VERSION 5.8 ;
BUSBITCHARS "[]" ;
DIVIDERCHAR "/" ;
UNITS
    DATABASE MICRONS 1000 ;
END UNITS

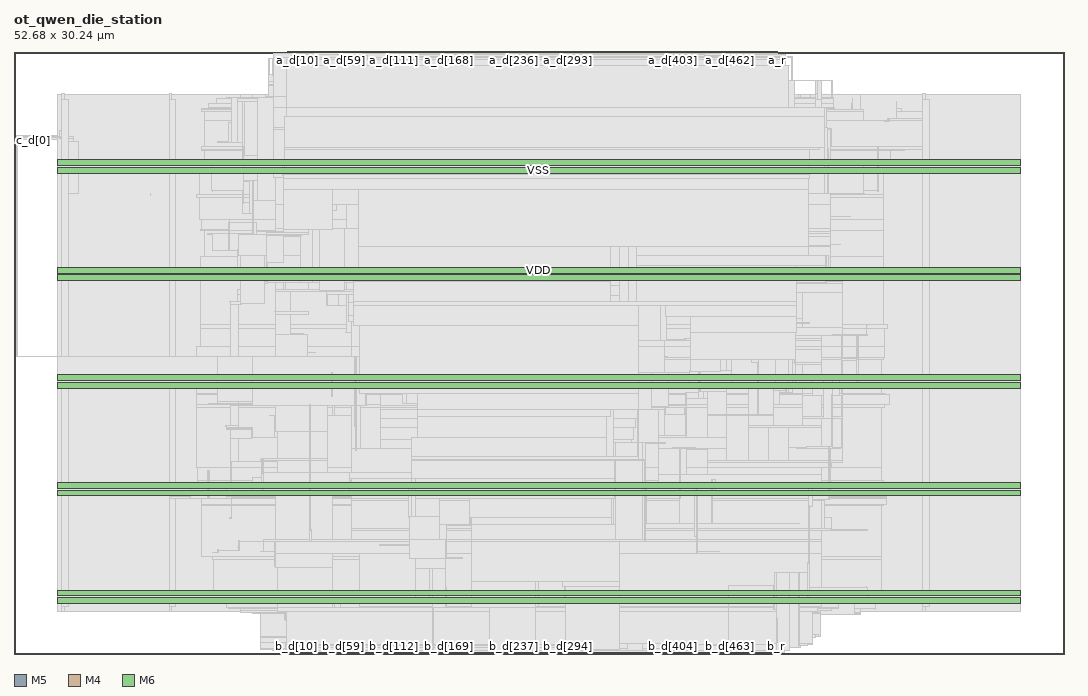
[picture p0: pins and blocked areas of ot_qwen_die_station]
MACRO ot_qwen_die_station
  FOREIGN ot_qwen_die_station 0 0 ;
  CLASS BLOCK ;
  SIZE 52.68 BY 30.24 ;
  PIN a_d[0]
    DIRECTION INPUT ;
    USE SIGNAL ;
    PORT
      LAYER M5 ;
        RECT  13.728 30.156 13.752 30.24 ;
    END
  END a_d[0]
  PIN a_d[100]
    DIRECTION INPUT ;
    USE SIGNAL ;
    PORT
      LAYER M5 ;
        RECT  18.528 30.156 18.552 30.24 ;
    END
  END a_d[100]
  PIN a_d[101]
    DIRECTION INPUT ;
    USE SIGNAL ;
    PORT
      LAYER M5 ;
        RECT  18.576 30.156 18.6 30.24 ;
    END
  END a_d[101]
  PIN a_d[102]
    DIRECTION INPUT ;
    USE SIGNAL ;
    PORT
      LAYER M5 ;
        RECT  18.624 30.156 18.648 30.24 ;
    END
  END a_d[102]
  PIN a_d[103]
    DIRECTION INPUT ;
    USE SIGNAL ;
    PORT
      LAYER M5 ;
        RECT  18.672 30.156 18.696 30.24 ;
    END
  END a_d[103]
  PIN a_d[104]
    DIRECTION INPUT ;
    USE SIGNAL ;
    PORT
      LAYER M5 ;
        RECT  18.72 30.156 18.744 30.24 ;
    END
  END a_d[104]
  PIN a_d[105]
    DIRECTION INPUT ;
    USE SIGNAL ;
    PORT
      LAYER M5 ;
        RECT  18.768 30.156 18.792 30.24 ;
    END
  END a_d[105]
  PIN a_d[106]
    DIRECTION INPUT ;
    USE SIGNAL ;
    PORT
      LAYER M5 ;
        RECT  18.816 30.156 18.84 30.24 ;
    END
  END a_d[106]
  PIN a_d[107]
    DIRECTION INPUT ;
    USE SIGNAL ;
    PORT
      LAYER M5 ;
        RECT  18.864 30.156 18.888 30.24 ;
    END
  END a_d[107]
  PIN a_d[108]
    DIRECTION INPUT ;
    USE SIGNAL ;
    PORT
      LAYER M5 ;
        RECT  18.912 30.156 18.936 30.24 ;
    END
  END a_d[108]
  PIN a_d[109]
    DIRECTION INPUT ;
    USE SIGNAL ;
    PORT
      LAYER M5 ;
        RECT  18.96 30.156 18.984 30.24 ;
    END
  END a_d[109]
  PIN a_d[10]
    DIRECTION INPUT ;
    USE SIGNAL ;
    PORT
      LAYER M5 ;
        RECT  14.208 30.156 14.232 30.24 ;
    END
  END a_d[10]
  PIN a_d[110]
    DIRECTION INPUT ;
    USE SIGNAL ;
    PORT
      LAYER M5 ;
        RECT  19.008 30.156 19.032 30.24 ;
    END
  END a_d[110]
  PIN a_d[111]
    DIRECTION INPUT ;
    USE SIGNAL ;
    PORT
      LAYER M5 ;
        RECT  19.056 30.156 19.08 30.24 ;
    END
  END a_d[111]
  PIN a_d[112]
    DIRECTION INPUT ;
    USE SIGNAL ;
    PORT
      LAYER M5 ;
        RECT  19.104 30.156 19.128 30.24 ;
    END
  END a_d[112]
  PIN a_d[113]
    DIRECTION INPUT ;
    USE SIGNAL ;
    PORT
      LAYER M5 ;
        RECT  19.152 30.156 19.176 30.24 ;
    END
  END a_d[113]
  PIN a_d[114]
    DIRECTION INPUT ;
    USE SIGNAL ;
    PORT
      LAYER M5 ;
        RECT  19.2 30.156 19.224 30.24 ;
    END
  END a_d[114]
  PIN a_d[115]
    DIRECTION INPUT ;
    USE SIGNAL ;
    PORT
      LAYER M5 ;
        RECT  19.248 30.156 19.272 30.24 ;
    END
  END a_d[115]
  PIN a_d[116]
    DIRECTION INPUT ;
    USE SIGNAL ;
    PORT
      LAYER M5 ;
        RECT  19.296 30.156 19.32 30.24 ;
    END
  END a_d[116]
  PIN a_d[117]
    DIRECTION INPUT ;
    USE SIGNAL ;
    PORT
      LAYER M5 ;
        RECT  19.344 30.156 19.368 30.24 ;
    END
  END a_d[117]
  PIN a_d[118]
    DIRECTION INPUT ;
    USE SIGNAL ;
    PORT
      LAYER M5 ;
        RECT  19.392 30.156 19.416 30.24 ;
    END
  END a_d[118]
  PIN a_d[119]
    DIRECTION INPUT ;
    USE SIGNAL ;
    PORT
      LAYER M5 ;
        RECT  19.44 30.156 19.464 30.24 ;
    END
  END a_d[119]
  PIN a_d[11]
    DIRECTION INPUT ;
    USE SIGNAL ;
    PORT
      LAYER M5 ;
        RECT  14.256 30.156 14.28 30.24 ;
    END
  END a_d[11]
  PIN a_d[120]
    DIRECTION INPUT ;
    USE SIGNAL ;
    PORT
      LAYER M5 ;
        RECT  19.488 30.156 19.512 30.24 ;
    END
  END a_d[120]
  PIN a_d[121]
    DIRECTION INPUT ;
    USE SIGNAL ;
    PORT
      LAYER M5 ;
        RECT  19.536 30.156 19.56 30.24 ;
    END
  END a_d[121]
  PIN a_d[122]
    DIRECTION INPUT ;
    USE SIGNAL ;
    PORT
      LAYER M5 ;
        RECT  19.584 30.156 19.608 30.24 ;
    END
  END a_d[122]
  PIN a_d[123]
    DIRECTION INPUT ;
    USE SIGNAL ;
    PORT
      LAYER M5 ;
        RECT  19.632 30.156 19.656 30.24 ;
    END
  END a_d[123]
  PIN a_d[124]
    DIRECTION INPUT ;
    USE SIGNAL ;
    PORT
      LAYER M5 ;
        RECT  19.68 30.156 19.704 30.24 ;
    END
  END a_d[124]
  PIN a_d[125]
    DIRECTION INPUT ;
    USE SIGNAL ;
    PORT
      LAYER M5 ;
        RECT  19.728 30.156 19.752 30.24 ;
    END
  END a_d[125]
  PIN a_d[126]
    DIRECTION INPUT ;
    USE SIGNAL ;
    PORT
      LAYER M5 ;
        RECT  19.776 30.156 19.8 30.24 ;
    END
  END a_d[126]
  PIN a_d[127]
    DIRECTION INPUT ;
    USE SIGNAL ;
    PORT
      LAYER M5 ;
        RECT  19.824 30.156 19.848 30.24 ;
    END
  END a_d[127]
  PIN a_d[128]
    DIRECTION INPUT ;
    USE SIGNAL ;
    PORT
      LAYER M5 ;
        RECT  19.872 30.156 19.896 30.24 ;
    END
  END a_d[128]
  PIN a_d[129]
    DIRECTION INPUT ;
    USE SIGNAL ;
    PORT
      LAYER M5 ;
        RECT  19.92 30.156 19.944 30.24 ;
    END
  END a_d[129]
  PIN a_d[12]
    DIRECTION INPUT ;
    USE SIGNAL ;
    PORT
      LAYER M5 ;
        RECT  14.304 30.156 14.328 30.24 ;
    END
  END a_d[12]
  PIN a_d[130]
    DIRECTION INPUT ;
    USE SIGNAL ;
    PORT
      LAYER M5 ;
        RECT  19.968 30.156 19.992 30.24 ;
    END
  END a_d[130]
  PIN a_d[131]
    DIRECTION INPUT ;
    USE SIGNAL ;
    PORT
      LAYER M5 ;
        RECT  20.016 30.156 20.04 30.24 ;
    END
  END a_d[131]
  PIN a_d[132]
    DIRECTION INPUT ;
    USE SIGNAL ;
    PORT
      LAYER M5 ;
        RECT  20.064 30.156 20.088 30.24 ;
    END
  END a_d[132]
  PIN a_d[133]
    DIRECTION INPUT ;
    USE SIGNAL ;
    PORT
      LAYER M5 ;
        RECT  20.112 30.156 20.136 30.24 ;
    END
  END a_d[133]
  PIN a_d[134]
    DIRECTION INPUT ;
    USE SIGNAL ;
    PORT
      LAYER M5 ;
        RECT  20.16 30.156 20.184 30.24 ;
    END
  END a_d[134]
  PIN a_d[135]
    DIRECTION INPUT ;
    USE SIGNAL ;
    PORT
      LAYER M5 ;
        RECT  20.208 30.156 20.232 30.24 ;
    END
  END a_d[135]
  PIN a_d[136]
    DIRECTION INPUT ;
    USE SIGNAL ;
    PORT
      LAYER M5 ;
        RECT  20.256 30.156 20.28 30.24 ;
    END
  END a_d[136]
  PIN a_d[137]
    DIRECTION INPUT ;
    USE SIGNAL ;
    PORT
      LAYER M5 ;
        RECT  20.304 30.156 20.328 30.24 ;
    END
  END a_d[137]
  PIN a_d[138]
    DIRECTION INPUT ;
    USE SIGNAL ;
    PORT
      LAYER M5 ;
        RECT  20.352 30.156 20.376 30.24 ;
    END
  END a_d[138]
  PIN a_d[139]
    DIRECTION INPUT ;
    USE SIGNAL ;
    PORT
      LAYER M5 ;
        RECT  20.4 30.156 20.424 30.24 ;
    END
  END a_d[139]
  PIN a_d[13]
    DIRECTION INPUT ;
    USE SIGNAL ;
    PORT
      LAYER M5 ;
        RECT  14.352 30.156 14.376 30.24 ;
    END
  END a_d[13]
  PIN a_d[140]
    DIRECTION INPUT ;
    USE SIGNAL ;
    PORT
      LAYER M5 ;
        RECT  20.448 30.156 20.472 30.24 ;
    END
  END a_d[140]
  PIN a_d[141]
    DIRECTION INPUT ;
    USE SIGNAL ;
    PORT
      LAYER M5 ;
        RECT  20.496 30.156 20.52 30.24 ;
    END
  END a_d[141]
  PIN a_d[142]
    DIRECTION INPUT ;
    USE SIGNAL ;
    PORT
      LAYER M5 ;
        RECT  20.544 30.156 20.568 30.24 ;
    END
  END a_d[142]
  PIN a_d[143]
    DIRECTION INPUT ;
    USE SIGNAL ;
    PORT
      LAYER M5 ;
        RECT  20.592 30.156 20.616 30.24 ;
    END
  END a_d[143]
  PIN a_d[144]
    DIRECTION INPUT ;
    USE SIGNAL ;
    PORT
      LAYER M5 ;
        RECT  20.64 30.156 20.664 30.24 ;
    END
  END a_d[144]
  PIN a_d[145]
    DIRECTION INPUT ;
    USE SIGNAL ;
    PORT
      LAYER M5 ;
        RECT  20.688 30.156 20.712 30.24 ;
    END
  END a_d[145]
  PIN a_d[146]
    DIRECTION INPUT ;
    USE SIGNAL ;
    PORT
      LAYER M5 ;
        RECT  20.736 30.156 20.76 30.24 ;
    END
  END a_d[146]
  PIN a_d[147]
    DIRECTION INPUT ;
    USE SIGNAL ;
    PORT
      LAYER M5 ;
        RECT  20.784 30.156 20.808 30.24 ;
    END
  END a_d[147]
  PIN a_d[148]
    DIRECTION INPUT ;
    USE SIGNAL ;
    PORT
      LAYER M5 ;
        RECT  20.832 30.156 20.856 30.24 ;
    END
  END a_d[148]
  PIN a_d[149]
    DIRECTION INPUT ;
    USE SIGNAL ;
    PORT
      LAYER M5 ;
        RECT  20.88 30.156 20.904 30.24 ;
    END
  END a_d[149]
  PIN a_d[14]
    DIRECTION INPUT ;
    USE SIGNAL ;
    PORT
      LAYER M5 ;
        RECT  14.4 30.156 14.424 30.24 ;
    END
  END a_d[14]
  PIN a_d[150]
    DIRECTION INPUT ;
    USE SIGNAL ;
    PORT
      LAYER M5 ;
        RECT  20.928 30.156 20.952 30.24 ;
    END
  END a_d[150]
  PIN a_d[151]
    DIRECTION INPUT ;
    USE SIGNAL ;
    PORT
      LAYER M5 ;
        RECT  20.976 30.156 21 30.24 ;
    END
  END a_d[151]
  PIN a_d[152]
    DIRECTION INPUT ;
    USE SIGNAL ;
    PORT
      LAYER M5 ;
        RECT  21.024 30.156 21.048 30.24 ;
    END
  END a_d[152]
  PIN a_d[153]
    DIRECTION INPUT ;
    USE SIGNAL ;
    PORT
      LAYER M5 ;
        RECT  21.072 30.156 21.096 30.24 ;
    END
  END a_d[153]
  PIN a_d[154]
    DIRECTION INPUT ;
    USE SIGNAL ;
    PORT
      LAYER M5 ;
        RECT  21.12 30.156 21.144 30.24 ;
    END
  END a_d[154]
  PIN a_d[155]
    DIRECTION INPUT ;
    USE SIGNAL ;
    PORT
      LAYER M5 ;
        RECT  21.168 30.156 21.192 30.24 ;
    END
  END a_d[155]
  PIN a_d[156]
    DIRECTION INPUT ;
    USE SIGNAL ;
    PORT
      LAYER M5 ;
        RECT  21.216 30.156 21.24 30.24 ;
    END
  END a_d[156]
  PIN a_d[157]
    DIRECTION INPUT ;
    USE SIGNAL ;
    PORT
      LAYER M5 ;
        RECT  21.264 30.156 21.288 30.24 ;
    END
  END a_d[157]
  PIN a_d[158]
    DIRECTION INPUT ;
    USE SIGNAL ;
    PORT
      LAYER M5 ;
        RECT  21.312 30.156 21.336 30.24 ;
    END
  END a_d[158]
  PIN a_d[159]
    DIRECTION INPUT ;
    USE SIGNAL ;
    PORT
      LAYER M5 ;
        RECT  21.36 30.156 21.384 30.24 ;
    END
  END a_d[159]
  PIN a_d[15]
    DIRECTION INPUT ;
    USE SIGNAL ;
    PORT
      LAYER M5 ;
        RECT  14.448 30.156 14.472 30.24 ;
    END
  END a_d[15]
  PIN a_d[160]
    DIRECTION INPUT ;
    USE SIGNAL ;
    PORT
      LAYER M5 ;
        RECT  21.408 30.156 21.432 30.24 ;
    END
  END a_d[160]
  PIN a_d[161]
    DIRECTION INPUT ;
    USE SIGNAL ;
    PORT
      LAYER M5 ;
        RECT  21.456 30.156 21.48 30.24 ;
    END
  END a_d[161]
  PIN a_d[162]
    DIRECTION INPUT ;
    USE SIGNAL ;
    PORT
      LAYER M5 ;
        RECT  21.504 30.156 21.528 30.24 ;
    END
  END a_d[162]
  PIN a_d[163]
    DIRECTION INPUT ;
    USE SIGNAL ;
    PORT
      LAYER M5 ;
        RECT  21.552 30.156 21.576 30.24 ;
    END
  END a_d[163]
  PIN a_d[164]
    DIRECTION INPUT ;
    USE SIGNAL ;
    PORT
      LAYER M5 ;
        RECT  21.6 30.156 21.624 30.24 ;
    END
  END a_d[164]
  PIN a_d[165]
    DIRECTION INPUT ;
    USE SIGNAL ;
    PORT
      LAYER M5 ;
        RECT  21.648 30.156 21.672 30.24 ;
    END
  END a_d[165]
  PIN a_d[166]
    DIRECTION INPUT ;
    USE SIGNAL ;
    PORT
      LAYER M5 ;
        RECT  21.696 30.156 21.72 30.24 ;
    END
  END a_d[166]
  PIN a_d[167]
    DIRECTION INPUT ;
    USE SIGNAL ;
    PORT
      LAYER M5 ;
        RECT  21.744 30.156 21.768 30.24 ;
    END
  END a_d[167]
  PIN a_d[168]
    DIRECTION INPUT ;
    USE SIGNAL ;
    PORT
      LAYER M5 ;
        RECT  21.792 30.156 21.816 30.24 ;
    END
  END a_d[168]
  PIN a_d[169]
    DIRECTION INPUT ;
    USE SIGNAL ;
    PORT
      LAYER M5 ;
        RECT  21.84 30.156 21.864 30.24 ;
    END
  END a_d[169]
  PIN a_d[16]
    DIRECTION INPUT ;
    USE SIGNAL ;
    PORT
      LAYER M5 ;
        RECT  14.496 30.156 14.52 30.24 ;
    END
  END a_d[16]
  PIN a_d[170]
    DIRECTION INPUT ;
    USE SIGNAL ;
    PORT
      LAYER M5 ;
        RECT  21.888 30.156 21.912 30.24 ;
    END
  END a_d[170]
  PIN a_d[171]
    DIRECTION INPUT ;
    USE SIGNAL ;
    PORT
      LAYER M5 ;
        RECT  21.936 30.156 21.96 30.24 ;
    END
  END a_d[171]
  PIN a_d[172]
    DIRECTION INPUT ;
    USE SIGNAL ;
    PORT
      LAYER M5 ;
        RECT  21.984 30.156 22.008 30.24 ;
    END
  END a_d[172]
  PIN a_d[173]
    DIRECTION INPUT ;
    USE SIGNAL ;
    PORT
      LAYER M5 ;
        RECT  22.032 30.156 22.056 30.24 ;
    END
  END a_d[173]
  PIN a_d[174]
    DIRECTION INPUT ;
    USE SIGNAL ;
    PORT
      LAYER M5 ;
        RECT  22.08 30.156 22.104 30.24 ;
    END
  END a_d[174]
  PIN a_d[175]
    DIRECTION INPUT ;
    USE SIGNAL ;
    PORT
      LAYER M5 ;
        RECT  22.128 30.156 22.152 30.24 ;
    END
  END a_d[175]
  PIN a_d[176]
    DIRECTION INPUT ;
    USE SIGNAL ;
    PORT
      LAYER M5 ;
        RECT  22.176 30.156 22.2 30.24 ;
    END
  END a_d[176]
  PIN a_d[177]
    DIRECTION INPUT ;
    USE SIGNAL ;
    PORT
      LAYER M5 ;
        RECT  22.224 30.156 22.248 30.24 ;
    END
  END a_d[177]
  PIN a_d[178]
    DIRECTION INPUT ;
    USE SIGNAL ;
    PORT
      LAYER M5 ;
        RECT  22.272 30.156 22.296 30.24 ;
    END
  END a_d[178]
  PIN a_d[179]
    DIRECTION INPUT ;
    USE SIGNAL ;
    PORT
      LAYER M5 ;
        RECT  22.32 30.156 22.344 30.24 ;
    END
  END a_d[179]
  PIN a_d[17]
    DIRECTION INPUT ;
    USE SIGNAL ;
    PORT
      LAYER M5 ;
        RECT  14.544 30.156 14.568 30.24 ;
    END
  END a_d[17]
  PIN a_d[180]
    DIRECTION INPUT ;
    USE SIGNAL ;
    PORT
      LAYER M5 ;
        RECT  22.368 30.156 22.392 30.24 ;
    END
  END a_d[180]
  PIN a_d[181]
    DIRECTION INPUT ;
    USE SIGNAL ;
    PORT
      LAYER M5 ;
        RECT  22.416 30.156 22.44 30.24 ;
    END
  END a_d[181]
  PIN a_d[182]
    DIRECTION INPUT ;
    USE SIGNAL ;
    PORT
      LAYER M5 ;
        RECT  22.464 30.156 22.488 30.24 ;
    END
  END a_d[182]
  PIN a_d[183]
    DIRECTION INPUT ;
    USE SIGNAL ;
    PORT
      LAYER M5 ;
        RECT  22.512 30.156 22.536 30.24 ;
    END
  END a_d[183]
  PIN a_d[184]
    DIRECTION INPUT ;
    USE SIGNAL ;
    PORT
      LAYER M5 ;
        RECT  22.56 30.156 22.584 30.24 ;
    END
  END a_d[184]
  PIN a_d[185]
    DIRECTION INPUT ;
    USE SIGNAL ;
    PORT
      LAYER M5 ;
        RECT  22.608 30.156 22.632 30.24 ;
    END
  END a_d[185]
  PIN a_d[186]
    DIRECTION INPUT ;
    USE SIGNAL ;
    PORT
      LAYER M5 ;
        RECT  22.656 30.156 22.68 30.24 ;
    END
  END a_d[186]
  PIN a_d[187]
    DIRECTION INPUT ;
    USE SIGNAL ;
    PORT
      LAYER M5 ;
        RECT  22.704 30.156 22.728 30.24 ;
    END
  END a_d[187]
  PIN a_d[188]
    DIRECTION INPUT ;
    USE SIGNAL ;
    PORT
      LAYER M5 ;
        RECT  22.752 30.156 22.776 30.24 ;
    END
  END a_d[188]
  PIN a_d[189]
    DIRECTION INPUT ;
    USE SIGNAL ;
    PORT
      LAYER M5 ;
        RECT  22.8 30.156 22.824 30.24 ;
    END
  END a_d[189]
  PIN a_d[18]
    DIRECTION INPUT ;
    USE SIGNAL ;
    PORT
      LAYER M5 ;
        RECT  14.592 30.156 14.616 30.24 ;
    END
  END a_d[18]
  PIN a_d[190]
    DIRECTION INPUT ;
    USE SIGNAL ;
    PORT
      LAYER M5 ;
        RECT  22.848 30.156 22.872 30.24 ;
    END
  END a_d[190]
  PIN a_d[191]
    DIRECTION INPUT ;
    USE SIGNAL ;
    PORT
      LAYER M5 ;
        RECT  22.896 30.156 22.92 30.24 ;
    END
  END a_d[191]
  PIN a_d[192]
    DIRECTION INPUT ;
    USE SIGNAL ;
    PORT
      LAYER M5 ;
        RECT  22.944 30.156 22.968 30.24 ;
    END
  END a_d[192]
  PIN a_d[193]
    DIRECTION INPUT ;
    USE SIGNAL ;
    PORT
      LAYER M5 ;
        RECT  22.992 30.156 23.016 30.24 ;
    END
  END a_d[193]
  PIN a_d[194]
    DIRECTION INPUT ;
    USE SIGNAL ;
    PORT
      LAYER M5 ;
        RECT  23.04 30.156 23.064 30.24 ;
    END
  END a_d[194]
  PIN a_d[195]
    DIRECTION INPUT ;
    USE SIGNAL ;
    PORT
      LAYER M5 ;
        RECT  23.088 30.156 23.112 30.24 ;
    END
  END a_d[195]
  PIN a_d[196]
    DIRECTION INPUT ;
    USE SIGNAL ;
    PORT
      LAYER M5 ;
        RECT  23.136 30.156 23.16 30.24 ;
    END
  END a_d[196]
  PIN a_d[197]
    DIRECTION INPUT ;
    USE SIGNAL ;
    PORT
      LAYER M5 ;
        RECT  23.184 30.156 23.208 30.24 ;
    END
  END a_d[197]
  PIN a_d[198]
    DIRECTION INPUT ;
    USE SIGNAL ;
    PORT
      LAYER M5 ;
        RECT  23.232 30.156 23.256 30.24 ;
    END
  END a_d[198]
  PIN a_d[199]
    DIRECTION INPUT ;
    USE SIGNAL ;
    PORT
      LAYER M5 ;
        RECT  23.28 30.156 23.304 30.24 ;
    END
  END a_d[199]
  PIN a_d[19]
    DIRECTION INPUT ;
    USE SIGNAL ;
    PORT
      LAYER M5 ;
        RECT  14.64 30.156 14.664 30.24 ;
    END
  END a_d[19]
  PIN a_d[1]
    DIRECTION INPUT ;
    USE SIGNAL ;
    PORT
      LAYER M5 ;
        RECT  13.776 30.156 13.8 30.24 ;
    END
  END a_d[1]
  PIN a_d[200]
    DIRECTION INPUT ;
    USE SIGNAL ;
    PORT
      LAYER M5 ;
        RECT  23.328 30.156 23.352 30.24 ;
    END
  END a_d[200]
  PIN a_d[201]
    DIRECTION INPUT ;
    USE SIGNAL ;
    PORT
      LAYER M5 ;
        RECT  23.376 30.156 23.4 30.24 ;
    END
  END a_d[201]
  PIN a_d[202]
    DIRECTION INPUT ;
    USE SIGNAL ;
    PORT
      LAYER M5 ;
        RECT  23.424 30.156 23.448 30.24 ;
    END
  END a_d[202]
  PIN a_d[203]
    DIRECTION INPUT ;
    USE SIGNAL ;
    PORT
      LAYER M5 ;
        RECT  23.472 30.156 23.496 30.24 ;
    END
  END a_d[203]
  PIN a_d[204]
    DIRECTION INPUT ;
    USE SIGNAL ;
    PORT
      LAYER M5 ;
        RECT  23.52 30.156 23.544 30.24 ;
    END
  END a_d[204]
  PIN a_d[205]
    DIRECTION INPUT ;
    USE SIGNAL ;
    PORT
      LAYER M5 ;
        RECT  23.568 30.156 23.592 30.24 ;
    END
  END a_d[205]
  PIN a_d[206]
    DIRECTION INPUT ;
    USE SIGNAL ;
    PORT
      LAYER M5 ;
        RECT  23.616 30.156 23.64 30.24 ;
    END
  END a_d[206]
  PIN a_d[207]
    DIRECTION INPUT ;
    USE SIGNAL ;
    PORT
      LAYER M5 ;
        RECT  23.664 30.156 23.688 30.24 ;
    END
  END a_d[207]
  PIN a_d[208]
    DIRECTION INPUT ;
    USE SIGNAL ;
    PORT
      LAYER M5 ;
        RECT  23.712 30.156 23.736 30.24 ;
    END
  END a_d[208]
  PIN a_d[209]
    DIRECTION INPUT ;
    USE SIGNAL ;
    PORT
      LAYER M5 ;
        RECT  23.76 30.156 23.784 30.24 ;
    END
  END a_d[209]
  PIN a_d[20]
    DIRECTION INPUT ;
    USE SIGNAL ;
    PORT
      LAYER M5 ;
        RECT  14.688 30.156 14.712 30.24 ;
    END
  END a_d[20]
  PIN a_d[210]
    DIRECTION INPUT ;
    USE SIGNAL ;
    PORT
      LAYER M5 ;
        RECT  23.808 30.156 23.832 30.24 ;
    END
  END a_d[210]
  PIN a_d[211]
    DIRECTION INPUT ;
    USE SIGNAL ;
    PORT
      LAYER M5 ;
        RECT  23.856 30.156 23.88 30.24 ;
    END
  END a_d[211]
  PIN a_d[212]
    DIRECTION INPUT ;
    USE SIGNAL ;
    PORT
      LAYER M5 ;
        RECT  23.904 30.156 23.928 30.24 ;
    END
  END a_d[212]
  PIN a_d[213]
    DIRECTION INPUT ;
    USE SIGNAL ;
    PORT
      LAYER M5 ;
        RECT  23.952 30.156 23.976 30.24 ;
    END
  END a_d[213]
  PIN a_d[214]
    DIRECTION INPUT ;
    USE SIGNAL ;
    PORT
      LAYER M5 ;
        RECT  24 30.156 24.024 30.24 ;
    END
  END a_d[214]
  PIN a_d[215]
    DIRECTION INPUT ;
    USE SIGNAL ;
    PORT
      LAYER M5 ;
        RECT  24.048 30.156 24.072 30.24 ;
    END
  END a_d[215]
  PIN a_d[216]
    DIRECTION INPUT ;
    USE SIGNAL ;
    PORT
      LAYER M5 ;
        RECT  24.096 30.156 24.12 30.24 ;
    END
  END a_d[216]
  PIN a_d[217]
    DIRECTION INPUT ;
    USE SIGNAL ;
    PORT
      LAYER M5 ;
        RECT  24.144 30.156 24.168 30.24 ;
    END
  END a_d[217]
  PIN a_d[218]
    DIRECTION INPUT ;
    USE SIGNAL ;
    PORT
      LAYER M5 ;
        RECT  24.192 30.156 24.216 30.24 ;
    END
  END a_d[218]
  PIN a_d[219]
    DIRECTION INPUT ;
    USE SIGNAL ;
    PORT
      LAYER M5 ;
        RECT  24.24 30.156 24.264 30.24 ;
    END
  END a_d[219]
  PIN a_d[21]
    DIRECTION INPUT ;
    USE SIGNAL ;
    PORT
      LAYER M5 ;
        RECT  14.736 30.156 14.76 30.24 ;
    END
  END a_d[21]
  PIN a_d[220]
    DIRECTION INPUT ;
    USE SIGNAL ;
    PORT
      LAYER M5 ;
        RECT  24.288 30.156 24.312 30.24 ;
    END
  END a_d[220]
  PIN a_d[221]
    DIRECTION INPUT ;
    USE SIGNAL ;
    PORT
      LAYER M5 ;
        RECT  24.336 30.156 24.36 30.24 ;
    END
  END a_d[221]
  PIN a_d[222]
    DIRECTION INPUT ;
    USE SIGNAL ;
    PORT
      LAYER M5 ;
        RECT  24.384 30.156 24.408 30.24 ;
    END
  END a_d[222]
  PIN a_d[223]
    DIRECTION INPUT ;
    USE SIGNAL ;
    PORT
      LAYER M5 ;
        RECT  24.432 30.156 24.456 30.24 ;
    END
  END a_d[223]
  PIN a_d[224]
    DIRECTION INPUT ;
    USE SIGNAL ;
    PORT
      LAYER M5 ;
        RECT  24.48 30.156 24.504 30.24 ;
    END
  END a_d[224]
  PIN a_d[225]
    DIRECTION INPUT ;
    USE SIGNAL ;
    PORT
      LAYER M5 ;
        RECT  24.528 30.156 24.552 30.24 ;
    END
  END a_d[225]
  PIN a_d[226]
    DIRECTION INPUT ;
    USE SIGNAL ;
    PORT
      LAYER M5 ;
        RECT  24.576 30.156 24.6 30.24 ;
    END
  END a_d[226]
  PIN a_d[227]
    DIRECTION INPUT ;
    USE SIGNAL ;
    PORT
      LAYER M5 ;
        RECT  24.624 30.156 24.648 30.24 ;
    END
  END a_d[227]
  PIN a_d[228]
    DIRECTION INPUT ;
    USE SIGNAL ;
    PORT
      LAYER M5 ;
        RECT  24.672 30.156 24.696 30.24 ;
    END
  END a_d[228]
  PIN a_d[229]
    DIRECTION INPUT ;
    USE SIGNAL ;
    PORT
      LAYER M5 ;
        RECT  24.72 30.156 24.744 30.24 ;
    END
  END a_d[229]
  PIN a_d[22]
    DIRECTION INPUT ;
    USE SIGNAL ;
    PORT
      LAYER M5 ;
        RECT  14.784 30.156 14.808 30.24 ;
    END
  END a_d[22]
  PIN a_d[230]
    DIRECTION INPUT ;
    USE SIGNAL ;
    PORT
      LAYER M5 ;
        RECT  24.768 30.156 24.792 30.24 ;
    END
  END a_d[230]
  PIN a_d[231]
    DIRECTION INPUT ;
    USE SIGNAL ;
    PORT
      LAYER M5 ;
        RECT  24.816 30.156 24.84 30.24 ;
    END
  END a_d[231]
  PIN a_d[232]
    DIRECTION INPUT ;
    USE SIGNAL ;
    PORT
      LAYER M5 ;
        RECT  24.864 30.156 24.888 30.24 ;
    END
  END a_d[232]
  PIN a_d[233]
    DIRECTION INPUT ;
    USE SIGNAL ;
    PORT
      LAYER M5 ;
        RECT  24.912 30.156 24.936 30.24 ;
    END
  END a_d[233]
  PIN a_d[234]
    DIRECTION INPUT ;
    USE SIGNAL ;
    PORT
      LAYER M5 ;
        RECT  24.96 30.156 24.984 30.24 ;
    END
  END a_d[234]
  PIN a_d[235]
    DIRECTION INPUT ;
    USE SIGNAL ;
    PORT
      LAYER M5 ;
        RECT  25.008 30.156 25.032 30.24 ;
    END
  END a_d[235]
  PIN a_d[236]
    DIRECTION INPUT ;
    USE SIGNAL ;
    PORT
      LAYER M5 ;
        RECT  25.056 30.156 25.08 30.24 ;
    END
  END a_d[236]
  PIN a_d[237]
    DIRECTION INPUT ;
    USE SIGNAL ;
    PORT
      LAYER M5 ;
        RECT  25.104 30.156 25.128 30.24 ;
    END
  END a_d[237]
  PIN a_d[238]
    DIRECTION INPUT ;
    USE SIGNAL ;
    PORT
      LAYER M5 ;
        RECT  25.152 30.156 25.176 30.24 ;
    END
  END a_d[238]
  PIN a_d[239]
    DIRECTION INPUT ;
    USE SIGNAL ;
    PORT
      LAYER M5 ;
        RECT  25.2 30.156 25.224 30.24 ;
    END
  END a_d[239]
  PIN a_d[23]
    DIRECTION INPUT ;
    USE SIGNAL ;
    PORT
      LAYER M5 ;
        RECT  14.832 30.156 14.856 30.24 ;
    END
  END a_d[23]
  PIN a_d[240]
    DIRECTION INPUT ;
    USE SIGNAL ;
    PORT
      LAYER M5 ;
        RECT  25.248 30.156 25.272 30.24 ;
    END
  END a_d[240]
  PIN a_d[241]
    DIRECTION INPUT ;
    USE SIGNAL ;
    PORT
      LAYER M5 ;
        RECT  25.296 30.156 25.32 30.24 ;
    END
  END a_d[241]
  PIN a_d[242]
    DIRECTION INPUT ;
    USE SIGNAL ;
    PORT
      LAYER M5 ;
        RECT  25.344 30.156 25.368 30.24 ;
    END
  END a_d[242]
  PIN a_d[243]
    DIRECTION INPUT ;
    USE SIGNAL ;
    PORT
      LAYER M5 ;
        RECT  25.392 30.156 25.416 30.24 ;
    END
  END a_d[243]
  PIN a_d[244]
    DIRECTION INPUT ;
    USE SIGNAL ;
    PORT
      LAYER M5 ;
        RECT  25.44 30.156 25.464 30.24 ;
    END
  END a_d[244]
  PIN a_d[245]
    DIRECTION INPUT ;
    USE SIGNAL ;
    PORT
      LAYER M5 ;
        RECT  25.488 30.156 25.512 30.24 ;
    END
  END a_d[245]
  PIN a_d[246]
    DIRECTION INPUT ;
    USE SIGNAL ;
    PORT
      LAYER M5 ;
        RECT  25.536 30.156 25.56 30.24 ;
    END
  END a_d[246]
  PIN a_d[247]
    DIRECTION INPUT ;
    USE SIGNAL ;
    PORT
      LAYER M5 ;
        RECT  25.584 30.156 25.608 30.24 ;
    END
  END a_d[247]
  PIN a_d[248]
    DIRECTION INPUT ;
    USE SIGNAL ;
    PORT
      LAYER M5 ;
        RECT  25.632 30.156 25.656 30.24 ;
    END
  END a_d[248]
  PIN a_d[249]
    DIRECTION INPUT ;
    USE SIGNAL ;
    PORT
      LAYER M5 ;
        RECT  25.68 30.156 25.704 30.24 ;
    END
  END a_d[249]
  PIN a_d[24]
    DIRECTION INPUT ;
    USE SIGNAL ;
    PORT
      LAYER M5 ;
        RECT  14.88 30.156 14.904 30.24 ;
    END
  END a_d[24]
  PIN a_d[250]
    DIRECTION INPUT ;
    USE SIGNAL ;
    PORT
      LAYER M5 ;
        RECT  25.728 30.156 25.752 30.24 ;
    END
  END a_d[250]
  PIN a_d[251]
    DIRECTION INPUT ;
    USE SIGNAL ;
    PORT
      LAYER M5 ;
        RECT  25.776 30.156 25.8 30.24 ;
    END
  END a_d[251]
  PIN a_d[252]
    DIRECTION INPUT ;
    USE SIGNAL ;
    PORT
      LAYER M5 ;
        RECT  25.824 30.156 25.848 30.24 ;
    END
  END a_d[252]
  PIN a_d[253]
    DIRECTION INPUT ;
    USE SIGNAL ;
    PORT
      LAYER M5 ;
        RECT  25.872 30.156 25.896 30.24 ;
    END
  END a_d[253]
  PIN a_d[254]
    DIRECTION INPUT ;
    USE SIGNAL ;
    PORT
      LAYER M5 ;
        RECT  25.92 30.156 25.944 30.24 ;
    END
  END a_d[254]
  PIN a_d[255]
    DIRECTION INPUT ;
    USE SIGNAL ;
    PORT
      LAYER M5 ;
        RECT  25.968 30.156 25.992 30.24 ;
    END
  END a_d[255]
  PIN a_d[256]
    DIRECTION INPUT ;
    USE SIGNAL ;
    PORT
      LAYER M5 ;
        RECT  26.016 30.156 26.04 30.24 ;
    END
  END a_d[256]
  PIN a_d[257]
    DIRECTION INPUT ;
    USE SIGNAL ;
    PORT
      LAYER M5 ;
        RECT  26.064 30.156 26.088 30.24 ;
    END
  END a_d[257]
  PIN a_d[258]
    DIRECTION INPUT ;
    USE SIGNAL ;
    PORT
      LAYER M5 ;
        RECT  26.112 30.156 26.136 30.24 ;
    END
  END a_d[258]
  PIN a_d[259]
    DIRECTION INPUT ;
    USE SIGNAL ;
    PORT
      LAYER M5 ;
        RECT  26.16 30.156 26.184 30.24 ;
    END
  END a_d[259]
  PIN a_d[25]
    DIRECTION INPUT ;
    USE SIGNAL ;
    PORT
      LAYER M5 ;
        RECT  14.928 30.156 14.952 30.24 ;
    END
  END a_d[25]
  PIN a_d[260]
    DIRECTION INPUT ;
    USE SIGNAL ;
    PORT
      LAYER M5 ;
        RECT  26.208 30.156 26.232 30.24 ;
    END
  END a_d[260]
  PIN a_d[261]
    DIRECTION INPUT ;
    USE SIGNAL ;
    PORT
      LAYER M5 ;
        RECT  26.256 30.156 26.28 30.24 ;
    END
  END a_d[261]
  PIN a_d[262]
    DIRECTION INPUT ;
    USE SIGNAL ;
    PORT
      LAYER M5 ;
        RECT  26.304 30.156 26.328 30.24 ;
    END
  END a_d[262]
  PIN a_d[263]
    DIRECTION INPUT ;
    USE SIGNAL ;
    PORT
      LAYER M5 ;
        RECT  26.352 30.156 26.376 30.24 ;
    END
  END a_d[263]
  PIN a_d[264]
    DIRECTION INPUT ;
    USE SIGNAL ;
    PORT
      LAYER M5 ;
        RECT  26.4 30.156 26.424 30.24 ;
    END
  END a_d[264]
  PIN a_d[265]
    DIRECTION INPUT ;
    USE SIGNAL ;
    PORT
      LAYER M5 ;
        RECT  26.448 30.156 26.472 30.24 ;
    END
  END a_d[265]
  PIN a_d[266]
    DIRECTION INPUT ;
    USE SIGNAL ;
    PORT
      LAYER M5 ;
        RECT  26.496 30.156 26.52 30.24 ;
    END
  END a_d[266]
  PIN a_d[267]
    DIRECTION INPUT ;
    USE SIGNAL ;
    PORT
      LAYER M5 ;
        RECT  26.544 30.156 26.568 30.24 ;
    END
  END a_d[267]
  PIN a_d[268]
    DIRECTION INPUT ;
    USE SIGNAL ;
    PORT
      LAYER M5 ;
        RECT  26.592 30.156 26.616 30.24 ;
    END
  END a_d[268]
  PIN a_d[269]
    DIRECTION INPUT ;
    USE SIGNAL ;
    PORT
      LAYER M5 ;
        RECT  26.64 30.156 26.664 30.24 ;
    END
  END a_d[269]
  PIN a_d[26]
    DIRECTION INPUT ;
    USE SIGNAL ;
    PORT
      LAYER M5 ;
        RECT  14.976 30.156 15 30.24 ;
    END
  END a_d[26]
  PIN a_d[270]
    DIRECTION INPUT ;
    USE SIGNAL ;
    PORT
      LAYER M5 ;
        RECT  26.688 30.156 26.712 30.24 ;
    END
  END a_d[270]
  PIN a_d[271]
    DIRECTION INPUT ;
    USE SIGNAL ;
    PORT
      LAYER M5 ;
        RECT  26.736 30.156 26.76 30.24 ;
    END
  END a_d[271]
  PIN a_d[272]
    DIRECTION INPUT ;
    USE SIGNAL ;
    PORT
      LAYER M5 ;
        RECT  26.784 30.156 26.808 30.24 ;
    END
  END a_d[272]
  PIN a_d[273]
    DIRECTION INPUT ;
    USE SIGNAL ;
    PORT
      LAYER M5 ;
        RECT  26.832 30.156 26.856 30.24 ;
    END
  END a_d[273]
  PIN a_d[274]
    DIRECTION INPUT ;
    USE SIGNAL ;
    PORT
      LAYER M5 ;
        RECT  26.88 30.156 26.904 30.24 ;
    END
  END a_d[274]
  PIN a_d[275]
    DIRECTION INPUT ;
    USE SIGNAL ;
    PORT
      LAYER M5 ;
        RECT  26.928 30.156 26.952 30.24 ;
    END
  END a_d[275]
  PIN a_d[276]
    DIRECTION INPUT ;
    USE SIGNAL ;
    PORT
      LAYER M5 ;
        RECT  26.976 30.156 27 30.24 ;
    END
  END a_d[276]
  PIN a_d[277]
    DIRECTION INPUT ;
    USE SIGNAL ;
    PORT
      LAYER M5 ;
        RECT  27.024 30.156 27.048 30.24 ;
    END
  END a_d[277]
  PIN a_d[278]
    DIRECTION INPUT ;
    USE SIGNAL ;
    PORT
      LAYER M5 ;
        RECT  27.072 30.156 27.096 30.24 ;
    END
  END a_d[278]
  PIN a_d[279]
    DIRECTION INPUT ;
    USE SIGNAL ;
    PORT
      LAYER M5 ;
        RECT  27.12 30.156 27.144 30.24 ;
    END
  END a_d[279]
  PIN a_d[27]
    DIRECTION INPUT ;
    USE SIGNAL ;
    PORT
      LAYER M5 ;
        RECT  15.024 30.156 15.048 30.24 ;
    END
  END a_d[27]
  PIN a_d[280]
    DIRECTION INPUT ;
    USE SIGNAL ;
    PORT
      LAYER M5 ;
        RECT  27.168 30.156 27.192 30.24 ;
    END
  END a_d[280]
  PIN a_d[281]
    DIRECTION INPUT ;
    USE SIGNAL ;
    PORT
      LAYER M5 ;
        RECT  27.216 30.156 27.24 30.24 ;
    END
  END a_d[281]
  PIN a_d[282]
    DIRECTION INPUT ;
    USE SIGNAL ;
    PORT
      LAYER M5 ;
        RECT  27.264 30.156 27.288 30.24 ;
    END
  END a_d[282]
  PIN a_d[283]
    DIRECTION INPUT ;
    USE SIGNAL ;
    PORT
      LAYER M5 ;
        RECT  27.312 30.156 27.336 30.24 ;
    END
  END a_d[283]
  PIN a_d[284]
    DIRECTION INPUT ;
    USE SIGNAL ;
    PORT
      LAYER M5 ;
        RECT  27.36 30.156 27.384 30.24 ;
    END
  END a_d[284]
  PIN a_d[285]
    DIRECTION INPUT ;
    USE SIGNAL ;
    PORT
      LAYER M5 ;
        RECT  27.408 30.156 27.432 30.24 ;
    END
  END a_d[285]
  PIN a_d[286]
    DIRECTION INPUT ;
    USE SIGNAL ;
    PORT
      LAYER M5 ;
        RECT  27.456 30.156 27.48 30.24 ;
    END
  END a_d[286]
  PIN a_d[287]
    DIRECTION INPUT ;
    USE SIGNAL ;
    PORT
      LAYER M5 ;
        RECT  27.504 30.156 27.528 30.24 ;
    END
  END a_d[287]
  PIN a_d[288]
    DIRECTION INPUT ;
    USE SIGNAL ;
    PORT
      LAYER M5 ;
        RECT  27.552 30.156 27.576 30.24 ;
    END
  END a_d[288]
  PIN a_d[289]
    DIRECTION INPUT ;
    USE SIGNAL ;
    PORT
      LAYER M5 ;
        RECT  27.6 30.156 27.624 30.24 ;
    END
  END a_d[289]
  PIN a_d[28]
    DIRECTION INPUT ;
    USE SIGNAL ;
    PORT
      LAYER M5 ;
        RECT  15.072 30.156 15.096 30.24 ;
    END
  END a_d[28]
  PIN a_d[290]
    DIRECTION INPUT ;
    USE SIGNAL ;
    PORT
      LAYER M5 ;
        RECT  27.648 30.156 27.672 30.24 ;
    END
  END a_d[290]
  PIN a_d[291]
    DIRECTION INPUT ;
    USE SIGNAL ;
    PORT
      LAYER M5 ;
        RECT  27.696 30.156 27.72 30.24 ;
    END
  END a_d[291]
  PIN a_d[292]
    DIRECTION INPUT ;
    USE SIGNAL ;
    PORT
      LAYER M5 ;
        RECT  27.744 30.156 27.768 30.24 ;
    END
  END a_d[292]
  PIN a_d[293]
    DIRECTION INPUT ;
    USE SIGNAL ;
    PORT
      LAYER M5 ;
        RECT  27.792 30.156 27.816 30.24 ;
    END
  END a_d[293]
  PIN a_d[294]
    DIRECTION INPUT ;
    USE SIGNAL ;
    PORT
      LAYER M5 ;
        RECT  27.84 30.156 27.864 30.24 ;
    END
  END a_d[294]
  PIN a_d[295]
    DIRECTION INPUT ;
    USE SIGNAL ;
    PORT
      LAYER M5 ;
        RECT  27.888 30.156 27.912 30.24 ;
    END
  END a_d[295]
  PIN a_d[296]
    DIRECTION INPUT ;
    USE SIGNAL ;
    PORT
      LAYER M5 ;
        RECT  27.936 30.156 27.96 30.24 ;
    END
  END a_d[296]
  PIN a_d[297]
    DIRECTION INPUT ;
    USE SIGNAL ;
    PORT
      LAYER M5 ;
        RECT  27.984 30.156 28.008 30.24 ;
    END
  END a_d[297]
  PIN a_d[298]
    DIRECTION INPUT ;
    USE SIGNAL ;
    PORT
      LAYER M5 ;
        RECT  28.032 30.156 28.056 30.24 ;
    END
  END a_d[298]
  PIN a_d[299]
    DIRECTION INPUT ;
    USE SIGNAL ;
    PORT
      LAYER M5 ;
        RECT  28.08 30.156 28.104 30.24 ;
    END
  END a_d[299]
  PIN a_d[29]
    DIRECTION INPUT ;
    USE SIGNAL ;
    PORT
      LAYER M5 ;
        RECT  15.12 30.156 15.144 30.24 ;
    END
  END a_d[29]
  PIN a_d[2]
    DIRECTION INPUT ;
    USE SIGNAL ;
    PORT
      LAYER M5 ;
        RECT  13.824 30.156 13.848 30.24 ;
    END
  END a_d[2]
  PIN a_d[300]
    DIRECTION INPUT ;
    USE SIGNAL ;
    PORT
      LAYER M5 ;
        RECT  28.128 30.156 28.152 30.24 ;
    END
  END a_d[300]
  PIN a_d[301]
    DIRECTION INPUT ;
    USE SIGNAL ;
    PORT
      LAYER M5 ;
        RECT  28.176 30.156 28.2 30.24 ;
    END
  END a_d[301]
  PIN a_d[302]
    DIRECTION INPUT ;
    USE SIGNAL ;
    PORT
      LAYER M5 ;
        RECT  28.224 30.156 28.248 30.24 ;
    END
  END a_d[302]
  PIN a_d[303]
    DIRECTION INPUT ;
    USE SIGNAL ;
    PORT
      LAYER M5 ;
        RECT  28.272 30.156 28.296 30.24 ;
    END
  END a_d[303]
  PIN a_d[304]
    DIRECTION INPUT ;
    USE SIGNAL ;
    PORT
      LAYER M5 ;
        RECT  28.32 30.156 28.344 30.24 ;
    END
  END a_d[304]
  PIN a_d[305]
    DIRECTION INPUT ;
    USE SIGNAL ;
    PORT
      LAYER M5 ;
        RECT  28.368 30.156 28.392 30.24 ;
    END
  END a_d[305]
  PIN a_d[306]
    DIRECTION INPUT ;
    USE SIGNAL ;
    PORT
      LAYER M5 ;
        RECT  28.416 30.156 28.44 30.24 ;
    END
  END a_d[306]
  PIN a_d[307]
    DIRECTION INPUT ;
    USE SIGNAL ;
    PORT
      LAYER M5 ;
        RECT  28.464 30.156 28.488 30.24 ;
    END
  END a_d[307]
  PIN a_d[308]
    DIRECTION INPUT ;
    USE SIGNAL ;
    PORT
      LAYER M5 ;
        RECT  28.512 30.156 28.536 30.24 ;
    END
  END a_d[308]
  PIN a_d[309]
    DIRECTION INPUT ;
    USE SIGNAL ;
    PORT
      LAYER M5 ;
        RECT  28.56 30.156 28.584 30.24 ;
    END
  END a_d[309]
  PIN a_d[30]
    DIRECTION INPUT ;
    USE SIGNAL ;
    PORT
      LAYER M5 ;
        RECT  15.168 30.156 15.192 30.24 ;
    END
  END a_d[30]
  PIN a_d[310]
    DIRECTION INPUT ;
    USE SIGNAL ;
    PORT
      LAYER M5 ;
        RECT  28.608 30.156 28.632 30.24 ;
    END
  END a_d[310]
  PIN a_d[311]
    DIRECTION INPUT ;
    USE SIGNAL ;
    PORT
      LAYER M5 ;
        RECT  28.656 30.156 28.68 30.24 ;
    END
  END a_d[311]
  PIN a_d[312]
    DIRECTION INPUT ;
    USE SIGNAL ;
    PORT
      LAYER M5 ;
        RECT  28.704 30.156 28.728 30.24 ;
    END
  END a_d[312]
  PIN a_d[313]
    DIRECTION INPUT ;
    USE SIGNAL ;
    PORT
      LAYER M5 ;
        RECT  28.752 30.156 28.776 30.24 ;
    END
  END a_d[313]
  PIN a_d[314]
    DIRECTION INPUT ;
    USE SIGNAL ;
    PORT
      LAYER M5 ;
        RECT  28.8 30.156 28.824 30.24 ;
    END
  END a_d[314]
  PIN a_d[315]
    DIRECTION INPUT ;
    USE SIGNAL ;
    PORT
      LAYER M5 ;
        RECT  28.848 30.156 28.872 30.24 ;
    END
  END a_d[315]
  PIN a_d[316]
    DIRECTION INPUT ;
    USE SIGNAL ;
    PORT
      LAYER M5 ;
        RECT  28.896 30.156 28.92 30.24 ;
    END
  END a_d[316]
  PIN a_d[317]
    DIRECTION INPUT ;
    USE SIGNAL ;
    PORT
      LAYER M5 ;
        RECT  28.944 30.156 28.968 30.24 ;
    END
  END a_d[317]
  PIN a_d[318]
    DIRECTION INPUT ;
    USE SIGNAL ;
    PORT
      LAYER M5 ;
        RECT  28.992 30.156 29.016 30.24 ;
    END
  END a_d[318]
  PIN a_d[319]
    DIRECTION INPUT ;
    USE SIGNAL ;
    PORT
      LAYER M5 ;
        RECT  29.04 30.156 29.064 30.24 ;
    END
  END a_d[319]
  PIN a_d[31]
    DIRECTION INPUT ;
    USE SIGNAL ;
    PORT
      LAYER M5 ;
        RECT  15.216 30.156 15.24 30.24 ;
    END
  END a_d[31]
  PIN a_d[320]
    DIRECTION INPUT ;
    USE SIGNAL ;
    PORT
      LAYER M5 ;
        RECT  29.088 30.156 29.112 30.24 ;
    END
  END a_d[320]
  PIN a_d[321]
    DIRECTION INPUT ;
    USE SIGNAL ;
    PORT
      LAYER M5 ;
        RECT  29.136 30.156 29.16 30.24 ;
    END
  END a_d[321]
  PIN a_d[322]
    DIRECTION INPUT ;
    USE SIGNAL ;
    PORT
      LAYER M5 ;
        RECT  29.184 30.156 29.208 30.24 ;
    END
  END a_d[322]
  PIN a_d[323]
    DIRECTION INPUT ;
    USE SIGNAL ;
    PORT
      LAYER M5 ;
        RECT  29.232 30.156 29.256 30.24 ;
    END
  END a_d[323]
  PIN a_d[324]
    DIRECTION INPUT ;
    USE SIGNAL ;
    PORT
      LAYER M5 ;
        RECT  29.28 30.156 29.304 30.24 ;
    END
  END a_d[324]
  PIN a_d[325]
    DIRECTION INPUT ;
    USE SIGNAL ;
    PORT
      LAYER M5 ;
        RECT  29.328 30.156 29.352 30.24 ;
    END
  END a_d[325]
  PIN a_d[326]
    DIRECTION INPUT ;
    USE SIGNAL ;
    PORT
      LAYER M5 ;
        RECT  29.376 30.156 29.4 30.24 ;
    END
  END a_d[326]
  PIN a_d[327]
    DIRECTION INPUT ;
    USE SIGNAL ;
    PORT
      LAYER M5 ;
        RECT  29.424 30.156 29.448 30.24 ;
    END
  END a_d[327]
  PIN a_d[328]
    DIRECTION INPUT ;
    USE SIGNAL ;
    PORT
      LAYER M5 ;
        RECT  29.472 30.156 29.496 30.24 ;
    END
  END a_d[328]
  PIN a_d[329]
    DIRECTION INPUT ;
    USE SIGNAL ;
    PORT
      LAYER M5 ;
        RECT  29.52 30.156 29.544 30.24 ;
    END
  END a_d[329]
  PIN a_d[32]
    DIRECTION INPUT ;
    USE SIGNAL ;
    PORT
      LAYER M5 ;
        RECT  15.264 30.156 15.288 30.24 ;
    END
  END a_d[32]
  PIN a_d[330]
    DIRECTION INPUT ;
    USE SIGNAL ;
    PORT
      LAYER M5 ;
        RECT  29.568 30.156 29.592 30.24 ;
    END
  END a_d[330]
  PIN a_d[331]
    DIRECTION INPUT ;
    USE SIGNAL ;
    PORT
      LAYER M5 ;
        RECT  29.616 30.156 29.64 30.24 ;
    END
  END a_d[331]
  PIN a_d[332]
    DIRECTION INPUT ;
    USE SIGNAL ;
    PORT
      LAYER M5 ;
        RECT  29.664 30.156 29.688 30.24 ;
    END
  END a_d[332]
  PIN a_d[333]
    DIRECTION INPUT ;
    USE SIGNAL ;
    PORT
      LAYER M5 ;
        RECT  29.712 30.156 29.736 30.24 ;
    END
  END a_d[333]
  PIN a_d[334]
    DIRECTION INPUT ;
    USE SIGNAL ;
    PORT
      LAYER M5 ;
        RECT  29.76 30.156 29.784 30.24 ;
    END
  END a_d[334]
  PIN a_d[335]
    DIRECTION INPUT ;
    USE SIGNAL ;
    PORT
      LAYER M5 ;
        RECT  29.808 30.156 29.832 30.24 ;
    END
  END a_d[335]
  PIN a_d[336]
    DIRECTION INPUT ;
    USE SIGNAL ;
    PORT
      LAYER M5 ;
        RECT  29.856 30.156 29.88 30.24 ;
    END
  END a_d[336]
  PIN a_d[337]
    DIRECTION INPUT ;
    USE SIGNAL ;
    PORT
      LAYER M5 ;
        RECT  29.904 30.156 29.928 30.24 ;
    END
  END a_d[337]
  PIN a_d[338]
    DIRECTION INPUT ;
    USE SIGNAL ;
    PORT
      LAYER M5 ;
        RECT  29.952 30.156 29.976 30.24 ;
    END
  END a_d[338]
  PIN a_d[339]
    DIRECTION INPUT ;
    USE SIGNAL ;
    PORT
      LAYER M5 ;
        RECT  30 30.156 30.024 30.24 ;
    END
  END a_d[339]
  PIN a_d[33]
    DIRECTION INPUT ;
    USE SIGNAL ;
    PORT
      LAYER M5 ;
        RECT  15.312 30.156 15.336 30.24 ;
    END
  END a_d[33]
  PIN a_d[340]
    DIRECTION INPUT ;
    USE SIGNAL ;
    PORT
      LAYER M5 ;
        RECT  30.048 30.156 30.072 30.24 ;
    END
  END a_d[340]
  PIN a_d[341]
    DIRECTION INPUT ;
    USE SIGNAL ;
    PORT
      LAYER M5 ;
        RECT  30.096 30.156 30.12 30.24 ;
    END
  END a_d[341]
  PIN a_d[342]
    DIRECTION INPUT ;
    USE SIGNAL ;
    PORT
      LAYER M5 ;
        RECT  30.144 30.156 30.168 30.24 ;
    END
  END a_d[342]
  PIN a_d[343]
    DIRECTION INPUT ;
    USE SIGNAL ;
    PORT
      LAYER M5 ;
        RECT  30.192 30.156 30.216 30.24 ;
    END
  END a_d[343]
  PIN a_d[344]
    DIRECTION INPUT ;
    USE SIGNAL ;
    PORT
      LAYER M5 ;
        RECT  30.24 30.156 30.264 30.24 ;
    END
  END a_d[344]
  PIN a_d[345]
    DIRECTION INPUT ;
    USE SIGNAL ;
    PORT
      LAYER M5 ;
        RECT  30.288 30.156 30.312 30.24 ;
    END
  END a_d[345]
  PIN a_d[346]
    DIRECTION INPUT ;
    USE SIGNAL ;
    PORT
      LAYER M5 ;
        RECT  30.336 30.156 30.36 30.24 ;
    END
  END a_d[346]
  PIN a_d[347]
    DIRECTION INPUT ;
    USE SIGNAL ;
    PORT
      LAYER M5 ;
        RECT  30.384 30.156 30.408 30.24 ;
    END
  END a_d[347]
  PIN a_d[348]
    DIRECTION INPUT ;
    USE SIGNAL ;
    PORT
      LAYER M5 ;
        RECT  30.432 30.156 30.456 30.24 ;
    END
  END a_d[348]
  PIN a_d[349]
    DIRECTION INPUT ;
    USE SIGNAL ;
    PORT
      LAYER M5 ;
        RECT  30.48 30.156 30.504 30.24 ;
    END
  END a_d[349]
  PIN a_d[34]
    DIRECTION INPUT ;
    USE SIGNAL ;
    PORT
      LAYER M5 ;
        RECT  15.36 30.156 15.384 30.24 ;
    END
  END a_d[34]
  PIN a_d[350]
    DIRECTION INPUT ;
    USE SIGNAL ;
    PORT
      LAYER M5 ;
        RECT  30.528 30.156 30.552 30.24 ;
    END
  END a_d[350]
  PIN a_d[351]
    DIRECTION INPUT ;
    USE SIGNAL ;
    PORT
      LAYER M5 ;
        RECT  30.576 30.156 30.6 30.24 ;
    END
  END a_d[351]
  PIN a_d[352]
    DIRECTION INPUT ;
    USE SIGNAL ;
    PORT
      LAYER M5 ;
        RECT  30.624 30.156 30.648 30.24 ;
    END
  END a_d[352]
  PIN a_d[353]
    DIRECTION INPUT ;
    USE SIGNAL ;
    PORT
      LAYER M5 ;
        RECT  30.672 30.156 30.696 30.24 ;
    END
  END a_d[353]
  PIN a_d[354]
    DIRECTION INPUT ;
    USE SIGNAL ;
    PORT
      LAYER M5 ;
        RECT  30.72 30.156 30.744 30.24 ;
    END
  END a_d[354]
  PIN a_d[355]
    DIRECTION INPUT ;
    USE SIGNAL ;
    PORT
      LAYER M5 ;
        RECT  30.768 30.156 30.792 30.24 ;
    END
  END a_d[355]
  PIN a_d[356]
    DIRECTION INPUT ;
    USE SIGNAL ;
    PORT
      LAYER M5 ;
        RECT  30.816 30.156 30.84 30.24 ;
    END
  END a_d[356]
  PIN a_d[357]
    DIRECTION INPUT ;
    USE SIGNAL ;
    PORT
      LAYER M5 ;
        RECT  30.864 30.156 30.888 30.24 ;
    END
  END a_d[357]
  PIN a_d[358]
    DIRECTION INPUT ;
    USE SIGNAL ;
    PORT
      LAYER M5 ;
        RECT  30.912 30.156 30.936 30.24 ;
    END
  END a_d[358]
  PIN a_d[359]
    DIRECTION INPUT ;
    USE SIGNAL ;
    PORT
      LAYER M5 ;
        RECT  30.96 30.156 30.984 30.24 ;
    END
  END a_d[359]
  PIN a_d[35]
    DIRECTION INPUT ;
    USE SIGNAL ;
    PORT
      LAYER M5 ;
        RECT  15.408 30.156 15.432 30.24 ;
    END
  END a_d[35]
  PIN a_d[360]
    DIRECTION INPUT ;
    USE SIGNAL ;
    PORT
      LAYER M5 ;
        RECT  31.008 30.156 31.032 30.24 ;
    END
  END a_d[360]
  PIN a_d[361]
    DIRECTION INPUT ;
    USE SIGNAL ;
    PORT
      LAYER M5 ;
        RECT  31.056 30.156 31.08 30.24 ;
    END
  END a_d[361]
  PIN a_d[362]
    DIRECTION INPUT ;
    USE SIGNAL ;
    PORT
      LAYER M5 ;
        RECT  31.104 30.156 31.128 30.24 ;
    END
  END a_d[362]
  PIN a_d[363]
    DIRECTION INPUT ;
    USE SIGNAL ;
    PORT
      LAYER M5 ;
        RECT  31.152 30.156 31.176 30.24 ;
    END
  END a_d[363]
  PIN a_d[364]
    DIRECTION INPUT ;
    USE SIGNAL ;
    PORT
      LAYER M5 ;
        RECT  31.2 30.156 31.224 30.24 ;
    END
  END a_d[364]
  PIN a_d[365]
    DIRECTION INPUT ;
    USE SIGNAL ;
    PORT
      LAYER M5 ;
        RECT  31.248 30.156 31.272 30.24 ;
    END
  END a_d[365]
  PIN a_d[366]
    DIRECTION INPUT ;
    USE SIGNAL ;
    PORT
      LAYER M5 ;
        RECT  31.296 30.156 31.32 30.24 ;
    END
  END a_d[366]
  PIN a_d[367]
    DIRECTION INPUT ;
    USE SIGNAL ;
    PORT
      LAYER M5 ;
        RECT  31.344 30.156 31.368 30.24 ;
    END
  END a_d[367]
  PIN a_d[368]
    DIRECTION INPUT ;
    USE SIGNAL ;
    PORT
      LAYER M5 ;
        RECT  31.392 30.156 31.416 30.24 ;
    END
  END a_d[368]
  PIN a_d[369]
    DIRECTION INPUT ;
    USE SIGNAL ;
    PORT
      LAYER M5 ;
        RECT  31.44 30.156 31.464 30.24 ;
    END
  END a_d[369]
  PIN a_d[36]
    DIRECTION INPUT ;
    USE SIGNAL ;
    PORT
      LAYER M5 ;
        RECT  15.456 30.156 15.48 30.24 ;
    END
  END a_d[36]
  PIN a_d[370]
    DIRECTION INPUT ;
    USE SIGNAL ;
    PORT
      LAYER M5 ;
        RECT  31.488 30.156 31.512 30.24 ;
    END
  END a_d[370]
  PIN a_d[371]
    DIRECTION INPUT ;
    USE SIGNAL ;
    PORT
      LAYER M5 ;
        RECT  31.536 30.156 31.56 30.24 ;
    END
  END a_d[371]
  PIN a_d[372]
    DIRECTION INPUT ;
    USE SIGNAL ;
    PORT
      LAYER M5 ;
        RECT  31.584 30.156 31.608 30.24 ;
    END
  END a_d[372]
  PIN a_d[373]
    DIRECTION INPUT ;
    USE SIGNAL ;
    PORT
      LAYER M5 ;
        RECT  31.632 30.156 31.656 30.24 ;
    END
  END a_d[373]
  PIN a_d[374]
    DIRECTION INPUT ;
    USE SIGNAL ;
    PORT
      LAYER M5 ;
        RECT  31.68 30.156 31.704 30.24 ;
    END
  END a_d[374]
  PIN a_d[375]
    DIRECTION INPUT ;
    USE SIGNAL ;
    PORT
      LAYER M5 ;
        RECT  31.728 30.156 31.752 30.24 ;
    END
  END a_d[375]
  PIN a_d[376]
    DIRECTION INPUT ;
    USE SIGNAL ;
    PORT
      LAYER M5 ;
        RECT  31.776 30.156 31.8 30.24 ;
    END
  END a_d[376]
  PIN a_d[377]
    DIRECTION INPUT ;
    USE SIGNAL ;
    PORT
      LAYER M5 ;
        RECT  31.824 30.156 31.848 30.24 ;
    END
  END a_d[377]
  PIN a_d[378]
    DIRECTION INPUT ;
    USE SIGNAL ;
    PORT
      LAYER M5 ;
        RECT  31.872 30.156 31.896 30.24 ;
    END
  END a_d[378]
  PIN a_d[379]
    DIRECTION INPUT ;
    USE SIGNAL ;
    PORT
      LAYER M5 ;
        RECT  31.92 30.156 31.944 30.24 ;
    END
  END a_d[379]
  PIN a_d[37]
    DIRECTION INPUT ;
    USE SIGNAL ;
    PORT
      LAYER M5 ;
        RECT  15.504 30.156 15.528 30.24 ;
    END
  END a_d[37]
  PIN a_d[380]
    DIRECTION INPUT ;
    USE SIGNAL ;
    PORT
      LAYER M5 ;
        RECT  31.968 30.156 31.992 30.24 ;
    END
  END a_d[380]
  PIN a_d[381]
    DIRECTION INPUT ;
    USE SIGNAL ;
    PORT
      LAYER M5 ;
        RECT  32.016 30.156 32.04 30.24 ;
    END
  END a_d[381]
  PIN a_d[382]
    DIRECTION INPUT ;
    USE SIGNAL ;
    PORT
      LAYER M5 ;
        RECT  32.064 30.156 32.088 30.24 ;
    END
  END a_d[382]
  PIN a_d[383]
    DIRECTION INPUT ;
    USE SIGNAL ;
    PORT
      LAYER M5 ;
        RECT  32.112 30.156 32.136 30.24 ;
    END
  END a_d[383]
  PIN a_d[384]
    DIRECTION INPUT ;
    USE SIGNAL ;
    PORT
      LAYER M5 ;
        RECT  32.16 30.156 32.184 30.24 ;
    END
  END a_d[384]
  PIN a_d[385]
    DIRECTION INPUT ;
    USE SIGNAL ;
    PORT
      LAYER M5 ;
        RECT  32.208 30.156 32.232 30.24 ;
    END
  END a_d[385]
  PIN a_d[386]
    DIRECTION INPUT ;
    USE SIGNAL ;
    PORT
      LAYER M5 ;
        RECT  32.256 30.156 32.28 30.24 ;
    END
  END a_d[386]
  PIN a_d[387]
    DIRECTION INPUT ;
    USE SIGNAL ;
    PORT
      LAYER M5 ;
        RECT  32.304 30.156 32.328 30.24 ;
    END
  END a_d[387]
  PIN a_d[388]
    DIRECTION INPUT ;
    USE SIGNAL ;
    PORT
      LAYER M5 ;
        RECT  32.352 30.156 32.376 30.24 ;
    END
  END a_d[388]
  PIN a_d[389]
    DIRECTION INPUT ;
    USE SIGNAL ;
    PORT
      LAYER M5 ;
        RECT  32.4 30.156 32.424 30.24 ;
    END
  END a_d[389]
  PIN a_d[38]
    DIRECTION INPUT ;
    USE SIGNAL ;
    PORT
      LAYER M5 ;
        RECT  15.552 30.156 15.576 30.24 ;
    END
  END a_d[38]
  PIN a_d[390]
    DIRECTION INPUT ;
    USE SIGNAL ;
    PORT
      LAYER M5 ;
        RECT  32.448 30.156 32.472 30.24 ;
    END
  END a_d[390]
  PIN a_d[391]
    DIRECTION INPUT ;
    USE SIGNAL ;
    PORT
      LAYER M5 ;
        RECT  32.496 30.156 32.52 30.24 ;
    END
  END a_d[391]
  PIN a_d[392]
    DIRECTION INPUT ;
    USE SIGNAL ;
    PORT
      LAYER M5 ;
        RECT  32.544 30.156 32.568 30.24 ;
    END
  END a_d[392]
  PIN a_d[393]
    DIRECTION INPUT ;
    USE SIGNAL ;
    PORT
      LAYER M5 ;
        RECT  32.592 30.156 32.616 30.24 ;
    END
  END a_d[393]
  PIN a_d[394]
    DIRECTION INPUT ;
    USE SIGNAL ;
    PORT
      LAYER M5 ;
        RECT  32.64 30.156 32.664 30.24 ;
    END
  END a_d[394]
  PIN a_d[395]
    DIRECTION INPUT ;
    USE SIGNAL ;
    PORT
      LAYER M5 ;
        RECT  32.688 30.156 32.712 30.24 ;
    END
  END a_d[395]
  PIN a_d[396]
    DIRECTION INPUT ;
    USE SIGNAL ;
    PORT
      LAYER M5 ;
        RECT  32.736 30.156 32.76 30.24 ;
    END
  END a_d[396]
  PIN a_d[397]
    DIRECTION INPUT ;
    USE SIGNAL ;
    PORT
      LAYER M5 ;
        RECT  32.784 30.156 32.808 30.24 ;
    END
  END a_d[397]
  PIN a_d[398]
    DIRECTION INPUT ;
    USE SIGNAL ;
    PORT
      LAYER M5 ;
        RECT  32.832 30.156 32.856 30.24 ;
    END
  END a_d[398]
  PIN a_d[399]
    DIRECTION INPUT ;
    USE SIGNAL ;
    PORT
      LAYER M5 ;
        RECT  32.88 30.156 32.904 30.24 ;
    END
  END a_d[399]
  PIN a_d[39]
    DIRECTION INPUT ;
    USE SIGNAL ;
    PORT
      LAYER M5 ;
        RECT  15.6 30.156 15.624 30.24 ;
    END
  END a_d[39]
  PIN a_d[3]
    DIRECTION INPUT ;
    USE SIGNAL ;
    PORT
      LAYER M5 ;
        RECT  13.872 30.156 13.896 30.24 ;
    END
  END a_d[3]
  PIN a_d[400]
    DIRECTION INPUT ;
    USE SIGNAL ;
    PORT
      LAYER M5 ;
        RECT  32.928 30.156 32.952 30.24 ;
    END
  END a_d[400]
  PIN a_d[401]
    DIRECTION INPUT ;
    USE SIGNAL ;
    PORT
      LAYER M5 ;
        RECT  32.976 30.156 33 30.24 ;
    END
  END a_d[401]
  PIN a_d[402]
    DIRECTION INPUT ;
    USE SIGNAL ;
    PORT
      LAYER M5 ;
        RECT  33.024 30.156 33.048 30.24 ;
    END
  END a_d[402]
  PIN a_d[403]
    DIRECTION INPUT ;
    USE SIGNAL ;
    PORT
      LAYER M5 ;
        RECT  33.072 30.156 33.096 30.24 ;
    END
  END a_d[403]
  PIN a_d[404]
    DIRECTION INPUT ;
    USE SIGNAL ;
    PORT
      LAYER M5 ;
        RECT  33.12 30.156 33.144 30.24 ;
    END
  END a_d[404]
  PIN a_d[405]
    DIRECTION INPUT ;
    USE SIGNAL ;
    PORT
      LAYER M5 ;
        RECT  33.168 30.156 33.192 30.24 ;
    END
  END a_d[405]
  PIN a_d[406]
    DIRECTION INPUT ;
    USE SIGNAL ;
    PORT
      LAYER M5 ;
        RECT  33.216 30.156 33.24 30.24 ;
    END
  END a_d[406]
  PIN a_d[407]
    DIRECTION INPUT ;
    USE SIGNAL ;
    PORT
      LAYER M5 ;
        RECT  33.264 30.156 33.288 30.24 ;
    END
  END a_d[407]
  PIN a_d[408]
    DIRECTION INPUT ;
    USE SIGNAL ;
    PORT
      LAYER M5 ;
        RECT  33.312 30.156 33.336 30.24 ;
    END
  END a_d[408]
  PIN a_d[409]
    DIRECTION INPUT ;
    USE SIGNAL ;
    PORT
      LAYER M5 ;
        RECT  33.36 30.156 33.384 30.24 ;
    END
  END a_d[409]
  PIN a_d[40]
    DIRECTION INPUT ;
    USE SIGNAL ;
    PORT
      LAYER M5 ;
        RECT  15.648 30.156 15.672 30.24 ;
    END
  END a_d[40]
  PIN a_d[410]
    DIRECTION INPUT ;
    USE SIGNAL ;
    PORT
      LAYER M5 ;
        RECT  33.408 30.156 33.432 30.24 ;
    END
  END a_d[410]
  PIN a_d[411]
    DIRECTION INPUT ;
    USE SIGNAL ;
    PORT
      LAYER M5 ;
        RECT  33.456 30.156 33.48 30.24 ;
    END
  END a_d[411]
  PIN a_d[412]
    DIRECTION INPUT ;
    USE SIGNAL ;
    PORT
      LAYER M5 ;
        RECT  33.504 30.156 33.528 30.24 ;
    END
  END a_d[412]
  PIN a_d[413]
    DIRECTION INPUT ;
    USE SIGNAL ;
    PORT
      LAYER M5 ;
        RECT  33.552 30.156 33.576 30.24 ;
    END
  END a_d[413]
  PIN a_d[414]
    DIRECTION INPUT ;
    USE SIGNAL ;
    PORT
      LAYER M5 ;
        RECT  33.6 30.156 33.624 30.24 ;
    END
  END a_d[414]
  PIN a_d[415]
    DIRECTION INPUT ;
    USE SIGNAL ;
    PORT
      LAYER M5 ;
        RECT  33.648 30.156 33.672 30.24 ;
    END
  END a_d[415]
  PIN a_d[416]
    DIRECTION INPUT ;
    USE SIGNAL ;
    PORT
      LAYER M5 ;
        RECT  33.696 30.156 33.72 30.24 ;
    END
  END a_d[416]
  PIN a_d[417]
    DIRECTION INPUT ;
    USE SIGNAL ;
    PORT
      LAYER M5 ;
        RECT  33.744 30.156 33.768 30.24 ;
    END
  END a_d[417]
  PIN a_d[418]
    DIRECTION INPUT ;
    USE SIGNAL ;
    PORT
      LAYER M5 ;
        RECT  33.792 30.156 33.816 30.24 ;
    END
  END a_d[418]
  PIN a_d[419]
    DIRECTION INPUT ;
    USE SIGNAL ;
    PORT
      LAYER M5 ;
        RECT  33.84 30.156 33.864 30.24 ;
    END
  END a_d[419]
  PIN a_d[41]
    DIRECTION INPUT ;
    USE SIGNAL ;
    PORT
      LAYER M5 ;
        RECT  15.696 30.156 15.72 30.24 ;
    END
  END a_d[41]
  PIN a_d[420]
    DIRECTION INPUT ;
    USE SIGNAL ;
    PORT
      LAYER M5 ;
        RECT  33.888 30.156 33.912 30.24 ;
    END
  END a_d[420]
  PIN a_d[421]
    DIRECTION INPUT ;
    USE SIGNAL ;
    PORT
      LAYER M5 ;
        RECT  33.936 30.156 33.96 30.24 ;
    END
  END a_d[421]
  PIN a_d[422]
    DIRECTION INPUT ;
    USE SIGNAL ;
    PORT
      LAYER M5 ;
        RECT  33.984 30.156 34.008 30.24 ;
    END
  END a_d[422]
  PIN a_d[423]
    DIRECTION INPUT ;
    USE SIGNAL ;
    PORT
      LAYER M5 ;
        RECT  34.032 30.156 34.056 30.24 ;
    END
  END a_d[423]
  PIN a_d[424]
    DIRECTION INPUT ;
    USE SIGNAL ;
    PORT
      LAYER M5 ;
        RECT  34.08 30.156 34.104 30.24 ;
    END
  END a_d[424]
  PIN a_d[425]
    DIRECTION INPUT ;
    USE SIGNAL ;
    PORT
      LAYER M5 ;
        RECT  34.128 30.156 34.152 30.24 ;
    END
  END a_d[425]
  PIN a_d[426]
    DIRECTION INPUT ;
    USE SIGNAL ;
    PORT
      LAYER M5 ;
        RECT  34.176 30.156 34.2 30.24 ;
    END
  END a_d[426]
  PIN a_d[427]
    DIRECTION INPUT ;
    USE SIGNAL ;
    PORT
      LAYER M5 ;
        RECT  34.224 30.156 34.248 30.24 ;
    END
  END a_d[427]
  PIN a_d[428]
    DIRECTION INPUT ;
    USE SIGNAL ;
    PORT
      LAYER M5 ;
        RECT  34.272 30.156 34.296 30.24 ;
    END
  END a_d[428]
  PIN a_d[429]
    DIRECTION INPUT ;
    USE SIGNAL ;
    PORT
      LAYER M5 ;
        RECT  34.32 30.156 34.344 30.24 ;
    END
  END a_d[429]
  PIN a_d[42]
    DIRECTION INPUT ;
    USE SIGNAL ;
    PORT
      LAYER M5 ;
        RECT  15.744 30.156 15.768 30.24 ;
    END
  END a_d[42]
  PIN a_d[430]
    DIRECTION INPUT ;
    USE SIGNAL ;
    PORT
      LAYER M5 ;
        RECT  34.368 30.156 34.392 30.24 ;
    END
  END a_d[430]
  PIN a_d[431]
    DIRECTION INPUT ;
    USE SIGNAL ;
    PORT
      LAYER M5 ;
        RECT  34.416 30.156 34.44 30.24 ;
    END
  END a_d[431]
  PIN a_d[432]
    DIRECTION INPUT ;
    USE SIGNAL ;
    PORT
      LAYER M5 ;
        RECT  34.464 30.156 34.488 30.24 ;
    END
  END a_d[432]
  PIN a_d[433]
    DIRECTION INPUT ;
    USE SIGNAL ;
    PORT
      LAYER M5 ;
        RECT  34.512 30.156 34.536 30.24 ;
    END
  END a_d[433]
  PIN a_d[434]
    DIRECTION INPUT ;
    USE SIGNAL ;
    PORT
      LAYER M5 ;
        RECT  34.56 30.156 34.584 30.24 ;
    END
  END a_d[434]
  PIN a_d[435]
    DIRECTION INPUT ;
    USE SIGNAL ;
    PORT
      LAYER M5 ;
        RECT  34.608 30.156 34.632 30.24 ;
    END
  END a_d[435]
  PIN a_d[436]
    DIRECTION INPUT ;
    USE SIGNAL ;
    PORT
      LAYER M5 ;
        RECT  34.656 30.156 34.68 30.24 ;
    END
  END a_d[436]
  PIN a_d[437]
    DIRECTION INPUT ;
    USE SIGNAL ;
    PORT
      LAYER M5 ;
        RECT  34.704 30.156 34.728 30.24 ;
    END
  END a_d[437]
  PIN a_d[438]
    DIRECTION INPUT ;
    USE SIGNAL ;
    PORT
      LAYER M5 ;
        RECT  34.752 30.156 34.776 30.24 ;
    END
  END a_d[438]
  PIN a_d[439]
    DIRECTION INPUT ;
    USE SIGNAL ;
    PORT
      LAYER M5 ;
        RECT  34.8 30.156 34.824 30.24 ;
    END
  END a_d[439]
  PIN a_d[43]
    DIRECTION INPUT ;
    USE SIGNAL ;
    PORT
      LAYER M5 ;
        RECT  15.792 30.156 15.816 30.24 ;
    END
  END a_d[43]
  PIN a_d[440]
    DIRECTION INPUT ;
    USE SIGNAL ;
    PORT
      LAYER M5 ;
        RECT  34.848 30.156 34.872 30.24 ;
    END
  END a_d[440]
  PIN a_d[441]
    DIRECTION INPUT ;
    USE SIGNAL ;
    PORT
      LAYER M5 ;
        RECT  34.896 30.156 34.92 30.24 ;
    END
  END a_d[441]
  PIN a_d[442]
    DIRECTION INPUT ;
    USE SIGNAL ;
    PORT
      LAYER M5 ;
        RECT  34.944 30.156 34.968 30.24 ;
    END
  END a_d[442]
  PIN a_d[443]
    DIRECTION INPUT ;
    USE SIGNAL ;
    PORT
      LAYER M5 ;
        RECT  34.992 30.156 35.016 30.24 ;
    END
  END a_d[443]
  PIN a_d[444]
    DIRECTION INPUT ;
    USE SIGNAL ;
    PORT
      LAYER M5 ;
        RECT  35.04 30.156 35.064 30.24 ;
    END
  END a_d[444]
  PIN a_d[445]
    DIRECTION INPUT ;
    USE SIGNAL ;
    PORT
      LAYER M5 ;
        RECT  35.088 30.156 35.112 30.24 ;
    END
  END a_d[445]
  PIN a_d[446]
    DIRECTION INPUT ;
    USE SIGNAL ;
    PORT
      LAYER M5 ;
        RECT  35.136 30.156 35.16 30.24 ;
    END
  END a_d[446]
  PIN a_d[447]
    DIRECTION INPUT ;
    USE SIGNAL ;
    PORT
      LAYER M5 ;
        RECT  35.184 30.156 35.208 30.24 ;
    END
  END a_d[447]
  PIN a_d[448]
    DIRECTION INPUT ;
    USE SIGNAL ;
    PORT
      LAYER M5 ;
        RECT  35.232 30.156 35.256 30.24 ;
    END
  END a_d[448]
  PIN a_d[449]
    DIRECTION INPUT ;
    USE SIGNAL ;
    PORT
      LAYER M5 ;
        RECT  35.28 30.156 35.304 30.24 ;
    END
  END a_d[449]
  PIN a_d[44]
    DIRECTION INPUT ;
    USE SIGNAL ;
    PORT
      LAYER M5 ;
        RECT  15.84 30.156 15.864 30.24 ;
    END
  END a_d[44]
  PIN a_d[450]
    DIRECTION INPUT ;
    USE SIGNAL ;
    PORT
      LAYER M5 ;
        RECT  35.328 30.156 35.352 30.24 ;
    END
  END a_d[450]
  PIN a_d[451]
    DIRECTION INPUT ;
    USE SIGNAL ;
    PORT
      LAYER M5 ;
        RECT  35.376 30.156 35.4 30.24 ;
    END
  END a_d[451]
  PIN a_d[452]
    DIRECTION INPUT ;
    USE SIGNAL ;
    PORT
      LAYER M5 ;
        RECT  35.424 30.156 35.448 30.24 ;
    END
  END a_d[452]
  PIN a_d[453]
    DIRECTION INPUT ;
    USE SIGNAL ;
    PORT
      LAYER M5 ;
        RECT  35.472 30.156 35.496 30.24 ;
    END
  END a_d[453]
  PIN a_d[454]
    DIRECTION INPUT ;
    USE SIGNAL ;
    PORT
      LAYER M5 ;
        RECT  35.52 30.156 35.544 30.24 ;
    END
  END a_d[454]
  PIN a_d[455]
    DIRECTION INPUT ;
    USE SIGNAL ;
    PORT
      LAYER M5 ;
        RECT  35.568 30.156 35.592 30.24 ;
    END
  END a_d[455]
  PIN a_d[456]
    DIRECTION INPUT ;
    USE SIGNAL ;
    PORT
      LAYER M5 ;
        RECT  35.616 30.156 35.64 30.24 ;
    END
  END a_d[456]
  PIN a_d[457]
    DIRECTION INPUT ;
    USE SIGNAL ;
    PORT
      LAYER M5 ;
        RECT  35.664 30.156 35.688 30.24 ;
    END
  END a_d[457]
  PIN a_d[458]
    DIRECTION INPUT ;
    USE SIGNAL ;
    PORT
      LAYER M5 ;
        RECT  35.712 30.156 35.736 30.24 ;
    END
  END a_d[458]
  PIN a_d[459]
    DIRECTION INPUT ;
    USE SIGNAL ;
    PORT
      LAYER M5 ;
        RECT  35.76 30.156 35.784 30.24 ;
    END
  END a_d[459]
  PIN a_d[45]
    DIRECTION INPUT ;
    USE SIGNAL ;
    PORT
      LAYER M5 ;
        RECT  15.888 30.156 15.912 30.24 ;
    END
  END a_d[45]
  PIN a_d[460]
    DIRECTION INPUT ;
    USE SIGNAL ;
    PORT
      LAYER M5 ;
        RECT  35.808 30.156 35.832 30.24 ;
    END
  END a_d[460]
  PIN a_d[461]
    DIRECTION INPUT ;
    USE SIGNAL ;
    PORT
      LAYER M5 ;
        RECT  35.856 30.156 35.88 30.24 ;
    END
  END a_d[461]
  PIN a_d[462]
    DIRECTION INPUT ;
    USE SIGNAL ;
    PORT
      LAYER M5 ;
        RECT  35.904 30.156 35.928 30.24 ;
    END
  END a_d[462]
  PIN a_d[463]
    DIRECTION INPUT ;
    USE SIGNAL ;
    PORT
      LAYER M5 ;
        RECT  35.952 30.156 35.976 30.24 ;
    END
  END a_d[463]
  PIN a_d[464]
    DIRECTION INPUT ;
    USE SIGNAL ;
    PORT
      LAYER M5 ;
        RECT  36 30.156 36.024 30.24 ;
    END
  END a_d[464]
  PIN a_d[465]
    DIRECTION INPUT ;
    USE SIGNAL ;
    PORT
      LAYER M5 ;
        RECT  36.048 30.156 36.072 30.24 ;
    END
  END a_d[465]
  PIN a_d[466]
    DIRECTION INPUT ;
    USE SIGNAL ;
    PORT
      LAYER M5 ;
        RECT  36.096 30.156 36.12 30.24 ;
    END
  END a_d[466]
  PIN a_d[467]
    DIRECTION INPUT ;
    USE SIGNAL ;
    PORT
      LAYER M5 ;
        RECT  36.144 30.156 36.168 30.24 ;
    END
  END a_d[467]
  PIN a_d[468]
    DIRECTION INPUT ;
    USE SIGNAL ;
    PORT
      LAYER M5 ;
        RECT  36.192 30.156 36.216 30.24 ;
    END
  END a_d[468]
  PIN a_d[469]
    DIRECTION INPUT ;
    USE SIGNAL ;
    PORT
      LAYER M5 ;
        RECT  36.24 30.156 36.264 30.24 ;
    END
  END a_d[469]
  PIN a_d[46]
    DIRECTION INPUT ;
    USE SIGNAL ;
    PORT
      LAYER M5 ;
        RECT  15.936 30.156 15.96 30.24 ;
    END
  END a_d[46]
  PIN a_d[470]
    DIRECTION INPUT ;
    USE SIGNAL ;
    PORT
      LAYER M5 ;
        RECT  36.288 30.156 36.312 30.24 ;
    END
  END a_d[470]
  PIN a_d[471]
    DIRECTION INPUT ;
    USE SIGNAL ;
    PORT
      LAYER M5 ;
        RECT  36.336 30.156 36.36 30.24 ;
    END
  END a_d[471]
  PIN a_d[472]
    DIRECTION INPUT ;
    USE SIGNAL ;
    PORT
      LAYER M5 ;
        RECT  36.384 30.156 36.408 30.24 ;
    END
  END a_d[472]
  PIN a_d[473]
    DIRECTION INPUT ;
    USE SIGNAL ;
    PORT
      LAYER M5 ;
        RECT  36.432 30.156 36.456 30.24 ;
    END
  END a_d[473]
  PIN a_d[474]
    DIRECTION INPUT ;
    USE SIGNAL ;
    PORT
      LAYER M5 ;
        RECT  36.48 30.156 36.504 30.24 ;
    END
  END a_d[474]
  PIN a_d[475]
    DIRECTION INPUT ;
    USE SIGNAL ;
    PORT
      LAYER M5 ;
        RECT  36.528 30.156 36.552 30.24 ;
    END
  END a_d[475]
  PIN a_d[476]
    DIRECTION INPUT ;
    USE SIGNAL ;
    PORT
      LAYER M5 ;
        RECT  36.576 30.156 36.6 30.24 ;
    END
  END a_d[476]
  PIN a_d[477]
    DIRECTION INPUT ;
    USE SIGNAL ;
    PORT
      LAYER M5 ;
        RECT  36.624 30.156 36.648 30.24 ;
    END
  END a_d[477]
  PIN a_d[478]
    DIRECTION INPUT ;
    USE SIGNAL ;
    PORT
      LAYER M5 ;
        RECT  36.672 30.156 36.696 30.24 ;
    END
  END a_d[478]
  PIN a_d[479]
    DIRECTION INPUT ;
    USE SIGNAL ;
    PORT
      LAYER M5 ;
        RECT  36.72 30.156 36.744 30.24 ;
    END
  END a_d[479]
  PIN a_d[47]
    DIRECTION INPUT ;
    USE SIGNAL ;
    PORT
      LAYER M5 ;
        RECT  15.984 30.156 16.008 30.24 ;
    END
  END a_d[47]
  PIN a_d[480]
    DIRECTION INPUT ;
    USE SIGNAL ;
    PORT
      LAYER M5 ;
        RECT  36.768 30.156 36.792 30.24 ;
    END
  END a_d[480]
  PIN a_d[481]
    DIRECTION INPUT ;
    USE SIGNAL ;
    PORT
      LAYER M5 ;
        RECT  36.816 30.156 36.84 30.24 ;
    END
  END a_d[481]
  PIN a_d[482]
    DIRECTION INPUT ;
    USE SIGNAL ;
    PORT
      LAYER M5 ;
        RECT  36.864 30.156 36.888 30.24 ;
    END
  END a_d[482]
  PIN a_d[483]
    DIRECTION INPUT ;
    USE SIGNAL ;
    PORT
      LAYER M5 ;
        RECT  36.912 30.156 36.936 30.24 ;
    END
  END a_d[483]
  PIN a_d[484]
    DIRECTION INPUT ;
    USE SIGNAL ;
    PORT
      LAYER M5 ;
        RECT  36.96 30.156 36.984 30.24 ;
    END
  END a_d[484]
  PIN a_d[485]
    DIRECTION INPUT ;
    USE SIGNAL ;
    PORT
      LAYER M5 ;
        RECT  37.008 30.156 37.032 30.24 ;
    END
  END a_d[485]
  PIN a_d[486]
    DIRECTION INPUT ;
    USE SIGNAL ;
    PORT
      LAYER M5 ;
        RECT  37.056 30.156 37.08 30.24 ;
    END
  END a_d[486]
  PIN a_d[487]
    DIRECTION INPUT ;
    USE SIGNAL ;
    PORT
      LAYER M5 ;
        RECT  37.104 30.156 37.128 30.24 ;
    END
  END a_d[487]
  PIN a_d[488]
    DIRECTION INPUT ;
    USE SIGNAL ;
    PORT
      LAYER M5 ;
        RECT  37.152 30.156 37.176 30.24 ;
    END
  END a_d[488]
  PIN a_d[489]
    DIRECTION INPUT ;
    USE SIGNAL ;
    PORT
      LAYER M5 ;
        RECT  37.2 30.156 37.224 30.24 ;
    END
  END a_d[489]
  PIN a_d[48]
    DIRECTION INPUT ;
    USE SIGNAL ;
    PORT
      LAYER M5 ;
        RECT  16.032 30.156 16.056 30.24 ;
    END
  END a_d[48]
  PIN a_d[490]
    DIRECTION INPUT ;
    USE SIGNAL ;
    PORT
      LAYER M5 ;
        RECT  37.248 30.156 37.272 30.24 ;
    END
  END a_d[490]
  PIN a_d[491]
    DIRECTION INPUT ;
    USE SIGNAL ;
    PORT
      LAYER M5 ;
        RECT  37.296 30.156 37.32 30.24 ;
    END
  END a_d[491]
  PIN a_d[492]
    DIRECTION INPUT ;
    USE SIGNAL ;
    PORT
      LAYER M5 ;
        RECT  37.344 30.156 37.368 30.24 ;
    END
  END a_d[492]
  PIN a_d[493]
    DIRECTION INPUT ;
    USE SIGNAL ;
    PORT
      LAYER M5 ;
        RECT  37.392 30.156 37.416 30.24 ;
    END
  END a_d[493]
  PIN a_d[494]
    DIRECTION INPUT ;
    USE SIGNAL ;
    PORT
      LAYER M5 ;
        RECT  37.44 30.156 37.464 30.24 ;
    END
  END a_d[494]
  PIN a_d[495]
    DIRECTION INPUT ;
    USE SIGNAL ;
    PORT
      LAYER M5 ;
        RECT  37.488 30.156 37.512 30.24 ;
    END
  END a_d[495]
  PIN a_d[496]
    DIRECTION INPUT ;
    USE SIGNAL ;
    PORT
      LAYER M5 ;
        RECT  37.536 30.156 37.56 30.24 ;
    END
  END a_d[496]
  PIN a_d[497]
    DIRECTION INPUT ;
    USE SIGNAL ;
    PORT
      LAYER M5 ;
        RECT  37.584 30.156 37.608 30.24 ;
    END
  END a_d[497]
  PIN a_d[498]
    DIRECTION INPUT ;
    USE SIGNAL ;
    PORT
      LAYER M5 ;
        RECT  37.632 30.156 37.656 30.24 ;
    END
  END a_d[498]
  PIN a_d[499]
    DIRECTION INPUT ;
    USE SIGNAL ;
    PORT
      LAYER M5 ;
        RECT  37.68 30.156 37.704 30.24 ;
    END
  END a_d[499]
  PIN a_d[49]
    DIRECTION INPUT ;
    USE SIGNAL ;
    PORT
      LAYER M5 ;
        RECT  16.08 30.156 16.104 30.24 ;
    END
  END a_d[49]
  PIN a_d[4]
    DIRECTION INPUT ;
    USE SIGNAL ;
    PORT
      LAYER M5 ;
        RECT  13.92 30.156 13.944 30.24 ;
    END
  END a_d[4]
  PIN a_d[500]
    DIRECTION INPUT ;
    USE SIGNAL ;
    PORT
      LAYER M5 ;
        RECT  37.728 30.156 37.752 30.24 ;
    END
  END a_d[500]
  PIN a_d[501]
    DIRECTION INPUT ;
    USE SIGNAL ;
    PORT
      LAYER M5 ;
        RECT  37.776 30.156 37.8 30.24 ;
    END
  END a_d[501]
  PIN a_d[502]
    DIRECTION INPUT ;
    USE SIGNAL ;
    PORT
      LAYER M5 ;
        RECT  37.824 30.156 37.848 30.24 ;
    END
  END a_d[502]
  PIN a_d[503]
    DIRECTION INPUT ;
    USE SIGNAL ;
    PORT
      LAYER M5 ;
        RECT  37.872 30.156 37.896 30.24 ;
    END
  END a_d[503]
  PIN a_d[504]
    DIRECTION INPUT ;
    USE SIGNAL ;
    PORT
      LAYER M5 ;
        RECT  37.92 30.156 37.944 30.24 ;
    END
  END a_d[504]
  PIN a_d[505]
    DIRECTION INPUT ;
    USE SIGNAL ;
    PORT
      LAYER M5 ;
        RECT  37.968 30.156 37.992 30.24 ;
    END
  END a_d[505]
  PIN a_d[506]
    DIRECTION INPUT ;
    USE SIGNAL ;
    PORT
      LAYER M5 ;
        RECT  38.016 30.156 38.04 30.24 ;
    END
  END a_d[506]
  PIN a_d[507]
    DIRECTION INPUT ;
    USE SIGNAL ;
    PORT
      LAYER M5 ;
        RECT  38.064 30.156 38.088 30.24 ;
    END
  END a_d[507]
  PIN a_d[508]
    DIRECTION INPUT ;
    USE SIGNAL ;
    PORT
      LAYER M5 ;
        RECT  38.112 30.156 38.136 30.24 ;
    END
  END a_d[508]
  PIN a_d[509]
    DIRECTION INPUT ;
    USE SIGNAL ;
    PORT
      LAYER M5 ;
        RECT  38.16 30.156 38.184 30.24 ;
    END
  END a_d[509]
  PIN a_d[50]
    DIRECTION INPUT ;
    USE SIGNAL ;
    PORT
      LAYER M5 ;
        RECT  16.128 30.156 16.152 30.24 ;
    END
  END a_d[50]
  PIN a_d[510]
    DIRECTION INPUT ;
    USE SIGNAL ;
    PORT
      LAYER M5 ;
        RECT  38.208 30.156 38.232 30.24 ;
    END
  END a_d[510]
  PIN a_d[511]
    DIRECTION INPUT ;
    USE SIGNAL ;
    PORT
      LAYER M5 ;
        RECT  38.256 30.156 38.28 30.24 ;
    END
  END a_d[511]
  PIN a_d[51]
    DIRECTION INPUT ;
    USE SIGNAL ;
    PORT
      LAYER M5 ;
        RECT  16.176 30.156 16.2 30.24 ;
    END
  END a_d[51]
  PIN a_d[52]
    DIRECTION INPUT ;
    USE SIGNAL ;
    PORT
      LAYER M5 ;
        RECT  16.224 30.156 16.248 30.24 ;
    END
  END a_d[52]
  PIN a_d[53]
    DIRECTION INPUT ;
    USE SIGNAL ;
    PORT
      LAYER M5 ;
        RECT  16.272 30.156 16.296 30.24 ;
    END
  END a_d[53]
  PIN a_d[54]
    DIRECTION INPUT ;
    USE SIGNAL ;
    PORT
      LAYER M5 ;
        RECT  16.32 30.156 16.344 30.24 ;
    END
  END a_d[54]
  PIN a_d[55]
    DIRECTION INPUT ;
    USE SIGNAL ;
    PORT
      LAYER M5 ;
        RECT  16.368 30.156 16.392 30.24 ;
    END
  END a_d[55]
  PIN a_d[56]
    DIRECTION INPUT ;
    USE SIGNAL ;
    PORT
      LAYER M5 ;
        RECT  16.416 30.156 16.44 30.24 ;
    END
  END a_d[56]
  PIN a_d[57]
    DIRECTION INPUT ;
    USE SIGNAL ;
    PORT
      LAYER M5 ;
        RECT  16.464 30.156 16.488 30.24 ;
    END
  END a_d[57]
  PIN a_d[58]
    DIRECTION INPUT ;
    USE SIGNAL ;
    PORT
      LAYER M5 ;
        RECT  16.512 30.156 16.536 30.24 ;
    END
  END a_d[58]
  PIN a_d[59]
    DIRECTION INPUT ;
    USE SIGNAL ;
    PORT
      LAYER M5 ;
        RECT  16.56 30.156 16.584 30.24 ;
    END
  END a_d[59]
  PIN a_d[5]
    DIRECTION INPUT ;
    USE SIGNAL ;
    PORT
      LAYER M5 ;
        RECT  13.968 30.156 13.992 30.24 ;
    END
  END a_d[5]
  PIN a_d[60]
    DIRECTION INPUT ;
    USE SIGNAL ;
    PORT
      LAYER M5 ;
        RECT  16.608 30.156 16.632 30.24 ;
    END
  END a_d[60]
  PIN a_d[61]
    DIRECTION INPUT ;
    USE SIGNAL ;
    PORT
      LAYER M5 ;
        RECT  16.656 30.156 16.68 30.24 ;
    END
  END a_d[61]
  PIN a_d[62]
    DIRECTION INPUT ;
    USE SIGNAL ;
    PORT
      LAYER M5 ;
        RECT  16.704 30.156 16.728 30.24 ;
    END
  END a_d[62]
  PIN a_d[63]
    DIRECTION INPUT ;
    USE SIGNAL ;
    PORT
      LAYER M5 ;
        RECT  16.752 30.156 16.776 30.24 ;
    END
  END a_d[63]
  PIN a_d[64]
    DIRECTION INPUT ;
    USE SIGNAL ;
    PORT
      LAYER M5 ;
        RECT  16.8 30.156 16.824 30.24 ;
    END
  END a_d[64]
  PIN a_d[65]
    DIRECTION INPUT ;
    USE SIGNAL ;
    PORT
      LAYER M5 ;
        RECT  16.848 30.156 16.872 30.24 ;
    END
  END a_d[65]
  PIN a_d[66]
    DIRECTION INPUT ;
    USE SIGNAL ;
    PORT
      LAYER M5 ;
        RECT  16.896 30.156 16.92 30.24 ;
    END
  END a_d[66]
  PIN a_d[67]
    DIRECTION INPUT ;
    USE SIGNAL ;
    PORT
      LAYER M5 ;
        RECT  16.944 30.156 16.968 30.24 ;
    END
  END a_d[67]
  PIN a_d[68]
    DIRECTION INPUT ;
    USE SIGNAL ;
    PORT
      LAYER M5 ;
        RECT  16.992 30.156 17.016 30.24 ;
    END
  END a_d[68]
  PIN a_d[69]
    DIRECTION INPUT ;
    USE SIGNAL ;
    PORT
      LAYER M5 ;
        RECT  17.04 30.156 17.064 30.24 ;
    END
  END a_d[69]
  PIN a_d[6]
    DIRECTION INPUT ;
    USE SIGNAL ;
    PORT
      LAYER M5 ;
        RECT  14.016 30.156 14.04 30.24 ;
    END
  END a_d[6]
  PIN a_d[70]
    DIRECTION INPUT ;
    USE SIGNAL ;
    PORT
      LAYER M5 ;
        RECT  17.088 30.156 17.112 30.24 ;
    END
  END a_d[70]
  PIN a_d[71]
    DIRECTION INPUT ;
    USE SIGNAL ;
    PORT
      LAYER M5 ;
        RECT  17.136 30.156 17.16 30.24 ;
    END
  END a_d[71]
  PIN a_d[72]
    DIRECTION INPUT ;
    USE SIGNAL ;
    PORT
      LAYER M5 ;
        RECT  17.184 30.156 17.208 30.24 ;
    END
  END a_d[72]
  PIN a_d[73]
    DIRECTION INPUT ;
    USE SIGNAL ;
    PORT
      LAYER M5 ;
        RECT  17.232 30.156 17.256 30.24 ;
    END
  END a_d[73]
  PIN a_d[74]
    DIRECTION INPUT ;
    USE SIGNAL ;
    PORT
      LAYER M5 ;
        RECT  17.28 30.156 17.304 30.24 ;
    END
  END a_d[74]
  PIN a_d[75]
    DIRECTION INPUT ;
    USE SIGNAL ;
    PORT
      LAYER M5 ;
        RECT  17.328 30.156 17.352 30.24 ;
    END
  END a_d[75]
  PIN a_d[76]
    DIRECTION INPUT ;
    USE SIGNAL ;
    PORT
      LAYER M5 ;
        RECT  17.376 30.156 17.4 30.24 ;
    END
  END a_d[76]
  PIN a_d[77]
    DIRECTION INPUT ;
    USE SIGNAL ;
    PORT
      LAYER M5 ;
        RECT  17.424 30.156 17.448 30.24 ;
    END
  END a_d[77]
  PIN a_d[78]
    DIRECTION INPUT ;
    USE SIGNAL ;
    PORT
      LAYER M5 ;
        RECT  17.472 30.156 17.496 30.24 ;
    END
  END a_d[78]
  PIN a_d[79]
    DIRECTION INPUT ;
    USE SIGNAL ;
    PORT
      LAYER M5 ;
        RECT  17.52 30.156 17.544 30.24 ;
    END
  END a_d[79]
  PIN a_d[7]
    DIRECTION INPUT ;
    USE SIGNAL ;
    PORT
      LAYER M5 ;
        RECT  14.064 30.156 14.088 30.24 ;
    END
  END a_d[7]
  PIN a_d[80]
    DIRECTION INPUT ;
    USE SIGNAL ;
    PORT
      LAYER M5 ;
        RECT  17.568 30.156 17.592 30.24 ;
    END
  END a_d[80]
  PIN a_d[81]
    DIRECTION INPUT ;
    USE SIGNAL ;
    PORT
      LAYER M5 ;
        RECT  17.616 30.156 17.64 30.24 ;
    END
  END a_d[81]
  PIN a_d[82]
    DIRECTION INPUT ;
    USE SIGNAL ;
    PORT
      LAYER M5 ;
        RECT  17.664 30.156 17.688 30.24 ;
    END
  END a_d[82]
  PIN a_d[83]
    DIRECTION INPUT ;
    USE SIGNAL ;
    PORT
      LAYER M5 ;
        RECT  17.712 30.156 17.736 30.24 ;
    END
  END a_d[83]
  PIN a_d[84]
    DIRECTION INPUT ;
    USE SIGNAL ;
    PORT
      LAYER M5 ;
        RECT  17.76 30.156 17.784 30.24 ;
    END
  END a_d[84]
  PIN a_d[85]
    DIRECTION INPUT ;
    USE SIGNAL ;
    PORT
      LAYER M5 ;
        RECT  17.808 30.156 17.832 30.24 ;
    END
  END a_d[85]
  PIN a_d[86]
    DIRECTION INPUT ;
    USE SIGNAL ;
    PORT
      LAYER M5 ;
        RECT  17.856 30.156 17.88 30.24 ;
    END
  END a_d[86]
  PIN a_d[87]
    DIRECTION INPUT ;
    USE SIGNAL ;
    PORT
      LAYER M5 ;
        RECT  17.904 30.156 17.928 30.24 ;
    END
  END a_d[87]
  PIN a_d[88]
    DIRECTION INPUT ;
    USE SIGNAL ;
    PORT
      LAYER M5 ;
        RECT  17.952 30.156 17.976 30.24 ;
    END
  END a_d[88]
  PIN a_d[89]
    DIRECTION INPUT ;
    USE SIGNAL ;
    PORT
      LAYER M5 ;
        RECT  18 30.156 18.024 30.24 ;
    END
  END a_d[89]
  PIN a_d[8]
    DIRECTION INPUT ;
    USE SIGNAL ;
    PORT
      LAYER M5 ;
        RECT  14.112 30.156 14.136 30.24 ;
    END
  END a_d[8]
  PIN a_d[90]
    DIRECTION INPUT ;
    USE SIGNAL ;
    PORT
      LAYER M5 ;
        RECT  18.048 30.156 18.072 30.24 ;
    END
  END a_d[90]
  PIN a_d[91]
    DIRECTION INPUT ;
    USE SIGNAL ;
    PORT
      LAYER M5 ;
        RECT  18.096 30.156 18.12 30.24 ;
    END
  END a_d[91]
  PIN a_d[92]
    DIRECTION INPUT ;
    USE SIGNAL ;
    PORT
      LAYER M5 ;
        RECT  18.144 30.156 18.168 30.24 ;
    END
  END a_d[92]
  PIN a_d[93]
    DIRECTION INPUT ;
    USE SIGNAL ;
    PORT
      LAYER M5 ;
        RECT  18.192 30.156 18.216 30.24 ;
    END
  END a_d[93]
  PIN a_d[94]
    DIRECTION INPUT ;
    USE SIGNAL ;
    PORT
      LAYER M5 ;
        RECT  18.24 30.156 18.264 30.24 ;
    END
  END a_d[94]
  PIN a_d[95]
    DIRECTION INPUT ;
    USE SIGNAL ;
    PORT
      LAYER M5 ;
        RECT  18.288 30.156 18.312 30.24 ;
    END
  END a_d[95]
  PIN a_d[96]
    DIRECTION INPUT ;
    USE SIGNAL ;
    PORT
      LAYER M5 ;
        RECT  18.336 30.156 18.36 30.24 ;
    END
  END a_d[96]
  PIN a_d[97]
    DIRECTION INPUT ;
    USE SIGNAL ;
    PORT
      LAYER M5 ;
        RECT  18.384 30.156 18.408 30.24 ;
    END
  END a_d[97]
  PIN a_d[98]
    DIRECTION INPUT ;
    USE SIGNAL ;
    PORT
      LAYER M5 ;
        RECT  18.432 30.156 18.456 30.24 ;
    END
  END a_d[98]
  PIN a_d[99]
    DIRECTION INPUT ;
    USE SIGNAL ;
    PORT
      LAYER M5 ;
        RECT  18.48 30.156 18.504 30.24 ;
    END
  END a_d[99]
  PIN a_d[9]
    DIRECTION INPUT ;
    USE SIGNAL ;
    PORT
      LAYER M5 ;
        RECT  14.16 30.156 14.184 30.24 ;
    END
  END a_d[9]
  PIN a_r
    DIRECTION OUTPUT ;
    USE SIGNAL ;
    PORT
      LAYER M5 ;
        RECT  38.304 30.156 38.328 30.24 ;
    END
  END a_r
  PIN b_d[0]
    DIRECTION OUTPUT ;
    USE SIGNAL ;
    PORT
      LAYER M5 ;
        RECT  13.68 0 13.704 0.084 ;
    END
  END b_d[0]
  PIN b_d[100]
    DIRECTION OUTPUT ;
    USE SIGNAL ;
    PORT
      LAYER M5 ;
        RECT  18.48 0 18.504 0.084 ;
    END
  END b_d[100]
  PIN b_d[101]
    DIRECTION OUTPUT ;
    USE SIGNAL ;
    PORT
      LAYER M5 ;
        RECT  18.528 0 18.552 0.084 ;
    END
  END b_d[101]
  PIN b_d[102]
    DIRECTION OUTPUT ;
    USE SIGNAL ;
    PORT
      LAYER M5 ;
        RECT  18.576 0 18.6 0.084 ;
    END
  END b_d[102]
  PIN b_d[103]
    DIRECTION OUTPUT ;
    USE SIGNAL ;
    PORT
      LAYER M5 ;
        RECT  18.624 0 18.648 0.084 ;
    END
  END b_d[103]
  PIN b_d[104]
    DIRECTION OUTPUT ;
    USE SIGNAL ;
    PORT
      LAYER M5 ;
        RECT  18.672 0 18.696 0.084 ;
    END
  END b_d[104]
  PIN b_d[105]
    DIRECTION OUTPUT ;
    USE SIGNAL ;
    PORT
      LAYER M5 ;
        RECT  18.72 0 18.744 0.084 ;
    END
  END b_d[105]
  PIN b_d[106]
    DIRECTION OUTPUT ;
    USE SIGNAL ;
    PORT
      LAYER M5 ;
        RECT  18.768 0 18.792 0.084 ;
    END
  END b_d[106]
  PIN b_d[107]
    DIRECTION OUTPUT ;
    USE SIGNAL ;
    PORT
      LAYER M5 ;
        RECT  18.816 0 18.84 0.084 ;
    END
  END b_d[107]
  PIN b_d[108]
    DIRECTION OUTPUT ;
    USE SIGNAL ;
    PORT
      LAYER M5 ;
        RECT  18.864 0 18.888 0.084 ;
    END
  END b_d[108]
  PIN b_d[109]
    DIRECTION OUTPUT ;
    USE SIGNAL ;
    PORT
      LAYER M5 ;
        RECT  18.912 0 18.936 0.084 ;
    END
  END b_d[109]
  PIN b_d[10]
    DIRECTION OUTPUT ;
    USE SIGNAL ;
    PORT
      LAYER M5 ;
        RECT  14.16 0 14.184 0.084 ;
    END
  END b_d[10]
  PIN b_d[110]
    DIRECTION OUTPUT ;
    USE SIGNAL ;
    PORT
      LAYER M5 ;
        RECT  18.96 0 18.984 0.084 ;
    END
  END b_d[110]
  PIN b_d[111]
    DIRECTION OUTPUT ;
    USE SIGNAL ;
    PORT
      LAYER M5 ;
        RECT  19.008 0 19.032 0.084 ;
    END
  END b_d[111]
  PIN b_d[112]
    DIRECTION OUTPUT ;
    USE SIGNAL ;
    PORT
      LAYER M5 ;
        RECT  19.056 0 19.08 0.084 ;
    END
  END b_d[112]
  PIN b_d[113]
    DIRECTION OUTPUT ;
    USE SIGNAL ;
    PORT
      LAYER M5 ;
        RECT  19.104 0 19.128 0.084 ;
    END
  END b_d[113]
  PIN b_d[114]
    DIRECTION OUTPUT ;
    USE SIGNAL ;
    PORT
      LAYER M5 ;
        RECT  19.152 0 19.176 0.084 ;
    END
  END b_d[114]
  PIN b_d[115]
    DIRECTION OUTPUT ;
    USE SIGNAL ;
    PORT
      LAYER M5 ;
        RECT  19.2 0 19.224 0.084 ;
    END
  END b_d[115]
  PIN b_d[116]
    DIRECTION OUTPUT ;
    USE SIGNAL ;
    PORT
      LAYER M5 ;
        RECT  19.248 0 19.272 0.084 ;
    END
  END b_d[116]
  PIN b_d[117]
    DIRECTION OUTPUT ;
    USE SIGNAL ;
    PORT
      LAYER M5 ;
        RECT  19.296 0 19.32 0.084 ;
    END
  END b_d[117]
  PIN b_d[118]
    DIRECTION OUTPUT ;
    USE SIGNAL ;
    PORT
      LAYER M5 ;
        RECT  19.344 0 19.368 0.084 ;
    END
  END b_d[118]
  PIN b_d[119]
    DIRECTION OUTPUT ;
    USE SIGNAL ;
    PORT
      LAYER M5 ;
        RECT  19.392 0 19.416 0.084 ;
    END
  END b_d[119]
  PIN b_d[11]
    DIRECTION OUTPUT ;
    USE SIGNAL ;
    PORT
      LAYER M5 ;
        RECT  14.208 0 14.232 0.084 ;
    END
  END b_d[11]
  PIN b_d[120]
    DIRECTION OUTPUT ;
    USE SIGNAL ;
    PORT
      LAYER M5 ;
        RECT  19.44 0 19.464 0.084 ;
    END
  END b_d[120]
  PIN b_d[121]
    DIRECTION OUTPUT ;
    USE SIGNAL ;
    PORT
      LAYER M5 ;
        RECT  19.488 0 19.512 0.084 ;
    END
  END b_d[121]
  PIN b_d[122]
    DIRECTION OUTPUT ;
    USE SIGNAL ;
    PORT
      LAYER M5 ;
        RECT  19.536 0 19.56 0.084 ;
    END
  END b_d[122]
  PIN b_d[123]
    DIRECTION OUTPUT ;
    USE SIGNAL ;
    PORT
      LAYER M5 ;
        RECT  19.584 0 19.608 0.084 ;
    END
  END b_d[123]
  PIN b_d[124]
    DIRECTION OUTPUT ;
    USE SIGNAL ;
    PORT
      LAYER M5 ;
        RECT  19.632 0 19.656 0.084 ;
    END
  END b_d[124]
  PIN b_d[125]
    DIRECTION OUTPUT ;
    USE SIGNAL ;
    PORT
      LAYER M5 ;
        RECT  19.68 0 19.704 0.084 ;
    END
  END b_d[125]
  PIN b_d[126]
    DIRECTION OUTPUT ;
    USE SIGNAL ;
    PORT
      LAYER M5 ;
        RECT  19.728 0 19.752 0.084 ;
    END
  END b_d[126]
  PIN b_d[127]
    DIRECTION OUTPUT ;
    USE SIGNAL ;
    PORT
      LAYER M5 ;
        RECT  19.776 0 19.8 0.084 ;
    END
  END b_d[127]
  PIN b_d[128]
    DIRECTION OUTPUT ;
    USE SIGNAL ;
    PORT
      LAYER M5 ;
        RECT  19.824 0 19.848 0.084 ;
    END
  END b_d[128]
  PIN b_d[129]
    DIRECTION OUTPUT ;
    USE SIGNAL ;
    PORT
      LAYER M5 ;
        RECT  19.872 0 19.896 0.084 ;
    END
  END b_d[129]
  PIN b_d[12]
    DIRECTION OUTPUT ;
    USE SIGNAL ;
    PORT
      LAYER M5 ;
        RECT  14.256 0 14.28 0.084 ;
    END
  END b_d[12]
  PIN b_d[130]
    DIRECTION OUTPUT ;
    USE SIGNAL ;
    PORT
      LAYER M5 ;
        RECT  19.92 0 19.944 0.084 ;
    END
  END b_d[130]
  PIN b_d[131]
    DIRECTION OUTPUT ;
    USE SIGNAL ;
    PORT
      LAYER M5 ;
        RECT  19.968 0 19.992 0.084 ;
    END
  END b_d[131]
  PIN b_d[132]
    DIRECTION OUTPUT ;
    USE SIGNAL ;
    PORT
      LAYER M5 ;
        RECT  20.016 0 20.04 0.084 ;
    END
  END b_d[132]
  PIN b_d[133]
    DIRECTION OUTPUT ;
    USE SIGNAL ;
    PORT
      LAYER M5 ;
        RECT  20.064 0 20.088 0.084 ;
    END
  END b_d[133]
  PIN b_d[134]
    DIRECTION OUTPUT ;
    USE SIGNAL ;
    PORT
      LAYER M5 ;
        RECT  20.112 0 20.136 0.084 ;
    END
  END b_d[134]
  PIN b_d[135]
    DIRECTION OUTPUT ;
    USE SIGNAL ;
    PORT
      LAYER M5 ;
        RECT  20.16 0 20.184 0.084 ;
    END
  END b_d[135]
  PIN b_d[136]
    DIRECTION OUTPUT ;
    USE SIGNAL ;
    PORT
      LAYER M5 ;
        RECT  20.208 0 20.232 0.084 ;
    END
  END b_d[136]
  PIN b_d[137]
    DIRECTION OUTPUT ;
    USE SIGNAL ;
    PORT
      LAYER M5 ;
        RECT  20.256 0 20.28 0.084 ;
    END
  END b_d[137]
  PIN b_d[138]
    DIRECTION OUTPUT ;
    USE SIGNAL ;
    PORT
      LAYER M5 ;
        RECT  20.304 0 20.328 0.084 ;
    END
  END b_d[138]
  PIN b_d[139]
    DIRECTION OUTPUT ;
    USE SIGNAL ;
    PORT
      LAYER M5 ;
        RECT  20.352 0 20.376 0.084 ;
    END
  END b_d[139]
  PIN b_d[13]
    DIRECTION OUTPUT ;
    USE SIGNAL ;
    PORT
      LAYER M5 ;
        RECT  14.304 0 14.328 0.084 ;
    END
  END b_d[13]
  PIN b_d[140]
    DIRECTION OUTPUT ;
    USE SIGNAL ;
    PORT
      LAYER M5 ;
        RECT  20.4 0 20.424 0.084 ;
    END
  END b_d[140]
  PIN b_d[141]
    DIRECTION OUTPUT ;
    USE SIGNAL ;
    PORT
      LAYER M5 ;
        RECT  20.448 0 20.472 0.084 ;
    END
  END b_d[141]
  PIN b_d[142]
    DIRECTION OUTPUT ;
    USE SIGNAL ;
    PORT
      LAYER M5 ;
        RECT  20.496 0 20.52 0.084 ;
    END
  END b_d[142]
  PIN b_d[143]
    DIRECTION OUTPUT ;
    USE SIGNAL ;
    PORT
      LAYER M5 ;
        RECT  20.544 0 20.568 0.084 ;
    END
  END b_d[143]
  PIN b_d[144]
    DIRECTION OUTPUT ;
    USE SIGNAL ;
    PORT
      LAYER M5 ;
        RECT  20.592 0 20.616 0.084 ;
    END
  END b_d[144]
  PIN b_d[145]
    DIRECTION OUTPUT ;
    USE SIGNAL ;
    PORT
      LAYER M5 ;
        RECT  20.64 0 20.664 0.084 ;
    END
  END b_d[145]
  PIN b_d[146]
    DIRECTION OUTPUT ;
    USE SIGNAL ;
    PORT
      LAYER M5 ;
        RECT  20.688 0 20.712 0.084 ;
    END
  END b_d[146]
  PIN b_d[147]
    DIRECTION OUTPUT ;
    USE SIGNAL ;
    PORT
      LAYER M5 ;
        RECT  20.736 0 20.76 0.084 ;
    END
  END b_d[147]
  PIN b_d[148]
    DIRECTION OUTPUT ;
    USE SIGNAL ;
    PORT
      LAYER M5 ;
        RECT  20.784 0 20.808 0.084 ;
    END
  END b_d[148]
  PIN b_d[149]
    DIRECTION OUTPUT ;
    USE SIGNAL ;
    PORT
      LAYER M5 ;
        RECT  20.832 0 20.856 0.084 ;
    END
  END b_d[149]
  PIN b_d[14]
    DIRECTION OUTPUT ;
    USE SIGNAL ;
    PORT
      LAYER M5 ;
        RECT  14.352 0 14.376 0.084 ;
    END
  END b_d[14]
  PIN b_d[150]
    DIRECTION OUTPUT ;
    USE SIGNAL ;
    PORT
      LAYER M5 ;
        RECT  20.88 0 20.904 0.084 ;
    END
  END b_d[150]
  PIN b_d[151]
    DIRECTION OUTPUT ;
    USE SIGNAL ;
    PORT
      LAYER M5 ;
        RECT  20.928 0 20.952 0.084 ;
    END
  END b_d[151]
  PIN b_d[152]
    DIRECTION OUTPUT ;
    USE SIGNAL ;
    PORT
      LAYER M5 ;
        RECT  20.976 0 21 0.084 ;
    END
  END b_d[152]
  PIN b_d[153]
    DIRECTION OUTPUT ;
    USE SIGNAL ;
    PORT
      LAYER M5 ;
        RECT  21.024 0 21.048 0.084 ;
    END
  END b_d[153]
  PIN b_d[154]
    DIRECTION OUTPUT ;
    USE SIGNAL ;
    PORT
      LAYER M5 ;
        RECT  21.072 0 21.096 0.084 ;
    END
  END b_d[154]
  PIN b_d[155]
    DIRECTION OUTPUT ;
    USE SIGNAL ;
    PORT
      LAYER M5 ;
        RECT  21.12 0 21.144 0.084 ;
    END
  END b_d[155]
  PIN b_d[156]
    DIRECTION OUTPUT ;
    USE SIGNAL ;
    PORT
      LAYER M5 ;
        RECT  21.168 0 21.192 0.084 ;
    END
  END b_d[156]
  PIN b_d[157]
    DIRECTION OUTPUT ;
    USE SIGNAL ;
    PORT
      LAYER M5 ;
        RECT  21.216 0 21.24 0.084 ;
    END
  END b_d[157]
  PIN b_d[158]
    DIRECTION OUTPUT ;
    USE SIGNAL ;
    PORT
      LAYER M5 ;
        RECT  21.264 0 21.288 0.084 ;
    END
  END b_d[158]
  PIN b_d[159]
    DIRECTION OUTPUT ;
    USE SIGNAL ;
    PORT
      LAYER M5 ;
        RECT  21.312 0 21.336 0.084 ;
    END
  END b_d[159]
  PIN b_d[15]
    DIRECTION OUTPUT ;
    USE SIGNAL ;
    PORT
      LAYER M5 ;
        RECT  14.4 0 14.424 0.084 ;
    END
  END b_d[15]
  PIN b_d[160]
    DIRECTION OUTPUT ;
    USE SIGNAL ;
    PORT
      LAYER M5 ;
        RECT  21.36 0 21.384 0.084 ;
    END
  END b_d[160]
  PIN b_d[161]
    DIRECTION OUTPUT ;
    USE SIGNAL ;
    PORT
      LAYER M5 ;
        RECT  21.408 0 21.432 0.084 ;
    END
  END b_d[161]
  PIN b_d[162]
    DIRECTION OUTPUT ;
    USE SIGNAL ;
    PORT
      LAYER M5 ;
        RECT  21.456 0 21.48 0.084 ;
    END
  END b_d[162]
  PIN b_d[163]
    DIRECTION OUTPUT ;
    USE SIGNAL ;
    PORT
      LAYER M5 ;
        RECT  21.504 0 21.528 0.084 ;
    END
  END b_d[163]
  PIN b_d[164]
    DIRECTION OUTPUT ;
    USE SIGNAL ;
    PORT
      LAYER M5 ;
        RECT  21.552 0 21.576 0.084 ;
    END
  END b_d[164]
  PIN b_d[165]
    DIRECTION OUTPUT ;
    USE SIGNAL ;
    PORT
      LAYER M5 ;
        RECT  21.6 0 21.624 0.084 ;
    END
  END b_d[165]
  PIN b_d[166]
    DIRECTION OUTPUT ;
    USE SIGNAL ;
    PORT
      LAYER M5 ;
        RECT  21.648 0 21.672 0.084 ;
    END
  END b_d[166]
  PIN b_d[167]
    DIRECTION OUTPUT ;
    USE SIGNAL ;
    PORT
      LAYER M5 ;
        RECT  21.696 0 21.72 0.084 ;
    END
  END b_d[167]
  PIN b_d[168]
    DIRECTION OUTPUT ;
    USE SIGNAL ;
    PORT
      LAYER M5 ;
        RECT  21.744 0 21.768 0.084 ;
    END
  END b_d[168]
  PIN b_d[169]
    DIRECTION OUTPUT ;
    USE SIGNAL ;
    PORT
      LAYER M5 ;
        RECT  21.792 0 21.816 0.084 ;
    END
  END b_d[169]
  PIN b_d[16]
    DIRECTION OUTPUT ;
    USE SIGNAL ;
    PORT
      LAYER M5 ;
        RECT  14.448 0 14.472 0.084 ;
    END
  END b_d[16]
  PIN b_d[170]
    DIRECTION OUTPUT ;
    USE SIGNAL ;
    PORT
      LAYER M5 ;
        RECT  21.84 0 21.864 0.084 ;
    END
  END b_d[170]
  PIN b_d[171]
    DIRECTION OUTPUT ;
    USE SIGNAL ;
    PORT
      LAYER M5 ;
        RECT  21.888 0 21.912 0.084 ;
    END
  END b_d[171]
  PIN b_d[172]
    DIRECTION OUTPUT ;
    USE SIGNAL ;
    PORT
      LAYER M5 ;
        RECT  21.936 0 21.96 0.084 ;
    END
  END b_d[172]
  PIN b_d[173]
    DIRECTION OUTPUT ;
    USE SIGNAL ;
    PORT
      LAYER M5 ;
        RECT  21.984 0 22.008 0.084 ;
    END
  END b_d[173]
  PIN b_d[174]
    DIRECTION OUTPUT ;
    USE SIGNAL ;
    PORT
      LAYER M5 ;
        RECT  22.032 0 22.056 0.084 ;
    END
  END b_d[174]
  PIN b_d[175]
    DIRECTION OUTPUT ;
    USE SIGNAL ;
    PORT
      LAYER M5 ;
        RECT  22.08 0 22.104 0.084 ;
    END
  END b_d[175]
  PIN b_d[176]
    DIRECTION OUTPUT ;
    USE SIGNAL ;
    PORT
      LAYER M5 ;
        RECT  22.128 0 22.152 0.084 ;
    END
  END b_d[176]
  PIN b_d[177]
    DIRECTION OUTPUT ;
    USE SIGNAL ;
    PORT
      LAYER M5 ;
        RECT  22.176 0 22.2 0.084 ;
    END
  END b_d[177]
  PIN b_d[178]
    DIRECTION OUTPUT ;
    USE SIGNAL ;
    PORT
      LAYER M5 ;
        RECT  22.224 0 22.248 0.084 ;
    END
  END b_d[178]
  PIN b_d[179]
    DIRECTION OUTPUT ;
    USE SIGNAL ;
    PORT
      LAYER M5 ;
        RECT  22.272 0 22.296 0.084 ;
    END
  END b_d[179]
  PIN b_d[17]
    DIRECTION OUTPUT ;
    USE SIGNAL ;
    PORT
      LAYER M5 ;
        RECT  14.496 0 14.52 0.084 ;
    END
  END b_d[17]
  PIN b_d[180]
    DIRECTION OUTPUT ;
    USE SIGNAL ;
    PORT
      LAYER M5 ;
        RECT  22.32 0 22.344 0.084 ;
    END
  END b_d[180]
  PIN b_d[181]
    DIRECTION OUTPUT ;
    USE SIGNAL ;
    PORT
      LAYER M5 ;
        RECT  22.368 0 22.392 0.084 ;
    END
  END b_d[181]
  PIN b_d[182]
    DIRECTION OUTPUT ;
    USE SIGNAL ;
    PORT
      LAYER M5 ;
        RECT  22.416 0 22.44 0.084 ;
    END
  END b_d[182]
  PIN b_d[183]
    DIRECTION OUTPUT ;
    USE SIGNAL ;
    PORT
      LAYER M5 ;
        RECT  22.464 0 22.488 0.084 ;
    END
  END b_d[183]
  PIN b_d[184]
    DIRECTION OUTPUT ;
    USE SIGNAL ;
    PORT
      LAYER M5 ;
        RECT  22.512 0 22.536 0.084 ;
    END
  END b_d[184]
  PIN b_d[185]
    DIRECTION OUTPUT ;
    USE SIGNAL ;
    PORT
      LAYER M5 ;
        RECT  22.56 0 22.584 0.084 ;
    END
  END b_d[185]
  PIN b_d[186]
    DIRECTION OUTPUT ;
    USE SIGNAL ;
    PORT
      LAYER M5 ;
        RECT  22.608 0 22.632 0.084 ;
    END
  END b_d[186]
  PIN b_d[187]
    DIRECTION OUTPUT ;
    USE SIGNAL ;
    PORT
      LAYER M5 ;
        RECT  22.656 0 22.68 0.084 ;
    END
  END b_d[187]
  PIN b_d[188]
    DIRECTION OUTPUT ;
    USE SIGNAL ;
    PORT
      LAYER M5 ;
        RECT  22.704 0 22.728 0.084 ;
    END
  END b_d[188]
  PIN b_d[189]
    DIRECTION OUTPUT ;
    USE SIGNAL ;
    PORT
      LAYER M5 ;
        RECT  22.752 0 22.776 0.084 ;
    END
  END b_d[189]
  PIN b_d[18]
    DIRECTION OUTPUT ;
    USE SIGNAL ;
    PORT
      LAYER M5 ;
        RECT  14.544 0 14.568 0.084 ;
    END
  END b_d[18]
  PIN b_d[190]
    DIRECTION OUTPUT ;
    USE SIGNAL ;
    PORT
      LAYER M5 ;
        RECT  22.8 0 22.824 0.084 ;
    END
  END b_d[190]
  PIN b_d[191]
    DIRECTION OUTPUT ;
    USE SIGNAL ;
    PORT
      LAYER M5 ;
        RECT  22.848 0 22.872 0.084 ;
    END
  END b_d[191]
  PIN b_d[192]
    DIRECTION OUTPUT ;
    USE SIGNAL ;
    PORT
      LAYER M5 ;
        RECT  22.896 0 22.92 0.084 ;
    END
  END b_d[192]
  PIN b_d[193]
    DIRECTION OUTPUT ;
    USE SIGNAL ;
    PORT
      LAYER M5 ;
        RECT  22.944 0 22.968 0.084 ;
    END
  END b_d[193]
  PIN b_d[194]
    DIRECTION OUTPUT ;
    USE SIGNAL ;
    PORT
      LAYER M5 ;
        RECT  22.992 0 23.016 0.084 ;
    END
  END b_d[194]
  PIN b_d[195]
    DIRECTION OUTPUT ;
    USE SIGNAL ;
    PORT
      LAYER M5 ;
        RECT  23.04 0 23.064 0.084 ;
    END
  END b_d[195]
  PIN b_d[196]
    DIRECTION OUTPUT ;
    USE SIGNAL ;
    PORT
      LAYER M5 ;
        RECT  23.088 0 23.112 0.084 ;
    END
  END b_d[196]
  PIN b_d[197]
    DIRECTION OUTPUT ;
    USE SIGNAL ;
    PORT
      LAYER M5 ;
        RECT  23.136 0 23.16 0.084 ;
    END
  END b_d[197]
  PIN b_d[198]
    DIRECTION OUTPUT ;
    USE SIGNAL ;
    PORT
      LAYER M5 ;
        RECT  23.184 0 23.208 0.084 ;
    END
  END b_d[198]
  PIN b_d[199]
    DIRECTION OUTPUT ;
    USE SIGNAL ;
    PORT
      LAYER M5 ;
        RECT  23.232 0 23.256 0.084 ;
    END
  END b_d[199]
  PIN b_d[19]
    DIRECTION OUTPUT ;
    USE SIGNAL ;
    PORT
      LAYER M5 ;
        RECT  14.592 0 14.616 0.084 ;
    END
  END b_d[19]
  PIN b_d[1]
    DIRECTION OUTPUT ;
    USE SIGNAL ;
    PORT
      LAYER M5 ;
        RECT  13.728 0 13.752 0.084 ;
    END
  END b_d[1]
  PIN b_d[200]
    DIRECTION OUTPUT ;
    USE SIGNAL ;
    PORT
      LAYER M5 ;
        RECT  23.28 0 23.304 0.084 ;
    END
  END b_d[200]
  PIN b_d[201]
    DIRECTION OUTPUT ;
    USE SIGNAL ;
    PORT
      LAYER M5 ;
        RECT  23.328 0 23.352 0.084 ;
    END
  END b_d[201]
  PIN b_d[202]
    DIRECTION OUTPUT ;
    USE SIGNAL ;
    PORT
      LAYER M5 ;
        RECT  23.376 0 23.4 0.084 ;
    END
  END b_d[202]
  PIN b_d[203]
    DIRECTION OUTPUT ;
    USE SIGNAL ;
    PORT
      LAYER M5 ;
        RECT  23.424 0 23.448 0.084 ;
    END
  END b_d[203]
  PIN b_d[204]
    DIRECTION OUTPUT ;
    USE SIGNAL ;
    PORT
      LAYER M5 ;
        RECT  23.472 0 23.496 0.084 ;
    END
  END b_d[204]
  PIN b_d[205]
    DIRECTION OUTPUT ;
    USE SIGNAL ;
    PORT
      LAYER M5 ;
        RECT  23.52 0 23.544 0.084 ;
    END
  END b_d[205]
  PIN b_d[206]
    DIRECTION OUTPUT ;
    USE SIGNAL ;
    PORT
      LAYER M5 ;
        RECT  23.568 0 23.592 0.084 ;
    END
  END b_d[206]
  PIN b_d[207]
    DIRECTION OUTPUT ;
    USE SIGNAL ;
    PORT
      LAYER M5 ;
        RECT  23.616 0 23.64 0.084 ;
    END
  END b_d[207]
  PIN b_d[208]
    DIRECTION OUTPUT ;
    USE SIGNAL ;
    PORT
      LAYER M5 ;
        RECT  23.664 0 23.688 0.084 ;
    END
  END b_d[208]
  PIN b_d[209]
    DIRECTION OUTPUT ;
    USE SIGNAL ;
    PORT
      LAYER M5 ;
        RECT  23.712 0 23.736 0.084 ;
    END
  END b_d[209]
  PIN b_d[20]
    DIRECTION OUTPUT ;
    USE SIGNAL ;
    PORT
      LAYER M5 ;
        RECT  14.64 0 14.664 0.084 ;
    END
  END b_d[20]
  PIN b_d[210]
    DIRECTION OUTPUT ;
    USE SIGNAL ;
    PORT
      LAYER M5 ;
        RECT  23.76 0 23.784 0.084 ;
    END
  END b_d[210]
  PIN b_d[211]
    DIRECTION OUTPUT ;
    USE SIGNAL ;
    PORT
      LAYER M5 ;
        RECT  23.808 0 23.832 0.084 ;
    END
  END b_d[211]
  PIN b_d[212]
    DIRECTION OUTPUT ;
    USE SIGNAL ;
    PORT
      LAYER M5 ;
        RECT  23.856 0 23.88 0.084 ;
    END
  END b_d[212]
  PIN b_d[213]
    DIRECTION OUTPUT ;
    USE SIGNAL ;
    PORT
      LAYER M5 ;
        RECT  23.904 0 23.928 0.084 ;
    END
  END b_d[213]
  PIN b_d[214]
    DIRECTION OUTPUT ;
    USE SIGNAL ;
    PORT
      LAYER M5 ;
        RECT  23.952 0 23.976 0.084 ;
    END
  END b_d[214]
  PIN b_d[215]
    DIRECTION OUTPUT ;
    USE SIGNAL ;
    PORT
      LAYER M5 ;
        RECT  24 0 24.024 0.084 ;
    END
  END b_d[215]
  PIN b_d[216]
    DIRECTION OUTPUT ;
    USE SIGNAL ;
    PORT
      LAYER M5 ;
        RECT  24.048 0 24.072 0.084 ;
    END
  END b_d[216]
  PIN b_d[217]
    DIRECTION OUTPUT ;
    USE SIGNAL ;
    PORT
      LAYER M5 ;
        RECT  24.096 0 24.12 0.084 ;
    END
  END b_d[217]
  PIN b_d[218]
    DIRECTION OUTPUT ;
    USE SIGNAL ;
    PORT
      LAYER M5 ;
        RECT  24.144 0 24.168 0.084 ;
    END
  END b_d[218]
  PIN b_d[219]
    DIRECTION OUTPUT ;
    USE SIGNAL ;
    PORT
      LAYER M5 ;
        RECT  24.192 0 24.216 0.084 ;
    END
  END b_d[219]
  PIN b_d[21]
    DIRECTION OUTPUT ;
    USE SIGNAL ;
    PORT
      LAYER M5 ;
        RECT  14.688 0 14.712 0.084 ;
    END
  END b_d[21]
  PIN b_d[220]
    DIRECTION OUTPUT ;
    USE SIGNAL ;
    PORT
      LAYER M5 ;
        RECT  24.24 0 24.264 0.084 ;
    END
  END b_d[220]
  PIN b_d[221]
    DIRECTION OUTPUT ;
    USE SIGNAL ;
    PORT
      LAYER M5 ;
        RECT  24.288 0 24.312 0.084 ;
    END
  END b_d[221]
  PIN b_d[222]
    DIRECTION OUTPUT ;
    USE SIGNAL ;
    PORT
      LAYER M5 ;
        RECT  24.336 0 24.36 0.084 ;
    END
  END b_d[222]
  PIN b_d[223]
    DIRECTION OUTPUT ;
    USE SIGNAL ;
    PORT
      LAYER M5 ;
        RECT  24.384 0 24.408 0.084 ;
    END
  END b_d[223]
  PIN b_d[224]
    DIRECTION OUTPUT ;
    USE SIGNAL ;
    PORT
      LAYER M5 ;
        RECT  24.432 0 24.456 0.084 ;
    END
  END b_d[224]
  PIN b_d[225]
    DIRECTION OUTPUT ;
    USE SIGNAL ;
    PORT
      LAYER M5 ;
        RECT  24.48 0 24.504 0.084 ;
    END
  END b_d[225]
  PIN b_d[226]
    DIRECTION OUTPUT ;
    USE SIGNAL ;
    PORT
      LAYER M5 ;
        RECT  24.528 0 24.552 0.084 ;
    END
  END b_d[226]
  PIN b_d[227]
    DIRECTION OUTPUT ;
    USE SIGNAL ;
    PORT
      LAYER M5 ;
        RECT  24.576 0 24.6 0.084 ;
    END
  END b_d[227]
  PIN b_d[228]
    DIRECTION OUTPUT ;
    USE SIGNAL ;
    PORT
      LAYER M5 ;
        RECT  24.624 0 24.648 0.084 ;
    END
  END b_d[228]
  PIN b_d[229]
    DIRECTION OUTPUT ;
    USE SIGNAL ;
    PORT
      LAYER M5 ;
        RECT  24.672 0 24.696 0.084 ;
    END
  END b_d[229]
  PIN b_d[22]
    DIRECTION OUTPUT ;
    USE SIGNAL ;
    PORT
      LAYER M5 ;
        RECT  14.736 0 14.76 0.084 ;
    END
  END b_d[22]
  PIN b_d[230]
    DIRECTION OUTPUT ;
    USE SIGNAL ;
    PORT
      LAYER M5 ;
        RECT  24.72 0 24.744 0.084 ;
    END
  END b_d[230]
  PIN b_d[231]
    DIRECTION OUTPUT ;
    USE SIGNAL ;
    PORT
      LAYER M5 ;
        RECT  24.768 0 24.792 0.084 ;
    END
  END b_d[231]
  PIN b_d[232]
    DIRECTION OUTPUT ;
    USE SIGNAL ;
    PORT
      LAYER M5 ;
        RECT  24.816 0 24.84 0.084 ;
    END
  END b_d[232]
  PIN b_d[233]
    DIRECTION OUTPUT ;
    USE SIGNAL ;
    PORT
      LAYER M5 ;
        RECT  24.864 0 24.888 0.084 ;
    END
  END b_d[233]
  PIN b_d[234]
    DIRECTION OUTPUT ;
    USE SIGNAL ;
    PORT
      LAYER M5 ;
        RECT  24.912 0 24.936 0.084 ;
    END
  END b_d[234]
  PIN b_d[235]
    DIRECTION OUTPUT ;
    USE SIGNAL ;
    PORT
      LAYER M5 ;
        RECT  24.96 0 24.984 0.084 ;
    END
  END b_d[235]
  PIN b_d[236]
    DIRECTION OUTPUT ;
    USE SIGNAL ;
    PORT
      LAYER M5 ;
        RECT  25.008 0 25.032 0.084 ;
    END
  END b_d[236]
  PIN b_d[237]
    DIRECTION OUTPUT ;
    USE SIGNAL ;
    PORT
      LAYER M5 ;
        RECT  25.056 0 25.08 0.084 ;
    END
  END b_d[237]
  PIN b_d[238]
    DIRECTION OUTPUT ;
    USE SIGNAL ;
    PORT
      LAYER M5 ;
        RECT  25.104 0 25.128 0.084 ;
    END
  END b_d[238]
  PIN b_d[239]
    DIRECTION OUTPUT ;
    USE SIGNAL ;
    PORT
      LAYER M5 ;
        RECT  25.152 0 25.176 0.084 ;
    END
  END b_d[239]
  PIN b_d[23]
    DIRECTION OUTPUT ;
    USE SIGNAL ;
    PORT
      LAYER M5 ;
        RECT  14.784 0 14.808 0.084 ;
    END
  END b_d[23]
  PIN b_d[240]
    DIRECTION OUTPUT ;
    USE SIGNAL ;
    PORT
      LAYER M5 ;
        RECT  25.2 0 25.224 0.084 ;
    END
  END b_d[240]
  PIN b_d[241]
    DIRECTION OUTPUT ;
    USE SIGNAL ;
    PORT
      LAYER M5 ;
        RECT  25.248 0 25.272 0.084 ;
    END
  END b_d[241]
  PIN b_d[242]
    DIRECTION OUTPUT ;
    USE SIGNAL ;
    PORT
      LAYER M5 ;
        RECT  25.296 0 25.32 0.084 ;
    END
  END b_d[242]
  PIN b_d[243]
    DIRECTION OUTPUT ;
    USE SIGNAL ;
    PORT
      LAYER M5 ;
        RECT  25.344 0 25.368 0.084 ;
    END
  END b_d[243]
  PIN b_d[244]
    DIRECTION OUTPUT ;
    USE SIGNAL ;
    PORT
      LAYER M5 ;
        RECT  25.392 0 25.416 0.084 ;
    END
  END b_d[244]
  PIN b_d[245]
    DIRECTION OUTPUT ;
    USE SIGNAL ;
    PORT
      LAYER M5 ;
        RECT  25.44 0 25.464 0.084 ;
    END
  END b_d[245]
  PIN b_d[246]
    DIRECTION OUTPUT ;
    USE SIGNAL ;
    PORT
      LAYER M5 ;
        RECT  25.488 0 25.512 0.084 ;
    END
  END b_d[246]
  PIN b_d[247]
    DIRECTION OUTPUT ;
    USE SIGNAL ;
    PORT
      LAYER M5 ;
        RECT  25.536 0 25.56 0.084 ;
    END
  END b_d[247]
  PIN b_d[248]
    DIRECTION OUTPUT ;
    USE SIGNAL ;
    PORT
      LAYER M5 ;
        RECT  25.584 0 25.608 0.084 ;
    END
  END b_d[248]
  PIN b_d[249]
    DIRECTION OUTPUT ;
    USE SIGNAL ;
    PORT
      LAYER M5 ;
        RECT  25.632 0 25.656 0.084 ;
    END
  END b_d[249]
  PIN b_d[24]
    DIRECTION OUTPUT ;
    USE SIGNAL ;
    PORT
      LAYER M5 ;
        RECT  14.832 0 14.856 0.084 ;
    END
  END b_d[24]
  PIN b_d[250]
    DIRECTION OUTPUT ;
    USE SIGNAL ;
    PORT
      LAYER M5 ;
        RECT  25.68 0 25.704 0.084 ;
    END
  END b_d[250]
  PIN b_d[251]
    DIRECTION OUTPUT ;
    USE SIGNAL ;
    PORT
      LAYER M5 ;
        RECT  25.728 0 25.752 0.084 ;
    END
  END b_d[251]
  PIN b_d[252]
    DIRECTION OUTPUT ;
    USE SIGNAL ;
    PORT
      LAYER M5 ;
        RECT  25.776 0 25.8 0.084 ;
    END
  END b_d[252]
  PIN b_d[253]
    DIRECTION OUTPUT ;
    USE SIGNAL ;
    PORT
      LAYER M5 ;
        RECT  25.824 0 25.848 0.084 ;
    END
  END b_d[253]
  PIN b_d[254]
    DIRECTION OUTPUT ;
    USE SIGNAL ;
    PORT
      LAYER M5 ;
        RECT  25.872 0 25.896 0.084 ;
    END
  END b_d[254]
  PIN b_d[255]
    DIRECTION OUTPUT ;
    USE SIGNAL ;
    PORT
      LAYER M5 ;
        RECT  25.92 0 25.944 0.084 ;
    END
  END b_d[255]
  PIN b_d[256]
    DIRECTION OUTPUT ;
    USE SIGNAL ;
    PORT
      LAYER M5 ;
        RECT  25.968 0 25.992 0.084 ;
    END
  END b_d[256]
  PIN b_d[257]
    DIRECTION OUTPUT ;
    USE SIGNAL ;
    PORT
      LAYER M5 ;
        RECT  26.016 0 26.04 0.084 ;
    END
  END b_d[257]
  PIN b_d[258]
    DIRECTION OUTPUT ;
    USE SIGNAL ;
    PORT
      LAYER M5 ;
        RECT  26.064 0 26.088 0.084 ;
    END
  END b_d[258]
  PIN b_d[259]
    DIRECTION OUTPUT ;
    USE SIGNAL ;
    PORT
      LAYER M5 ;
        RECT  26.112 0 26.136 0.084 ;
    END
  END b_d[259]
  PIN b_d[25]
    DIRECTION OUTPUT ;
    USE SIGNAL ;
    PORT
      LAYER M5 ;
        RECT  14.88 0 14.904 0.084 ;
    END
  END b_d[25]
  PIN b_d[260]
    DIRECTION OUTPUT ;
    USE SIGNAL ;
    PORT
      LAYER M5 ;
        RECT  26.16 0 26.184 0.084 ;
    END
  END b_d[260]
  PIN b_d[261]
    DIRECTION OUTPUT ;
    USE SIGNAL ;
    PORT
      LAYER M5 ;
        RECT  26.208 0 26.232 0.084 ;
    END
  END b_d[261]
  PIN b_d[262]
    DIRECTION OUTPUT ;
    USE SIGNAL ;
    PORT
      LAYER M5 ;
        RECT  26.256 0 26.28 0.084 ;
    END
  END b_d[262]
  PIN b_d[263]
    DIRECTION OUTPUT ;
    USE SIGNAL ;
    PORT
      LAYER M5 ;
        RECT  26.304 0 26.328 0.084 ;
    END
  END b_d[263]
  PIN b_d[264]
    DIRECTION OUTPUT ;
    USE SIGNAL ;
    PORT
      LAYER M5 ;
        RECT  26.352 0 26.376 0.084 ;
    END
  END b_d[264]
  PIN b_d[265]
    DIRECTION OUTPUT ;
    USE SIGNAL ;
    PORT
      LAYER M5 ;
        RECT  26.4 0 26.424 0.084 ;
    END
  END b_d[265]
  PIN b_d[266]
    DIRECTION OUTPUT ;
    USE SIGNAL ;
    PORT
      LAYER M5 ;
        RECT  26.448 0 26.472 0.084 ;
    END
  END b_d[266]
  PIN b_d[267]
    DIRECTION OUTPUT ;
    USE SIGNAL ;
    PORT
      LAYER M5 ;
        RECT  26.496 0 26.52 0.084 ;
    END
  END b_d[267]
  PIN b_d[268]
    DIRECTION OUTPUT ;
    USE SIGNAL ;
    PORT
      LAYER M5 ;
        RECT  26.544 0 26.568 0.084 ;
    END
  END b_d[268]
  PIN b_d[269]
    DIRECTION OUTPUT ;
    USE SIGNAL ;
    PORT
      LAYER M5 ;
        RECT  26.592 0 26.616 0.084 ;
    END
  END b_d[269]
  PIN b_d[26]
    DIRECTION OUTPUT ;
    USE SIGNAL ;
    PORT
      LAYER M5 ;
        RECT  14.928 0 14.952 0.084 ;
    END
  END b_d[26]
  PIN b_d[270]
    DIRECTION OUTPUT ;
    USE SIGNAL ;
    PORT
      LAYER M5 ;
        RECT  26.64 0 26.664 0.084 ;
    END
  END b_d[270]
  PIN b_d[271]
    DIRECTION OUTPUT ;
    USE SIGNAL ;
    PORT
      LAYER M5 ;
        RECT  26.688 0 26.712 0.084 ;
    END
  END b_d[271]
  PIN b_d[272]
    DIRECTION OUTPUT ;
    USE SIGNAL ;
    PORT
      LAYER M5 ;
        RECT  26.736 0 26.76 0.084 ;
    END
  END b_d[272]
  PIN b_d[273]
    DIRECTION OUTPUT ;
    USE SIGNAL ;
    PORT
      LAYER M5 ;
        RECT  26.784 0 26.808 0.084 ;
    END
  END b_d[273]
  PIN b_d[274]
    DIRECTION OUTPUT ;
    USE SIGNAL ;
    PORT
      LAYER M5 ;
        RECT  26.832 0 26.856 0.084 ;
    END
  END b_d[274]
  PIN b_d[275]
    DIRECTION OUTPUT ;
    USE SIGNAL ;
    PORT
      LAYER M5 ;
        RECT  26.88 0 26.904 0.084 ;
    END
  END b_d[275]
  PIN b_d[276]
    DIRECTION OUTPUT ;
    USE SIGNAL ;
    PORT
      LAYER M5 ;
        RECT  26.928 0 26.952 0.084 ;
    END
  END b_d[276]
  PIN b_d[277]
    DIRECTION OUTPUT ;
    USE SIGNAL ;
    PORT
      LAYER M5 ;
        RECT  26.976 0 27 0.084 ;
    END
  END b_d[277]
  PIN b_d[278]
    DIRECTION OUTPUT ;
    USE SIGNAL ;
    PORT
      LAYER M5 ;
        RECT  27.024 0 27.048 0.084 ;
    END
  END b_d[278]
  PIN b_d[279]
    DIRECTION OUTPUT ;
    USE SIGNAL ;
    PORT
      LAYER M5 ;
        RECT  27.072 0 27.096 0.084 ;
    END
  END b_d[279]
  PIN b_d[27]
    DIRECTION OUTPUT ;
    USE SIGNAL ;
    PORT
      LAYER M5 ;
        RECT  14.976 0 15 0.084 ;
    END
  END b_d[27]
  PIN b_d[280]
    DIRECTION OUTPUT ;
    USE SIGNAL ;
    PORT
      LAYER M5 ;
        RECT  27.12 0 27.144 0.084 ;
    END
  END b_d[280]
  PIN b_d[281]
    DIRECTION OUTPUT ;
    USE SIGNAL ;
    PORT
      LAYER M5 ;
        RECT  27.168 0 27.192 0.084 ;
    END
  END b_d[281]
  PIN b_d[282]
    DIRECTION OUTPUT ;
    USE SIGNAL ;
    PORT
      LAYER M5 ;
        RECT  27.216 0 27.24 0.084 ;
    END
  END b_d[282]
  PIN b_d[283]
    DIRECTION OUTPUT ;
    USE SIGNAL ;
    PORT
      LAYER M5 ;
        RECT  27.264 0 27.288 0.084 ;
    END
  END b_d[283]
  PIN b_d[284]
    DIRECTION OUTPUT ;
    USE SIGNAL ;
    PORT
      LAYER M5 ;
        RECT  27.312 0 27.336 0.084 ;
    END
  END b_d[284]
  PIN b_d[285]
    DIRECTION OUTPUT ;
    USE SIGNAL ;
    PORT
      LAYER M5 ;
        RECT  27.36 0 27.384 0.084 ;
    END
  END b_d[285]
  PIN b_d[286]
    DIRECTION OUTPUT ;
    USE SIGNAL ;
    PORT
      LAYER M5 ;
        RECT  27.408 0 27.432 0.084 ;
    END
  END b_d[286]
  PIN b_d[287]
    DIRECTION OUTPUT ;
    USE SIGNAL ;
    PORT
      LAYER M5 ;
        RECT  27.456 0 27.48 0.084 ;
    END
  END b_d[287]
  PIN b_d[288]
    DIRECTION OUTPUT ;
    USE SIGNAL ;
    PORT
      LAYER M5 ;
        RECT  27.504 0 27.528 0.084 ;
    END
  END b_d[288]
  PIN b_d[289]
    DIRECTION OUTPUT ;
    USE SIGNAL ;
    PORT
      LAYER M5 ;
        RECT  27.552 0 27.576 0.084 ;
    END
  END b_d[289]
  PIN b_d[28]
    DIRECTION OUTPUT ;
    USE SIGNAL ;
    PORT
      LAYER M5 ;
        RECT  15.024 0 15.048 0.084 ;
    END
  END b_d[28]
  PIN b_d[290]
    DIRECTION OUTPUT ;
    USE SIGNAL ;
    PORT
      LAYER M5 ;
        RECT  27.6 0 27.624 0.084 ;
    END
  END b_d[290]
  PIN b_d[291]
    DIRECTION OUTPUT ;
    USE SIGNAL ;
    PORT
      LAYER M5 ;
        RECT  27.648 0 27.672 0.084 ;
    END
  END b_d[291]
  PIN b_d[292]
    DIRECTION OUTPUT ;
    USE SIGNAL ;
    PORT
      LAYER M5 ;
        RECT  27.696 0 27.72 0.084 ;
    END
  END b_d[292]
  PIN b_d[293]
    DIRECTION OUTPUT ;
    USE SIGNAL ;
    PORT
      LAYER M5 ;
        RECT  27.744 0 27.768 0.084 ;
    END
  END b_d[293]
  PIN b_d[294]
    DIRECTION OUTPUT ;
    USE SIGNAL ;
    PORT
      LAYER M5 ;
        RECT  27.792 0 27.816 0.084 ;
    END
  END b_d[294]
  PIN b_d[295]
    DIRECTION OUTPUT ;
    USE SIGNAL ;
    PORT
      LAYER M5 ;
        RECT  27.84 0 27.864 0.084 ;
    END
  END b_d[295]
  PIN b_d[296]
    DIRECTION OUTPUT ;
    USE SIGNAL ;
    PORT
      LAYER M5 ;
        RECT  27.888 0 27.912 0.084 ;
    END
  END b_d[296]
  PIN b_d[297]
    DIRECTION OUTPUT ;
    USE SIGNAL ;
    PORT
      LAYER M5 ;
        RECT  27.936 0 27.96 0.084 ;
    END
  END b_d[297]
  PIN b_d[298]
    DIRECTION OUTPUT ;
    USE SIGNAL ;
    PORT
      LAYER M5 ;
        RECT  27.984 0 28.008 0.084 ;
    END
  END b_d[298]
  PIN b_d[299]
    DIRECTION OUTPUT ;
    USE SIGNAL ;
    PORT
      LAYER M5 ;
        RECT  28.032 0 28.056 0.084 ;
    END
  END b_d[299]
  PIN b_d[29]
    DIRECTION OUTPUT ;
    USE SIGNAL ;
    PORT
      LAYER M5 ;
        RECT  15.072 0 15.096 0.084 ;
    END
  END b_d[29]
  PIN b_d[2]
    DIRECTION OUTPUT ;
    USE SIGNAL ;
    PORT
      LAYER M5 ;
        RECT  13.776 0 13.8 0.084 ;
    END
  END b_d[2]
  PIN b_d[300]
    DIRECTION OUTPUT ;
    USE SIGNAL ;
    PORT
      LAYER M5 ;
        RECT  28.08 0 28.104 0.084 ;
    END
  END b_d[300]
  PIN b_d[301]
    DIRECTION OUTPUT ;
    USE SIGNAL ;
    PORT
      LAYER M5 ;
        RECT  28.128 0 28.152 0.084 ;
    END
  END b_d[301]
  PIN b_d[302]
    DIRECTION OUTPUT ;
    USE SIGNAL ;
    PORT
      LAYER M5 ;
        RECT  28.176 0 28.2 0.084 ;
    END
  END b_d[302]
  PIN b_d[303]
    DIRECTION OUTPUT ;
    USE SIGNAL ;
    PORT
      LAYER M5 ;
        RECT  28.224 0 28.248 0.084 ;
    END
  END b_d[303]
  PIN b_d[304]
    DIRECTION OUTPUT ;
    USE SIGNAL ;
    PORT
      LAYER M5 ;
        RECT  28.272 0 28.296 0.084 ;
    END
  END b_d[304]
  PIN b_d[305]
    DIRECTION OUTPUT ;
    USE SIGNAL ;
    PORT
      LAYER M5 ;
        RECT  28.32 0 28.344 0.084 ;
    END
  END b_d[305]
  PIN b_d[306]
    DIRECTION OUTPUT ;
    USE SIGNAL ;
    PORT
      LAYER M5 ;
        RECT  28.368 0 28.392 0.084 ;
    END
  END b_d[306]
  PIN b_d[307]
    DIRECTION OUTPUT ;
    USE SIGNAL ;
    PORT
      LAYER M5 ;
        RECT  28.416 0 28.44 0.084 ;
    END
  END b_d[307]
  PIN b_d[308]
    DIRECTION OUTPUT ;
    USE SIGNAL ;
    PORT
      LAYER M5 ;
        RECT  28.464 0 28.488 0.084 ;
    END
  END b_d[308]
  PIN b_d[309]
    DIRECTION OUTPUT ;
    USE SIGNAL ;
    PORT
      LAYER M5 ;
        RECT  28.512 0 28.536 0.084 ;
    END
  END b_d[309]
  PIN b_d[30]
    DIRECTION OUTPUT ;
    USE SIGNAL ;
    PORT
      LAYER M5 ;
        RECT  15.12 0 15.144 0.084 ;
    END
  END b_d[30]
  PIN b_d[310]
    DIRECTION OUTPUT ;
    USE SIGNAL ;
    PORT
      LAYER M5 ;
        RECT  28.56 0 28.584 0.084 ;
    END
  END b_d[310]
  PIN b_d[311]
    DIRECTION OUTPUT ;
    USE SIGNAL ;
    PORT
      LAYER M5 ;
        RECT  28.608 0 28.632 0.084 ;
    END
  END b_d[311]
  PIN b_d[312]
    DIRECTION OUTPUT ;
    USE SIGNAL ;
    PORT
      LAYER M5 ;
        RECT  28.656 0 28.68 0.084 ;
    END
  END b_d[312]
  PIN b_d[313]
    DIRECTION OUTPUT ;
    USE SIGNAL ;
    PORT
      LAYER M5 ;
        RECT  28.704 0 28.728 0.084 ;
    END
  END b_d[313]
  PIN b_d[314]
    DIRECTION OUTPUT ;
    USE SIGNAL ;
    PORT
      LAYER M5 ;
        RECT  28.752 0 28.776 0.084 ;
    END
  END b_d[314]
  PIN b_d[315]
    DIRECTION OUTPUT ;
    USE SIGNAL ;
    PORT
      LAYER M5 ;
        RECT  28.8 0 28.824 0.084 ;
    END
  END b_d[315]
  PIN b_d[316]
    DIRECTION OUTPUT ;
    USE SIGNAL ;
    PORT
      LAYER M5 ;
        RECT  28.848 0 28.872 0.084 ;
    END
  END b_d[316]
  PIN b_d[317]
    DIRECTION OUTPUT ;
    USE SIGNAL ;
    PORT
      LAYER M5 ;
        RECT  28.896 0 28.92 0.084 ;
    END
  END b_d[317]
  PIN b_d[318]
    DIRECTION OUTPUT ;
    USE SIGNAL ;
    PORT
      LAYER M5 ;
        RECT  28.944 0 28.968 0.084 ;
    END
  END b_d[318]
  PIN b_d[319]
    DIRECTION OUTPUT ;
    USE SIGNAL ;
    PORT
      LAYER M5 ;
        RECT  28.992 0 29.016 0.084 ;
    END
  END b_d[319]
  PIN b_d[31]
    DIRECTION OUTPUT ;
    USE SIGNAL ;
    PORT
      LAYER M5 ;
        RECT  15.168 0 15.192 0.084 ;
    END
  END b_d[31]
  PIN b_d[320]
    DIRECTION OUTPUT ;
    USE SIGNAL ;
    PORT
      LAYER M5 ;
        RECT  29.04 0 29.064 0.084 ;
    END
  END b_d[320]
  PIN b_d[321]
    DIRECTION OUTPUT ;
    USE SIGNAL ;
    PORT
      LAYER M5 ;
        RECT  29.088 0 29.112 0.084 ;
    END
  END b_d[321]
  PIN b_d[322]
    DIRECTION OUTPUT ;
    USE SIGNAL ;
    PORT
      LAYER M5 ;
        RECT  29.136 0 29.16 0.084 ;
    END
  END b_d[322]
  PIN b_d[323]
    DIRECTION OUTPUT ;
    USE SIGNAL ;
    PORT
      LAYER M5 ;
        RECT  29.184 0 29.208 0.084 ;
    END
  END b_d[323]
  PIN b_d[324]
    DIRECTION OUTPUT ;
    USE SIGNAL ;
    PORT
      LAYER M5 ;
        RECT  29.232 0 29.256 0.084 ;
    END
  END b_d[324]
  PIN b_d[325]
    DIRECTION OUTPUT ;
    USE SIGNAL ;
    PORT
      LAYER M5 ;
        RECT  29.28 0 29.304 0.084 ;
    END
  END b_d[325]
  PIN b_d[326]
    DIRECTION OUTPUT ;
    USE SIGNAL ;
    PORT
      LAYER M5 ;
        RECT  29.328 0 29.352 0.084 ;
    END
  END b_d[326]
  PIN b_d[327]
    DIRECTION OUTPUT ;
    USE SIGNAL ;
    PORT
      LAYER M5 ;
        RECT  29.376 0 29.4 0.084 ;
    END
  END b_d[327]
  PIN b_d[328]
    DIRECTION OUTPUT ;
    USE SIGNAL ;
    PORT
      LAYER M5 ;
        RECT  29.424 0 29.448 0.084 ;
    END
  END b_d[328]
  PIN b_d[329]
    DIRECTION OUTPUT ;
    USE SIGNAL ;
    PORT
      LAYER M5 ;
        RECT  29.472 0 29.496 0.084 ;
    END
  END b_d[329]
  PIN b_d[32]
    DIRECTION OUTPUT ;
    USE SIGNAL ;
    PORT
      LAYER M5 ;
        RECT  15.216 0 15.24 0.084 ;
    END
  END b_d[32]
  PIN b_d[330]
    DIRECTION OUTPUT ;
    USE SIGNAL ;
    PORT
      LAYER M5 ;
        RECT  29.52 0 29.544 0.084 ;
    END
  END b_d[330]
  PIN b_d[331]
    DIRECTION OUTPUT ;
    USE SIGNAL ;
    PORT
      LAYER M5 ;
        RECT  29.568 0 29.592 0.084 ;
    END
  END b_d[331]
  PIN b_d[332]
    DIRECTION OUTPUT ;
    USE SIGNAL ;
    PORT
      LAYER M5 ;
        RECT  29.616 0 29.64 0.084 ;
    END
  END b_d[332]
  PIN b_d[333]
    DIRECTION OUTPUT ;
    USE SIGNAL ;
    PORT
      LAYER M5 ;
        RECT  29.664 0 29.688 0.084 ;
    END
  END b_d[333]
  PIN b_d[334]
    DIRECTION OUTPUT ;
    USE SIGNAL ;
    PORT
      LAYER M5 ;
        RECT  29.712 0 29.736 0.084 ;
    END
  END b_d[334]
  PIN b_d[335]
    DIRECTION OUTPUT ;
    USE SIGNAL ;
    PORT
      LAYER M5 ;
        RECT  29.76 0 29.784 0.084 ;
    END
  END b_d[335]
  PIN b_d[336]
    DIRECTION OUTPUT ;
    USE SIGNAL ;
    PORT
      LAYER M5 ;
        RECT  29.808 0 29.832 0.084 ;
    END
  END b_d[336]
  PIN b_d[337]
    DIRECTION OUTPUT ;
    USE SIGNAL ;
    PORT
      LAYER M5 ;
        RECT  29.856 0 29.88 0.084 ;
    END
  END b_d[337]
  PIN b_d[338]
    DIRECTION OUTPUT ;
    USE SIGNAL ;
    PORT
      LAYER M5 ;
        RECT  29.904 0 29.928 0.084 ;
    END
  END b_d[338]
  PIN b_d[339]
    DIRECTION OUTPUT ;
    USE SIGNAL ;
    PORT
      LAYER M5 ;
        RECT  29.952 0 29.976 0.084 ;
    END
  END b_d[339]
  PIN b_d[33]
    DIRECTION OUTPUT ;
    USE SIGNAL ;
    PORT
      LAYER M5 ;
        RECT  15.264 0 15.288 0.084 ;
    END
  END b_d[33]
  PIN b_d[340]
    DIRECTION OUTPUT ;
    USE SIGNAL ;
    PORT
      LAYER M5 ;
        RECT  30 0 30.024 0.084 ;
    END
  END b_d[340]
  PIN b_d[341]
    DIRECTION OUTPUT ;
    USE SIGNAL ;
    PORT
      LAYER M5 ;
        RECT  30.048 0 30.072 0.084 ;
    END
  END b_d[341]
  PIN b_d[342]
    DIRECTION OUTPUT ;
    USE SIGNAL ;
    PORT
      LAYER M5 ;
        RECT  30.096 0 30.12 0.084 ;
    END
  END b_d[342]
  PIN b_d[343]
    DIRECTION OUTPUT ;
    USE SIGNAL ;
    PORT
      LAYER M5 ;
        RECT  30.144 0 30.168 0.084 ;
    END
  END b_d[343]
  PIN b_d[344]
    DIRECTION OUTPUT ;
    USE SIGNAL ;
    PORT
      LAYER M5 ;
        RECT  30.192 0 30.216 0.084 ;
    END
  END b_d[344]
  PIN b_d[345]
    DIRECTION OUTPUT ;
    USE SIGNAL ;
    PORT
      LAYER M5 ;
        RECT  30.24 0 30.264 0.084 ;
    END
  END b_d[345]
  PIN b_d[346]
    DIRECTION OUTPUT ;
    USE SIGNAL ;
    PORT
      LAYER M5 ;
        RECT  30.288 0 30.312 0.084 ;
    END
  END b_d[346]
  PIN b_d[347]
    DIRECTION OUTPUT ;
    USE SIGNAL ;
    PORT
      LAYER M5 ;
        RECT  30.336 0 30.36 0.084 ;
    END
  END b_d[347]
  PIN b_d[348]
    DIRECTION OUTPUT ;
    USE SIGNAL ;
    PORT
      LAYER M5 ;
        RECT  30.384 0 30.408 0.084 ;
    END
  END b_d[348]
  PIN b_d[349]
    DIRECTION OUTPUT ;
    USE SIGNAL ;
    PORT
      LAYER M5 ;
        RECT  30.432 0 30.456 0.084 ;
    END
  END b_d[349]
  PIN b_d[34]
    DIRECTION OUTPUT ;
    USE SIGNAL ;
    PORT
      LAYER M5 ;
        RECT  15.312 0 15.336 0.084 ;
    END
  END b_d[34]
  PIN b_d[350]
    DIRECTION OUTPUT ;
    USE SIGNAL ;
    PORT
      LAYER M5 ;
        RECT  30.48 0 30.504 0.084 ;
    END
  END b_d[350]
  PIN b_d[351]
    DIRECTION OUTPUT ;
    USE SIGNAL ;
    PORT
      LAYER M5 ;
        RECT  30.528 0 30.552 0.084 ;
    END
  END b_d[351]
  PIN b_d[352]
    DIRECTION OUTPUT ;
    USE SIGNAL ;
    PORT
      LAYER M5 ;
        RECT  30.576 0 30.6 0.084 ;
    END
  END b_d[352]
  PIN b_d[353]
    DIRECTION OUTPUT ;
    USE SIGNAL ;
    PORT
      LAYER M5 ;
        RECT  30.624 0 30.648 0.084 ;
    END
  END b_d[353]
  PIN b_d[354]
    DIRECTION OUTPUT ;
    USE SIGNAL ;
    PORT
      LAYER M5 ;
        RECT  30.672 0 30.696 0.084 ;
    END
  END b_d[354]
  PIN b_d[355]
    DIRECTION OUTPUT ;
    USE SIGNAL ;
    PORT
      LAYER M5 ;
        RECT  30.72 0 30.744 0.084 ;
    END
  END b_d[355]
  PIN b_d[356]
    DIRECTION OUTPUT ;
    USE SIGNAL ;
    PORT
      LAYER M5 ;
        RECT  30.768 0 30.792 0.084 ;
    END
  END b_d[356]
  PIN b_d[357]
    DIRECTION OUTPUT ;
    USE SIGNAL ;
    PORT
      LAYER M5 ;
        RECT  30.816 0 30.84 0.084 ;
    END
  END b_d[357]
  PIN b_d[358]
    DIRECTION OUTPUT ;
    USE SIGNAL ;
    PORT
      LAYER M5 ;
        RECT  30.864 0 30.888 0.084 ;
    END
  END b_d[358]
  PIN b_d[359]
    DIRECTION OUTPUT ;
    USE SIGNAL ;
    PORT
      LAYER M5 ;
        RECT  30.912 0 30.936 0.084 ;
    END
  END b_d[359]
  PIN b_d[35]
    DIRECTION OUTPUT ;
    USE SIGNAL ;
    PORT
      LAYER M5 ;
        RECT  15.36 0 15.384 0.084 ;
    END
  END b_d[35]
  PIN b_d[360]
    DIRECTION OUTPUT ;
    USE SIGNAL ;
    PORT
      LAYER M5 ;
        RECT  30.96 0 30.984 0.084 ;
    END
  END b_d[360]
  PIN b_d[361]
    DIRECTION OUTPUT ;
    USE SIGNAL ;
    PORT
      LAYER M5 ;
        RECT  31.008 0 31.032 0.084 ;
    END
  END b_d[361]
  PIN b_d[362]
    DIRECTION OUTPUT ;
    USE SIGNAL ;
    PORT
      LAYER M5 ;
        RECT  31.056 0 31.08 0.084 ;
    END
  END b_d[362]
  PIN b_d[363]
    DIRECTION OUTPUT ;
    USE SIGNAL ;
    PORT
      LAYER M5 ;
        RECT  31.104 0 31.128 0.084 ;
    END
  END b_d[363]
  PIN b_d[364]
    DIRECTION OUTPUT ;
    USE SIGNAL ;
    PORT
      LAYER M5 ;
        RECT  31.152 0 31.176 0.084 ;
    END
  END b_d[364]
  PIN b_d[365]
    DIRECTION OUTPUT ;
    USE SIGNAL ;
    PORT
      LAYER M5 ;
        RECT  31.2 0 31.224 0.084 ;
    END
  END b_d[365]
  PIN b_d[366]
    DIRECTION OUTPUT ;
    USE SIGNAL ;
    PORT
      LAYER M5 ;
        RECT  31.248 0 31.272 0.084 ;
    END
  END b_d[366]
  PIN b_d[367]
    DIRECTION OUTPUT ;
    USE SIGNAL ;
    PORT
      LAYER M5 ;
        RECT  31.296 0 31.32 0.084 ;
    END
  END b_d[367]
  PIN b_d[368]
    DIRECTION OUTPUT ;
    USE SIGNAL ;
    PORT
      LAYER M5 ;
        RECT  31.344 0 31.368 0.084 ;
    END
  END b_d[368]
  PIN b_d[369]
    DIRECTION OUTPUT ;
    USE SIGNAL ;
    PORT
      LAYER M5 ;
        RECT  31.392 0 31.416 0.084 ;
    END
  END b_d[369]
  PIN b_d[36]
    DIRECTION OUTPUT ;
    USE SIGNAL ;
    PORT
      LAYER M5 ;
        RECT  15.408 0 15.432 0.084 ;
    END
  END b_d[36]
  PIN b_d[370]
    DIRECTION OUTPUT ;
    USE SIGNAL ;
    PORT
      LAYER M5 ;
        RECT  31.44 0 31.464 0.084 ;
    END
  END b_d[370]
  PIN b_d[371]
    DIRECTION OUTPUT ;
    USE SIGNAL ;
    PORT
      LAYER M5 ;
        RECT  31.488 0 31.512 0.084 ;
    END
  END b_d[371]
  PIN b_d[372]
    DIRECTION OUTPUT ;
    USE SIGNAL ;
    PORT
      LAYER M5 ;
        RECT  31.536 0 31.56 0.084 ;
    END
  END b_d[372]
  PIN b_d[373]
    DIRECTION OUTPUT ;
    USE SIGNAL ;
    PORT
      LAYER M5 ;
        RECT  31.584 0 31.608 0.084 ;
    END
  END b_d[373]
  PIN b_d[374]
    DIRECTION OUTPUT ;
    USE SIGNAL ;
    PORT
      LAYER M5 ;
        RECT  31.632 0 31.656 0.084 ;
    END
  END b_d[374]
  PIN b_d[375]
    DIRECTION OUTPUT ;
    USE SIGNAL ;
    PORT
      LAYER M5 ;
        RECT  31.68 0 31.704 0.084 ;
    END
  END b_d[375]
  PIN b_d[376]
    DIRECTION OUTPUT ;
    USE SIGNAL ;
    PORT
      LAYER M5 ;
        RECT  31.728 0 31.752 0.084 ;
    END
  END b_d[376]
  PIN b_d[377]
    DIRECTION OUTPUT ;
    USE SIGNAL ;
    PORT
      LAYER M5 ;
        RECT  31.776 0 31.8 0.084 ;
    END
  END b_d[377]
  PIN b_d[378]
    DIRECTION OUTPUT ;
    USE SIGNAL ;
    PORT
      LAYER M5 ;
        RECT  31.824 0 31.848 0.084 ;
    END
  END b_d[378]
  PIN b_d[379]
    DIRECTION OUTPUT ;
    USE SIGNAL ;
    PORT
      LAYER M5 ;
        RECT  31.872 0 31.896 0.084 ;
    END
  END b_d[379]
  PIN b_d[37]
    DIRECTION OUTPUT ;
    USE SIGNAL ;
    PORT
      LAYER M5 ;
        RECT  15.456 0 15.48 0.084 ;
    END
  END b_d[37]
  PIN b_d[380]
    DIRECTION OUTPUT ;
    USE SIGNAL ;
    PORT
      LAYER M5 ;
        RECT  31.92 0 31.944 0.084 ;
    END
  END b_d[380]
  PIN b_d[381]
    DIRECTION OUTPUT ;
    USE SIGNAL ;
    PORT
      LAYER M5 ;
        RECT  31.968 0 31.992 0.084 ;
    END
  END b_d[381]
  PIN b_d[382]
    DIRECTION OUTPUT ;
    USE SIGNAL ;
    PORT
      LAYER M5 ;
        RECT  32.016 0 32.04 0.084 ;
    END
  END b_d[382]
  PIN b_d[383]
    DIRECTION OUTPUT ;
    USE SIGNAL ;
    PORT
      LAYER M5 ;
        RECT  32.064 0 32.088 0.084 ;
    END
  END b_d[383]
  PIN b_d[384]
    DIRECTION OUTPUT ;
    USE SIGNAL ;
    PORT
      LAYER M5 ;
        RECT  32.112 0 32.136 0.084 ;
    END
  END b_d[384]
  PIN b_d[385]
    DIRECTION OUTPUT ;
    USE SIGNAL ;
    PORT
      LAYER M5 ;
        RECT  32.16 0 32.184 0.084 ;
    END
  END b_d[385]
  PIN b_d[386]
    DIRECTION OUTPUT ;
    USE SIGNAL ;
    PORT
      LAYER M5 ;
        RECT  32.208 0 32.232 0.084 ;
    END
  END b_d[386]
  PIN b_d[387]
    DIRECTION OUTPUT ;
    USE SIGNAL ;
    PORT
      LAYER M5 ;
        RECT  32.256 0 32.28 0.084 ;
    END
  END b_d[387]
  PIN b_d[388]
    DIRECTION OUTPUT ;
    USE SIGNAL ;
    PORT
      LAYER M5 ;
        RECT  32.304 0 32.328 0.084 ;
    END
  END b_d[388]
  PIN b_d[389]
    DIRECTION OUTPUT ;
    USE SIGNAL ;
    PORT
      LAYER M5 ;
        RECT  32.352 0 32.376 0.084 ;
    END
  END b_d[389]
  PIN b_d[38]
    DIRECTION OUTPUT ;
    USE SIGNAL ;
    PORT
      LAYER M5 ;
        RECT  15.504 0 15.528 0.084 ;
    END
  END b_d[38]
  PIN b_d[390]
    DIRECTION OUTPUT ;
    USE SIGNAL ;
    PORT
      LAYER M5 ;
        RECT  32.4 0 32.424 0.084 ;
    END
  END b_d[390]
  PIN b_d[391]
    DIRECTION OUTPUT ;
    USE SIGNAL ;
    PORT
      LAYER M5 ;
        RECT  32.448 0 32.472 0.084 ;
    END
  END b_d[391]
  PIN b_d[392]
    DIRECTION OUTPUT ;
    USE SIGNAL ;
    PORT
      LAYER M5 ;
        RECT  32.496 0 32.52 0.084 ;
    END
  END b_d[392]
  PIN b_d[393]
    DIRECTION OUTPUT ;
    USE SIGNAL ;
    PORT
      LAYER M5 ;
        RECT  32.544 0 32.568 0.084 ;
    END
  END b_d[393]
  PIN b_d[394]
    DIRECTION OUTPUT ;
    USE SIGNAL ;
    PORT
      LAYER M5 ;
        RECT  32.592 0 32.616 0.084 ;
    END
  END b_d[394]
  PIN b_d[395]
    DIRECTION OUTPUT ;
    USE SIGNAL ;
    PORT
      LAYER M5 ;
        RECT  32.64 0 32.664 0.084 ;
    END
  END b_d[395]
  PIN b_d[396]
    DIRECTION OUTPUT ;
    USE SIGNAL ;
    PORT
      LAYER M5 ;
        RECT  32.688 0 32.712 0.084 ;
    END
  END b_d[396]
  PIN b_d[397]
    DIRECTION OUTPUT ;
    USE SIGNAL ;
    PORT
      LAYER M5 ;
        RECT  32.736 0 32.76 0.084 ;
    END
  END b_d[397]
  PIN b_d[398]
    DIRECTION OUTPUT ;
    USE SIGNAL ;
    PORT
      LAYER M5 ;
        RECT  32.784 0 32.808 0.084 ;
    END
  END b_d[398]
  PIN b_d[399]
    DIRECTION OUTPUT ;
    USE SIGNAL ;
    PORT
      LAYER M5 ;
        RECT  32.832 0 32.856 0.084 ;
    END
  END b_d[399]
  PIN b_d[39]
    DIRECTION OUTPUT ;
    USE SIGNAL ;
    PORT
      LAYER M5 ;
        RECT  15.552 0 15.576 0.084 ;
    END
  END b_d[39]
  PIN b_d[3]
    DIRECTION OUTPUT ;
    USE SIGNAL ;
    PORT
      LAYER M5 ;
        RECT  13.824 0 13.848 0.084 ;
    END
  END b_d[3]
  PIN b_d[400]
    DIRECTION OUTPUT ;
    USE SIGNAL ;
    PORT
      LAYER M5 ;
        RECT  32.88 0 32.904 0.084 ;
    END
  END b_d[400]
  PIN b_d[401]
    DIRECTION OUTPUT ;
    USE SIGNAL ;
    PORT
      LAYER M5 ;
        RECT  32.928 0 32.952 0.084 ;
    END
  END b_d[401]
  PIN b_d[402]
    DIRECTION OUTPUT ;
    USE SIGNAL ;
    PORT
      LAYER M5 ;
        RECT  32.976 0 33 0.084 ;
    END
  END b_d[402]
  PIN b_d[403]
    DIRECTION OUTPUT ;
    USE SIGNAL ;
    PORT
      LAYER M5 ;
        RECT  33.024 0 33.048 0.084 ;
    END
  END b_d[403]
  PIN b_d[404]
    DIRECTION OUTPUT ;
    USE SIGNAL ;
    PORT
      LAYER M5 ;
        RECT  33.072 0 33.096 0.084 ;
    END
  END b_d[404]
  PIN b_d[405]
    DIRECTION OUTPUT ;
    USE SIGNAL ;
    PORT
      LAYER M5 ;
        RECT  33.12 0 33.144 0.084 ;
    END
  END b_d[405]
  PIN b_d[406]
    DIRECTION OUTPUT ;
    USE SIGNAL ;
    PORT
      LAYER M5 ;
        RECT  33.168 0 33.192 0.084 ;
    END
  END b_d[406]
  PIN b_d[407]
    DIRECTION OUTPUT ;
    USE SIGNAL ;
    PORT
      LAYER M5 ;
        RECT  33.216 0 33.24 0.084 ;
    END
  END b_d[407]
  PIN b_d[408]
    DIRECTION OUTPUT ;
    USE SIGNAL ;
    PORT
      LAYER M5 ;
        RECT  33.264 0 33.288 0.084 ;
    END
  END b_d[408]
  PIN b_d[409]
    DIRECTION OUTPUT ;
    USE SIGNAL ;
    PORT
      LAYER M5 ;
        RECT  33.312 0 33.336 0.084 ;
    END
  END b_d[409]
  PIN b_d[40]
    DIRECTION OUTPUT ;
    USE SIGNAL ;
    PORT
      LAYER M5 ;
        RECT  15.6 0 15.624 0.084 ;
    END
  END b_d[40]
  PIN b_d[410]
    DIRECTION OUTPUT ;
    USE SIGNAL ;
    PORT
      LAYER M5 ;
        RECT  33.36 0 33.384 0.084 ;
    END
  END b_d[410]
  PIN b_d[411]
    DIRECTION OUTPUT ;
    USE SIGNAL ;
    PORT
      LAYER M5 ;
        RECT  33.408 0 33.432 0.084 ;
    END
  END b_d[411]
  PIN b_d[412]
    DIRECTION OUTPUT ;
    USE SIGNAL ;
    PORT
      LAYER M5 ;
        RECT  33.456 0 33.48 0.084 ;
    END
  END b_d[412]
  PIN b_d[413]
    DIRECTION OUTPUT ;
    USE SIGNAL ;
    PORT
      LAYER M5 ;
        RECT  33.504 0 33.528 0.084 ;
    END
  END b_d[413]
  PIN b_d[414]
    DIRECTION OUTPUT ;
    USE SIGNAL ;
    PORT
      LAYER M5 ;
        RECT  33.552 0 33.576 0.084 ;
    END
  END b_d[414]
  PIN b_d[415]
    DIRECTION OUTPUT ;
    USE SIGNAL ;
    PORT
      LAYER M5 ;
        RECT  33.6 0 33.624 0.084 ;
    END
  END b_d[415]
  PIN b_d[416]
    DIRECTION OUTPUT ;
    USE SIGNAL ;
    PORT
      LAYER M5 ;
        RECT  33.648 0 33.672 0.084 ;
    END
  END b_d[416]
  PIN b_d[417]
    DIRECTION OUTPUT ;
    USE SIGNAL ;
    PORT
      LAYER M5 ;
        RECT  33.696 0 33.72 0.084 ;
    END
  END b_d[417]
  PIN b_d[418]
    DIRECTION OUTPUT ;
    USE SIGNAL ;
    PORT
      LAYER M5 ;
        RECT  33.744 0 33.768 0.084 ;
    END
  END b_d[418]
  PIN b_d[419]
    DIRECTION OUTPUT ;
    USE SIGNAL ;
    PORT
      LAYER M5 ;
        RECT  33.792 0 33.816 0.084 ;
    END
  END b_d[419]
  PIN b_d[41]
    DIRECTION OUTPUT ;
    USE SIGNAL ;
    PORT
      LAYER M5 ;
        RECT  15.648 0 15.672 0.084 ;
    END
  END b_d[41]
  PIN b_d[420]
    DIRECTION OUTPUT ;
    USE SIGNAL ;
    PORT
      LAYER M5 ;
        RECT  33.84 0 33.864 0.084 ;
    END
  END b_d[420]
  PIN b_d[421]
    DIRECTION OUTPUT ;
    USE SIGNAL ;
    PORT
      LAYER M5 ;
        RECT  33.888 0 33.912 0.084 ;
    END
  END b_d[421]
  PIN b_d[422]
    DIRECTION OUTPUT ;
    USE SIGNAL ;
    PORT
      LAYER M5 ;
        RECT  33.936 0 33.96 0.084 ;
    END
  END b_d[422]
  PIN b_d[423]
    DIRECTION OUTPUT ;
    USE SIGNAL ;
    PORT
      LAYER M5 ;
        RECT  33.984 0 34.008 0.084 ;
    END
  END b_d[423]
  PIN b_d[424]
    DIRECTION OUTPUT ;
    USE SIGNAL ;
    PORT
      LAYER M5 ;
        RECT  34.032 0 34.056 0.084 ;
    END
  END b_d[424]
  PIN b_d[425]
    DIRECTION OUTPUT ;
    USE SIGNAL ;
    PORT
      LAYER M5 ;
        RECT  34.08 0 34.104 0.084 ;
    END
  END b_d[425]
  PIN b_d[426]
    DIRECTION OUTPUT ;
    USE SIGNAL ;
    PORT
      LAYER M5 ;
        RECT  34.128 0 34.152 0.084 ;
    END
  END b_d[426]
  PIN b_d[427]
    DIRECTION OUTPUT ;
    USE SIGNAL ;
    PORT
      LAYER M5 ;
        RECT  34.176 0 34.2 0.084 ;
    END
  END b_d[427]
  PIN b_d[428]
    DIRECTION OUTPUT ;
    USE SIGNAL ;
    PORT
      LAYER M5 ;
        RECT  34.224 0 34.248 0.084 ;
    END
  END b_d[428]
  PIN b_d[429]
    DIRECTION OUTPUT ;
    USE SIGNAL ;
    PORT
      LAYER M5 ;
        RECT  34.272 0 34.296 0.084 ;
    END
  END b_d[429]
  PIN b_d[42]
    DIRECTION OUTPUT ;
    USE SIGNAL ;
    PORT
      LAYER M5 ;
        RECT  15.696 0 15.72 0.084 ;
    END
  END b_d[42]
  PIN b_d[430]
    DIRECTION OUTPUT ;
    USE SIGNAL ;
    PORT
      LAYER M5 ;
        RECT  34.32 0 34.344 0.084 ;
    END
  END b_d[430]
  PIN b_d[431]
    DIRECTION OUTPUT ;
    USE SIGNAL ;
    PORT
      LAYER M5 ;
        RECT  34.368 0 34.392 0.084 ;
    END
  END b_d[431]
  PIN b_d[432]
    DIRECTION OUTPUT ;
    USE SIGNAL ;
    PORT
      LAYER M5 ;
        RECT  34.416 0 34.44 0.084 ;
    END
  END b_d[432]
  PIN b_d[433]
    DIRECTION OUTPUT ;
    USE SIGNAL ;
    PORT
      LAYER M5 ;
        RECT  34.464 0 34.488 0.084 ;
    END
  END b_d[433]
  PIN b_d[434]
    DIRECTION OUTPUT ;
    USE SIGNAL ;
    PORT
      LAYER M5 ;
        RECT  34.512 0 34.536 0.084 ;
    END
  END b_d[434]
  PIN b_d[435]
    DIRECTION OUTPUT ;
    USE SIGNAL ;
    PORT
      LAYER M5 ;
        RECT  34.56 0 34.584 0.084 ;
    END
  END b_d[435]
  PIN b_d[436]
    DIRECTION OUTPUT ;
    USE SIGNAL ;
    PORT
      LAYER M5 ;
        RECT  34.608 0 34.632 0.084 ;
    END
  END b_d[436]
  PIN b_d[437]
    DIRECTION OUTPUT ;
    USE SIGNAL ;
    PORT
      LAYER M5 ;
        RECT  34.656 0 34.68 0.084 ;
    END
  END b_d[437]
  PIN b_d[438]
    DIRECTION OUTPUT ;
    USE SIGNAL ;
    PORT
      LAYER M5 ;
        RECT  34.704 0 34.728 0.084 ;
    END
  END b_d[438]
  PIN b_d[439]
    DIRECTION OUTPUT ;
    USE SIGNAL ;
    PORT
      LAYER M5 ;
        RECT  34.752 0 34.776 0.084 ;
    END
  END b_d[439]
  PIN b_d[43]
    DIRECTION OUTPUT ;
    USE SIGNAL ;
    PORT
      LAYER M5 ;
        RECT  15.744 0 15.768 0.084 ;
    END
  END b_d[43]
  PIN b_d[440]
    DIRECTION OUTPUT ;
    USE SIGNAL ;
    PORT
      LAYER M5 ;
        RECT  34.8 0 34.824 0.084 ;
    END
  END b_d[440]
  PIN b_d[441]
    DIRECTION OUTPUT ;
    USE SIGNAL ;
    PORT
      LAYER M5 ;
        RECT  34.848 0 34.872 0.084 ;
    END
  END b_d[441]
  PIN b_d[442]
    DIRECTION OUTPUT ;
    USE SIGNAL ;
    PORT
      LAYER M5 ;
        RECT  34.896 0 34.92 0.084 ;
    END
  END b_d[442]
  PIN b_d[443]
    DIRECTION OUTPUT ;
    USE SIGNAL ;
    PORT
      LAYER M5 ;
        RECT  34.944 0 34.968 0.084 ;
    END
  END b_d[443]
  PIN b_d[444]
    DIRECTION OUTPUT ;
    USE SIGNAL ;
    PORT
      LAYER M5 ;
        RECT  34.992 0 35.016 0.084 ;
    END
  END b_d[444]
  PIN b_d[445]
    DIRECTION OUTPUT ;
    USE SIGNAL ;
    PORT
      LAYER M5 ;
        RECT  35.04 0 35.064 0.084 ;
    END
  END b_d[445]
  PIN b_d[446]
    DIRECTION OUTPUT ;
    USE SIGNAL ;
    PORT
      LAYER M5 ;
        RECT  35.088 0 35.112 0.084 ;
    END
  END b_d[446]
  PIN b_d[447]
    DIRECTION OUTPUT ;
    USE SIGNAL ;
    PORT
      LAYER M5 ;
        RECT  35.136 0 35.16 0.084 ;
    END
  END b_d[447]
  PIN b_d[448]
    DIRECTION OUTPUT ;
    USE SIGNAL ;
    PORT
      LAYER M5 ;
        RECT  35.184 0 35.208 0.084 ;
    END
  END b_d[448]
  PIN b_d[449]
    DIRECTION OUTPUT ;
    USE SIGNAL ;
    PORT
      LAYER M5 ;
        RECT  35.232 0 35.256 0.084 ;
    END
  END b_d[449]
  PIN b_d[44]
    DIRECTION OUTPUT ;
    USE SIGNAL ;
    PORT
      LAYER M5 ;
        RECT  15.792 0 15.816 0.084 ;
    END
  END b_d[44]
  PIN b_d[450]
    DIRECTION OUTPUT ;
    USE SIGNAL ;
    PORT
      LAYER M5 ;
        RECT  35.28 0 35.304 0.084 ;
    END
  END b_d[450]
  PIN b_d[451]
    DIRECTION OUTPUT ;
    USE SIGNAL ;
    PORT
      LAYER M5 ;
        RECT  35.328 0 35.352 0.084 ;
    END
  END b_d[451]
  PIN b_d[452]
    DIRECTION OUTPUT ;
    USE SIGNAL ;
    PORT
      LAYER M5 ;
        RECT  35.376 0 35.4 0.084 ;
    END
  END b_d[452]
  PIN b_d[453]
    DIRECTION OUTPUT ;
    USE SIGNAL ;
    PORT
      LAYER M5 ;
        RECT  35.424 0 35.448 0.084 ;
    END
  END b_d[453]
  PIN b_d[454]
    DIRECTION OUTPUT ;
    USE SIGNAL ;
    PORT
      LAYER M5 ;
        RECT  35.472 0 35.496 0.084 ;
    END
  END b_d[454]
  PIN b_d[455]
    DIRECTION OUTPUT ;
    USE SIGNAL ;
    PORT
      LAYER M5 ;
        RECT  35.52 0 35.544 0.084 ;
    END
  END b_d[455]
  PIN b_d[456]
    DIRECTION OUTPUT ;
    USE SIGNAL ;
    PORT
      LAYER M5 ;
        RECT  35.568 0 35.592 0.084 ;
    END
  END b_d[456]
  PIN b_d[457]
    DIRECTION OUTPUT ;
    USE SIGNAL ;
    PORT
      LAYER M5 ;
        RECT  35.616 0 35.64 0.084 ;
    END
  END b_d[457]
  PIN b_d[458]
    DIRECTION OUTPUT ;
    USE SIGNAL ;
    PORT
      LAYER M5 ;
        RECT  35.664 0 35.688 0.084 ;
    END
  END b_d[458]
  PIN b_d[459]
    DIRECTION OUTPUT ;
    USE SIGNAL ;
    PORT
      LAYER M5 ;
        RECT  35.712 0 35.736 0.084 ;
    END
  END b_d[459]
  PIN b_d[45]
    DIRECTION OUTPUT ;
    USE SIGNAL ;
    PORT
      LAYER M5 ;
        RECT  15.84 0 15.864 0.084 ;
    END
  END b_d[45]
  PIN b_d[460]
    DIRECTION OUTPUT ;
    USE SIGNAL ;
    PORT
      LAYER M5 ;
        RECT  35.76 0 35.784 0.084 ;
    END
  END b_d[460]
  PIN b_d[461]
    DIRECTION OUTPUT ;
    USE SIGNAL ;
    PORT
      LAYER M5 ;
        RECT  35.808 0 35.832 0.084 ;
    END
  END b_d[461]
  PIN b_d[462]
    DIRECTION OUTPUT ;
    USE SIGNAL ;
    PORT
      LAYER M5 ;
        RECT  35.856 0 35.88 0.084 ;
    END
  END b_d[462]
  PIN b_d[463]
    DIRECTION OUTPUT ;
    USE SIGNAL ;
    PORT
      LAYER M5 ;
        RECT  35.904 0 35.928 0.084 ;
    END
  END b_d[463]
  PIN b_d[464]
    DIRECTION OUTPUT ;
    USE SIGNAL ;
    PORT
      LAYER M5 ;
        RECT  35.952 0 35.976 0.084 ;
    END
  END b_d[464]
  PIN b_d[465]
    DIRECTION OUTPUT ;
    USE SIGNAL ;
    PORT
      LAYER M5 ;
        RECT  36 0 36.024 0.084 ;
    END
  END b_d[465]
  PIN b_d[466]
    DIRECTION OUTPUT ;
    USE SIGNAL ;
    PORT
      LAYER M5 ;
        RECT  36.048 0 36.072 0.084 ;
    END
  END b_d[466]
  PIN b_d[467]
    DIRECTION OUTPUT ;
    USE SIGNAL ;
    PORT
      LAYER M5 ;
        RECT  36.096 0 36.12 0.084 ;
    END
  END b_d[467]
  PIN b_d[468]
    DIRECTION OUTPUT ;
    USE SIGNAL ;
    PORT
      LAYER M5 ;
        RECT  36.144 0 36.168 0.084 ;
    END
  END b_d[468]
  PIN b_d[469]
    DIRECTION OUTPUT ;
    USE SIGNAL ;
    PORT
      LAYER M5 ;
        RECT  36.192 0 36.216 0.084 ;
    END
  END b_d[469]
  PIN b_d[46]
    DIRECTION OUTPUT ;
    USE SIGNAL ;
    PORT
      LAYER M5 ;
        RECT  15.888 0 15.912 0.084 ;
    END
  END b_d[46]
  PIN b_d[470]
    DIRECTION OUTPUT ;
    USE SIGNAL ;
    PORT
      LAYER M5 ;
        RECT  36.24 0 36.264 0.084 ;
    END
  END b_d[470]
  PIN b_d[471]
    DIRECTION OUTPUT ;
    USE SIGNAL ;
    PORT
      LAYER M5 ;
        RECT  36.288 0 36.312 0.084 ;
    END
  END b_d[471]
  PIN b_d[472]
    DIRECTION OUTPUT ;
    USE SIGNAL ;
    PORT
      LAYER M5 ;
        RECT  36.336 0 36.36 0.084 ;
    END
  END b_d[472]
  PIN b_d[473]
    DIRECTION OUTPUT ;
    USE SIGNAL ;
    PORT
      LAYER M5 ;
        RECT  36.384 0 36.408 0.084 ;
    END
  END b_d[473]
  PIN b_d[474]
    DIRECTION OUTPUT ;
    USE SIGNAL ;
    PORT
      LAYER M5 ;
        RECT  36.432 0 36.456 0.084 ;
    END
  END b_d[474]
  PIN b_d[475]
    DIRECTION OUTPUT ;
    USE SIGNAL ;
    PORT
      LAYER M5 ;
        RECT  36.48 0 36.504 0.084 ;
    END
  END b_d[475]
  PIN b_d[476]
    DIRECTION OUTPUT ;
    USE SIGNAL ;
    PORT
      LAYER M5 ;
        RECT  36.528 0 36.552 0.084 ;
    END
  END b_d[476]
  PIN b_d[477]
    DIRECTION OUTPUT ;
    USE SIGNAL ;
    PORT
      LAYER M5 ;
        RECT  36.576 0 36.6 0.084 ;
    END
  END b_d[477]
  PIN b_d[478]
    DIRECTION OUTPUT ;
    USE SIGNAL ;
    PORT
      LAYER M5 ;
        RECT  36.624 0 36.648 0.084 ;
    END
  END b_d[478]
  PIN b_d[479]
    DIRECTION OUTPUT ;
    USE SIGNAL ;
    PORT
      LAYER M5 ;
        RECT  36.672 0 36.696 0.084 ;
    END
  END b_d[479]
  PIN b_d[47]
    DIRECTION OUTPUT ;
    USE SIGNAL ;
    PORT
      LAYER M5 ;
        RECT  15.936 0 15.96 0.084 ;
    END
  END b_d[47]
  PIN b_d[480]
    DIRECTION OUTPUT ;
    USE SIGNAL ;
    PORT
      LAYER M5 ;
        RECT  36.72 0 36.744 0.084 ;
    END
  END b_d[480]
  PIN b_d[481]
    DIRECTION OUTPUT ;
    USE SIGNAL ;
    PORT
      LAYER M5 ;
        RECT  36.768 0 36.792 0.084 ;
    END
  END b_d[481]
  PIN b_d[482]
    DIRECTION OUTPUT ;
    USE SIGNAL ;
    PORT
      LAYER M5 ;
        RECT  36.816 0 36.84 0.084 ;
    END
  END b_d[482]
  PIN b_d[483]
    DIRECTION OUTPUT ;
    USE SIGNAL ;
    PORT
      LAYER M5 ;
        RECT  36.864 0 36.888 0.084 ;
    END
  END b_d[483]
  PIN b_d[484]
    DIRECTION OUTPUT ;
    USE SIGNAL ;
    PORT
      LAYER M5 ;
        RECT  36.912 0 36.936 0.084 ;
    END
  END b_d[484]
  PIN b_d[485]
    DIRECTION OUTPUT ;
    USE SIGNAL ;
    PORT
      LAYER M5 ;
        RECT  36.96 0 36.984 0.084 ;
    END
  END b_d[485]
  PIN b_d[486]
    DIRECTION OUTPUT ;
    USE SIGNAL ;
    PORT
      LAYER M5 ;
        RECT  37.008 0 37.032 0.084 ;
    END
  END b_d[486]
  PIN b_d[487]
    DIRECTION OUTPUT ;
    USE SIGNAL ;
    PORT
      LAYER M5 ;
        RECT  37.056 0 37.08 0.084 ;
    END
  END b_d[487]
  PIN b_d[488]
    DIRECTION OUTPUT ;
    USE SIGNAL ;
    PORT
      LAYER M5 ;
        RECT  37.104 0 37.128 0.084 ;
    END
  END b_d[488]
  PIN b_d[489]
    DIRECTION OUTPUT ;
    USE SIGNAL ;
    PORT
      LAYER M5 ;
        RECT  37.152 0 37.176 0.084 ;
    END
  END b_d[489]
  PIN b_d[48]
    DIRECTION OUTPUT ;
    USE SIGNAL ;
    PORT
      LAYER M5 ;
        RECT  15.984 0 16.008 0.084 ;
    END
  END b_d[48]
  PIN b_d[490]
    DIRECTION OUTPUT ;
    USE SIGNAL ;
    PORT
      LAYER M5 ;
        RECT  37.2 0 37.224 0.084 ;
    END
  END b_d[490]
  PIN b_d[491]
    DIRECTION OUTPUT ;
    USE SIGNAL ;
    PORT
      LAYER M5 ;
        RECT  37.248 0 37.272 0.084 ;
    END
  END b_d[491]
  PIN b_d[492]
    DIRECTION OUTPUT ;
    USE SIGNAL ;
    PORT
      LAYER M5 ;
        RECT  37.296 0 37.32 0.084 ;
    END
  END b_d[492]
  PIN b_d[493]
    DIRECTION OUTPUT ;
    USE SIGNAL ;
    PORT
      LAYER M5 ;
        RECT  37.344 0 37.368 0.084 ;
    END
  END b_d[493]
  PIN b_d[494]
    DIRECTION OUTPUT ;
    USE SIGNAL ;
    PORT
      LAYER M5 ;
        RECT  37.392 0 37.416 0.084 ;
    END
  END b_d[494]
  PIN b_d[495]
    DIRECTION OUTPUT ;
    USE SIGNAL ;
    PORT
      LAYER M5 ;
        RECT  37.44 0 37.464 0.084 ;
    END
  END b_d[495]
  PIN b_d[496]
    DIRECTION OUTPUT ;
    USE SIGNAL ;
    PORT
      LAYER M5 ;
        RECT  37.488 0 37.512 0.084 ;
    END
  END b_d[496]
  PIN b_d[497]
    DIRECTION OUTPUT ;
    USE SIGNAL ;
    PORT
      LAYER M5 ;
        RECT  37.536 0 37.56 0.084 ;
    END
  END b_d[497]
  PIN b_d[498]
    DIRECTION OUTPUT ;
    USE SIGNAL ;
    PORT
      LAYER M5 ;
        RECT  37.584 0 37.608 0.084 ;
    END
  END b_d[498]
  PIN b_d[499]
    DIRECTION OUTPUT ;
    USE SIGNAL ;
    PORT
      LAYER M5 ;
        RECT  37.632 0 37.656 0.084 ;
    END
  END b_d[499]
  PIN b_d[49]
    DIRECTION OUTPUT ;
    USE SIGNAL ;
    PORT
      LAYER M5 ;
        RECT  16.032 0 16.056 0.084 ;
    END
  END b_d[49]
  PIN b_d[4]
    DIRECTION OUTPUT ;
    USE SIGNAL ;
    PORT
      LAYER M5 ;
        RECT  13.872 0 13.896 0.084 ;
    END
  END b_d[4]
  PIN b_d[500]
    DIRECTION OUTPUT ;
    USE SIGNAL ;
    PORT
      LAYER M5 ;
        RECT  37.68 0 37.704 0.084 ;
    END
  END b_d[500]
  PIN b_d[501]
    DIRECTION OUTPUT ;
    USE SIGNAL ;
    PORT
      LAYER M5 ;
        RECT  37.728 0 37.752 0.084 ;
    END
  END b_d[501]
  PIN b_d[502]
    DIRECTION OUTPUT ;
    USE SIGNAL ;
    PORT
      LAYER M5 ;
        RECT  37.776 0 37.8 0.084 ;
    END
  END b_d[502]
  PIN b_d[503]
    DIRECTION OUTPUT ;
    USE SIGNAL ;
    PORT
      LAYER M5 ;
        RECT  37.824 0 37.848 0.084 ;
    END
  END b_d[503]
  PIN b_d[504]
    DIRECTION OUTPUT ;
    USE SIGNAL ;
    PORT
      LAYER M5 ;
        RECT  37.872 0 37.896 0.084 ;
    END
  END b_d[504]
  PIN b_d[505]
    DIRECTION OUTPUT ;
    USE SIGNAL ;
    PORT
      LAYER M5 ;
        RECT  37.92 0 37.944 0.084 ;
    END
  END b_d[505]
  PIN b_d[506]
    DIRECTION OUTPUT ;
    USE SIGNAL ;
    PORT
      LAYER M5 ;
        RECT  37.968 0 37.992 0.084 ;
    END
  END b_d[506]
  PIN b_d[507]
    DIRECTION OUTPUT ;
    USE SIGNAL ;
    PORT
      LAYER M5 ;
        RECT  38.016 0 38.04 0.084 ;
    END
  END b_d[507]
  PIN b_d[508]
    DIRECTION OUTPUT ;
    USE SIGNAL ;
    PORT
      LAYER M5 ;
        RECT  38.064 0 38.088 0.084 ;
    END
  END b_d[508]
  PIN b_d[509]
    DIRECTION OUTPUT ;
    USE SIGNAL ;
    PORT
      LAYER M5 ;
        RECT  38.112 0 38.136 0.084 ;
    END
  END b_d[509]
  PIN b_d[50]
    DIRECTION OUTPUT ;
    USE SIGNAL ;
    PORT
      LAYER M5 ;
        RECT  16.08 0 16.104 0.084 ;
    END
  END b_d[50]
  PIN b_d[510]
    DIRECTION OUTPUT ;
    USE SIGNAL ;
    PORT
      LAYER M5 ;
        RECT  38.16 0 38.184 0.084 ;
    END
  END b_d[510]
  PIN b_d[511]
    DIRECTION OUTPUT ;
    USE SIGNAL ;
    PORT
      LAYER M5 ;
        RECT  38.208 0 38.232 0.084 ;
    END
  END b_d[511]
  PIN b_d[51]
    DIRECTION OUTPUT ;
    USE SIGNAL ;
    PORT
      LAYER M5 ;
        RECT  16.128 0 16.152 0.084 ;
    END
  END b_d[51]
  PIN b_d[52]
    DIRECTION OUTPUT ;
    USE SIGNAL ;
    PORT
      LAYER M5 ;
        RECT  16.176 0 16.2 0.084 ;
    END
  END b_d[52]
  PIN b_d[53]
    DIRECTION OUTPUT ;
    USE SIGNAL ;
    PORT
      LAYER M5 ;
        RECT  16.224 0 16.248 0.084 ;
    END
  END b_d[53]
  PIN b_d[54]
    DIRECTION OUTPUT ;
    USE SIGNAL ;
    PORT
      LAYER M5 ;
        RECT  16.272 0 16.296 0.084 ;
    END
  END b_d[54]
  PIN b_d[55]
    DIRECTION OUTPUT ;
    USE SIGNAL ;
    PORT
      LAYER M5 ;
        RECT  16.32 0 16.344 0.084 ;
    END
  END b_d[55]
  PIN b_d[56]
    DIRECTION OUTPUT ;
    USE SIGNAL ;
    PORT
      LAYER M5 ;
        RECT  16.368 0 16.392 0.084 ;
    END
  END b_d[56]
  PIN b_d[57]
    DIRECTION OUTPUT ;
    USE SIGNAL ;
    PORT
      LAYER M5 ;
        RECT  16.416 0 16.44 0.084 ;
    END
  END b_d[57]
  PIN b_d[58]
    DIRECTION OUTPUT ;
    USE SIGNAL ;
    PORT
      LAYER M5 ;
        RECT  16.464 0 16.488 0.084 ;
    END
  END b_d[58]
  PIN b_d[59]
    DIRECTION OUTPUT ;
    USE SIGNAL ;
    PORT
      LAYER M5 ;
        RECT  16.512 0 16.536 0.084 ;
    END
  END b_d[59]
  PIN b_d[5]
    DIRECTION OUTPUT ;
    USE SIGNAL ;
    PORT
      LAYER M5 ;
        RECT  13.92 0 13.944 0.084 ;
    END
  END b_d[5]
  PIN b_d[60]
    DIRECTION OUTPUT ;
    USE SIGNAL ;
    PORT
      LAYER M5 ;
        RECT  16.56 0 16.584 0.084 ;
    END
  END b_d[60]
  PIN b_d[61]
    DIRECTION OUTPUT ;
    USE SIGNAL ;
    PORT
      LAYER M5 ;
        RECT  16.608 0 16.632 0.084 ;
    END
  END b_d[61]
  PIN b_d[62]
    DIRECTION OUTPUT ;
    USE SIGNAL ;
    PORT
      LAYER M5 ;
        RECT  16.656 0 16.68 0.084 ;
    END
  END b_d[62]
  PIN b_d[63]
    DIRECTION OUTPUT ;
    USE SIGNAL ;
    PORT
      LAYER M5 ;
        RECT  16.704 0 16.728 0.084 ;
    END
  END b_d[63]
  PIN b_d[64]
    DIRECTION OUTPUT ;
    USE SIGNAL ;
    PORT
      LAYER M5 ;
        RECT  16.752 0 16.776 0.084 ;
    END
  END b_d[64]
  PIN b_d[65]
    DIRECTION OUTPUT ;
    USE SIGNAL ;
    PORT
      LAYER M5 ;
        RECT  16.8 0 16.824 0.084 ;
    END
  END b_d[65]
  PIN b_d[66]
    DIRECTION OUTPUT ;
    USE SIGNAL ;
    PORT
      LAYER M5 ;
        RECT  16.848 0 16.872 0.084 ;
    END
  END b_d[66]
  PIN b_d[67]
    DIRECTION OUTPUT ;
    USE SIGNAL ;
    PORT
      LAYER M5 ;
        RECT  16.896 0 16.92 0.084 ;
    END
  END b_d[67]
  PIN b_d[68]
    DIRECTION OUTPUT ;
    USE SIGNAL ;
    PORT
      LAYER M5 ;
        RECT  16.944 0 16.968 0.084 ;
    END
  END b_d[68]
  PIN b_d[69]
    DIRECTION OUTPUT ;
    USE SIGNAL ;
    PORT
      LAYER M5 ;
        RECT  16.992 0 17.016 0.084 ;
    END
  END b_d[69]
  PIN b_d[6]
    DIRECTION OUTPUT ;
    USE SIGNAL ;
    PORT
      LAYER M5 ;
        RECT  13.968 0 13.992 0.084 ;
    END
  END b_d[6]
  PIN b_d[70]
    DIRECTION OUTPUT ;
    USE SIGNAL ;
    PORT
      LAYER M5 ;
        RECT  17.04 0 17.064 0.084 ;
    END
  END b_d[70]
  PIN b_d[71]
    DIRECTION OUTPUT ;
    USE SIGNAL ;
    PORT
      LAYER M5 ;
        RECT  17.088 0 17.112 0.084 ;
    END
  END b_d[71]
  PIN b_d[72]
    DIRECTION OUTPUT ;
    USE SIGNAL ;
    PORT
      LAYER M5 ;
        RECT  17.136 0 17.16 0.084 ;
    END
  END b_d[72]
  PIN b_d[73]
    DIRECTION OUTPUT ;
    USE SIGNAL ;
    PORT
      LAYER M5 ;
        RECT  17.184 0 17.208 0.084 ;
    END
  END b_d[73]
  PIN b_d[74]
    DIRECTION OUTPUT ;
    USE SIGNAL ;
    PORT
      LAYER M5 ;
        RECT  17.232 0 17.256 0.084 ;
    END
  END b_d[74]
  PIN b_d[75]
    DIRECTION OUTPUT ;
    USE SIGNAL ;
    PORT
      LAYER M5 ;
        RECT  17.28 0 17.304 0.084 ;
    END
  END b_d[75]
  PIN b_d[76]
    DIRECTION OUTPUT ;
    USE SIGNAL ;
    PORT
      LAYER M5 ;
        RECT  17.328 0 17.352 0.084 ;
    END
  END b_d[76]
  PIN b_d[77]
    DIRECTION OUTPUT ;
    USE SIGNAL ;
    PORT
      LAYER M5 ;
        RECT  17.376 0 17.4 0.084 ;
    END
  END b_d[77]
  PIN b_d[78]
    DIRECTION OUTPUT ;
    USE SIGNAL ;
    PORT
      LAYER M5 ;
        RECT  17.424 0 17.448 0.084 ;
    END
  END b_d[78]
  PIN b_d[79]
    DIRECTION OUTPUT ;
    USE SIGNAL ;
    PORT
      LAYER M5 ;
        RECT  17.472 0 17.496 0.084 ;
    END
  END b_d[79]
  PIN b_d[7]
    DIRECTION OUTPUT ;
    USE SIGNAL ;
    PORT
      LAYER M5 ;
        RECT  14.016 0 14.04 0.084 ;
    END
  END b_d[7]
  PIN b_d[80]
    DIRECTION OUTPUT ;
    USE SIGNAL ;
    PORT
      LAYER M5 ;
        RECT  17.52 0 17.544 0.084 ;
    END
  END b_d[80]
  PIN b_d[81]
    DIRECTION OUTPUT ;
    USE SIGNAL ;
    PORT
      LAYER M5 ;
        RECT  17.568 0 17.592 0.084 ;
    END
  END b_d[81]
  PIN b_d[82]
    DIRECTION OUTPUT ;
    USE SIGNAL ;
    PORT
      LAYER M5 ;
        RECT  17.616 0 17.64 0.084 ;
    END
  END b_d[82]
  PIN b_d[83]
    DIRECTION OUTPUT ;
    USE SIGNAL ;
    PORT
      LAYER M5 ;
        RECT  17.664 0 17.688 0.084 ;
    END
  END b_d[83]
  PIN b_d[84]
    DIRECTION OUTPUT ;
    USE SIGNAL ;
    PORT
      LAYER M5 ;
        RECT  17.712 0 17.736 0.084 ;
    END
  END b_d[84]
  PIN b_d[85]
    DIRECTION OUTPUT ;
    USE SIGNAL ;
    PORT
      LAYER M5 ;
        RECT  17.76 0 17.784 0.084 ;
    END
  END b_d[85]
  PIN b_d[86]
    DIRECTION OUTPUT ;
    USE SIGNAL ;
    PORT
      LAYER M5 ;
        RECT  17.808 0 17.832 0.084 ;
    END
  END b_d[86]
  PIN b_d[87]
    DIRECTION OUTPUT ;
    USE SIGNAL ;
    PORT
      LAYER M5 ;
        RECT  17.856 0 17.88 0.084 ;
    END
  END b_d[87]
  PIN b_d[88]
    DIRECTION OUTPUT ;
    USE SIGNAL ;
    PORT
      LAYER M5 ;
        RECT  17.904 0 17.928 0.084 ;
    END
  END b_d[88]
  PIN b_d[89]
    DIRECTION OUTPUT ;
    USE SIGNAL ;
    PORT
      LAYER M5 ;
        RECT  17.952 0 17.976 0.084 ;
    END
  END b_d[89]
  PIN b_d[8]
    DIRECTION OUTPUT ;
    USE SIGNAL ;
    PORT
      LAYER M5 ;
        RECT  14.064 0 14.088 0.084 ;
    END
  END b_d[8]
  PIN b_d[90]
    DIRECTION OUTPUT ;
    USE SIGNAL ;
    PORT
      LAYER M5 ;
        RECT  18 0 18.024 0.084 ;
    END
  END b_d[90]
  PIN b_d[91]
    DIRECTION OUTPUT ;
    USE SIGNAL ;
    PORT
      LAYER M5 ;
        RECT  18.048 0 18.072 0.084 ;
    END
  END b_d[91]
  PIN b_d[92]
    DIRECTION OUTPUT ;
    USE SIGNAL ;
    PORT
      LAYER M5 ;
        RECT  18.096 0 18.12 0.084 ;
    END
  END b_d[92]
  PIN b_d[93]
    DIRECTION OUTPUT ;
    USE SIGNAL ;
    PORT
      LAYER M5 ;
        RECT  18.144 0 18.168 0.084 ;
    END
  END b_d[93]
  PIN b_d[94]
    DIRECTION OUTPUT ;
    USE SIGNAL ;
    PORT
      LAYER M5 ;
        RECT  18.192 0 18.216 0.084 ;
    END
  END b_d[94]
  PIN b_d[95]
    DIRECTION OUTPUT ;
    USE SIGNAL ;
    PORT
      LAYER M5 ;
        RECT  18.24 0 18.264 0.084 ;
    END
  END b_d[95]
  PIN b_d[96]
    DIRECTION OUTPUT ;
    USE SIGNAL ;
    PORT
      LAYER M5 ;
        RECT  18.288 0 18.312 0.084 ;
    END
  END b_d[96]
  PIN b_d[97]
    DIRECTION OUTPUT ;
    USE SIGNAL ;
    PORT
      LAYER M5 ;
        RECT  18.336 0 18.36 0.084 ;
    END
  END b_d[97]
  PIN b_d[98]
    DIRECTION OUTPUT ;
    USE SIGNAL ;
    PORT
      LAYER M5 ;
        RECT  18.384 0 18.408 0.084 ;
    END
  END b_d[98]
  PIN b_d[99]
    DIRECTION OUTPUT ;
    USE SIGNAL ;
    PORT
      LAYER M5 ;
        RECT  18.432 0 18.456 0.084 ;
    END
  END b_d[99]
  PIN b_d[9]
    DIRECTION OUTPUT ;
    USE SIGNAL ;
    PORT
      LAYER M5 ;
        RECT  14.112 0 14.136 0.084 ;
    END
  END b_d[9]
  PIN b_r
    DIRECTION INPUT ;
    USE SIGNAL ;
    PORT
      LAYER M5 ;
        RECT  38.256 0 38.28 0.084 ;
    END
  END b_r
  PIN c_d[0]
    DIRECTION OUTPUT ;
    USE SIGNAL ;
    PORT
      LAYER M4 ;
        RECT  0 25.728 0.084 25.752 ;
    END
  END c_d[0]
  PIN c_r
    DIRECTION INPUT ;
    USE SIGNAL ;
    PORT
      LAYER M4 ;
        RECT  0 25.776 0.084 25.8 ;
    END
  END c_r
  PIN clk
    DIRECTION INPUT ;
    USE SIGNAL ;
    PORT
      LAYER M4 ;
        RECT  0 25.824 0.084 25.848 ;
    END
  END clk
  PIN rst_n
    DIRECTION INPUT ;
    USE SIGNAL ;
    PORT
      LAYER M4 ;
        RECT  0 25.872 0.084 25.896 ;
    END
  END rst_n
  PIN t_d[0]
    DIRECTION OUTPUT ;
    USE SIGNAL ;
    PORT
      LAYER M4 ;
        RECT  0 25.92 0.084 25.944 ;
    END
  END t_d[0]
  PIN t_r
    DIRECTION INPUT ;
    USE SIGNAL ;
    PORT
      LAYER M4 ;
        RECT  0 25.968 0.084 25.992 ;
    END
  END t_r
  PIN VDD
    DIRECTION INOUT ;
    USE POWER ;
    PORT
      LAYER M6 ;
        RECT  2.16 24.513 50.49 24.801 ;
        RECT  2.16 19.113 50.49 19.401 ;
        RECT  2.16 13.713 50.49 14.001 ;
        RECT  2.16 8.313 50.49 8.601 ;
        RECT  2.16 2.913 50.49 3.201 ;
    END
  END VDD
  PIN VSS
    DIRECTION INOUT ;
    USE GROUND ;
    PORT
      LAYER M6 ;
        RECT  2.16 24.129 50.49 24.417 ;
        RECT  2.16 18.729 50.49 19.017 ;
        RECT  2.16 13.329 50.49 13.617 ;
        RECT  2.16 7.929 50.49 8.217 ;
        RECT  2.16 2.529 50.49 2.817 ;
    END
  END VSS
  OBS
    LAYER RVTN ;
     RECT  2.16 2.16 50.49 2.295 ;
     RECT  2.16 2.565 50.49 2.835 ;
     RECT  2.16 3.105 50.49 3.375 ;
     RECT  2.16 3.645 50.49 3.915 ;
     RECT  2.16 4.185 50.49 4.455 ;
     RECT  2.16 4.725 50.49 4.995 ;
     RECT  2.16 5.265 50.49 5.535 ;
     RECT  2.16 5.805 50.49 6.075 ;
     RECT  2.16 6.345 50.49 6.615 ;
     RECT  2.16 6.885 50.49 7.155 ;
     RECT  2.16 7.425 50.49 7.695 ;
     RECT  2.16 7.965 50.49 8.235 ;
     RECT  2.16 8.505 50.49 8.775 ;
     RECT  2.16 9.045 50.49 9.315 ;
     RECT  2.16 9.585 50.49 9.855 ;
     RECT  2.16 10.125 50.49 10.395 ;
     RECT  2.16 10.665 50.49 10.935 ;
     RECT  2.16 11.205 50.49 11.475 ;
     RECT  2.16 11.745 50.49 12.015 ;
     RECT  2.16 12.285 50.49 12.555 ;
     RECT  2.16 12.825 50.49 13.095 ;
     RECT  2.16 13.365 50.49 13.635 ;
     RECT  2.16 13.905 50.49 14.175 ;
     RECT  2.16 14.445 50.49 14.715 ;
     RECT  2.16 14.985 50.49 15.255 ;
     RECT  2.16 15.525 50.49 15.795 ;
     RECT  2.16 16.065 50.49 16.335 ;
     RECT  2.16 16.605 50.49 16.875 ;
     RECT  2.16 17.145 50.49 17.415 ;
     RECT  2.16 17.685 50.49 17.955 ;
     RECT  2.16 18.225 50.49 18.495 ;
     RECT  2.16 18.765 50.49 19.035 ;
     RECT  2.16 19.305 50.49 19.575 ;
     RECT  2.16 19.845 50.49 20.115 ;
     RECT  2.16 20.385 50.49 20.655 ;
     RECT  2.16 20.925 50.49 21.195 ;
     RECT  2.16 21.465 50.49 21.735 ;
     RECT  2.16 22.005 50.49 22.275 ;
     RECT  2.16 22.545 50.49 22.815 ;
     RECT  2.16 23.085 50.49 23.355 ;
     RECT  2.16 23.625 50.49 23.895 ;
     RECT  2.16 24.165 50.49 24.435 ;
     RECT  2.16 24.705 50.49 24.975 ;
     RECT  2.16 25.245 50.49 25.515 ;
     RECT  2.16 25.785 50.49 26.055 ;
     RECT  2.16 26.325 50.49 26.595 ;
     RECT  2.16 26.865 50.49 27.135 ;
     RECT  2.16 27.405 50.49 27.675 ;
     RECT  2.16 27.945 50.49 28.08 ;
    LAYER RVTP ;
     RECT  2.16 2.295 50.49 2.565 ;
     RECT  2.16 2.835 50.49 3.105 ;
     RECT  2.16 3.375 50.49 3.645 ;
     RECT  2.16 3.915 50.49 4.185 ;
     RECT  2.16 4.455 50.49 4.725 ;
     RECT  2.16 4.995 50.49 5.265 ;
     RECT  2.16 5.535 50.49 5.805 ;
     RECT  2.16 6.075 50.49 6.345 ;
     RECT  2.16 6.615 50.49 6.885 ;
     RECT  2.16 7.155 50.49 7.425 ;
     RECT  2.16 7.695 50.49 7.965 ;
     RECT  2.16 8.235 50.49 8.505 ;
     RECT  2.16 8.775 50.49 9.045 ;
     RECT  2.16 9.315 50.49 9.585 ;
     RECT  2.16 9.855 50.49 10.125 ;
     RECT  2.16 10.395 50.49 10.665 ;
     RECT  2.16 10.935 50.49 11.205 ;
     RECT  2.16 11.475 50.49 11.745 ;
     RECT  2.16 12.015 50.49 12.285 ;
     RECT  2.16 12.555 50.49 12.825 ;
     RECT  2.16 13.095 50.49 13.365 ;
     RECT  2.16 13.635 50.49 13.905 ;
     RECT  2.16 14.175 50.49 14.445 ;
     RECT  2.16 14.715 50.49 14.985 ;
     RECT  2.16 15.255 50.49 15.525 ;
     RECT  2.16 15.795 50.49 16.065 ;
     RECT  2.16 16.335 50.49 16.605 ;
     RECT  2.16 16.875 50.49 17.145 ;
     RECT  2.16 17.415 50.49 17.685 ;
     RECT  2.16 17.955 50.49 18.225 ;
     RECT  2.16 18.495 50.49 18.765 ;
     RECT  2.16 19.035 50.49 19.305 ;
     RECT  2.16 19.575 50.49 19.845 ;
     RECT  2.16 20.115 50.49 20.385 ;
     RECT  2.16 20.655 50.49 20.925 ;
     RECT  2.16 21.195 50.49 21.465 ;
     RECT  2.16 21.735 50.49 22.005 ;
     RECT  2.16 22.275 50.49 22.545 ;
     RECT  2.16 22.815 50.49 23.085 ;
     RECT  2.16 23.355 50.49 23.625 ;
     RECT  2.16 23.895 50.49 24.165 ;
     RECT  2.16 24.435 50.49 24.705 ;
     RECT  2.16 24.975 50.49 25.245 ;
     RECT  2.16 25.515 50.49 25.785 ;
     RECT  2.16 26.055 50.49 26.325 ;
     RECT  2.16 26.595 50.49 26.865 ;
     RECT  2.16 27.135 50.49 27.405 ;
     RECT  2.16 27.675 50.49 27.945 ;
    LAYER M1 ;
     RECT  2.16 2.151 50.49 28.089 ;
    LAYER M2 ;
     RECT  0.139 25.992 0.211 26.01 ;
     RECT  0.211 25.794 2.16 26.01 ;
     RECT  2.16 2.151 11.371 28.089 ;
     RECT  11.371 2.106 11.947 28.089 ;
     RECT  11.947 2.034 12.631 28.089 ;
     RECT  12.631 1.881 14.035 28.089 ;
     RECT  14.035 1.836 14.827 28.089 ;
     RECT  14.827 1.836 14.927 28.629 ;
     RECT  14.927 1.836 15.395 28.089 ;
     RECT  15.395 1.998 15.791 28.089 ;
     RECT  14.683 0.261 16.259 0.279 ;
     RECT  15.791 2.034 16.907 28.089 ;
     RECT  16.907 2.151 18.535 28.089 ;
     RECT  18.535 2.106 18.887 28.089 ;
     RECT  18.887 2.151 21.667 28.089 ;
     RECT  21.667 2.106 21.911 28.089 ;
     RECT  21.911 2.151 22.999 28.089 ;
     RECT  22.999 2.106 23.683 28.089 ;
     RECT  23.683 2.034 24.791 28.089 ;
     RECT  24.791 2.106 25.187 28.089 ;
     RECT  25.187 2.151 26.203 28.089 ;
     RECT  26.203 2.106 26.671 28.089 ;
     RECT  26.671 2.034 27.023 28.089 ;
     RECT  27.023 2.151 27.859 28.089 ;
     RECT  27.859 2.106 30.091 28.089 ;
     RECT  30.091 2.034 30.775 28.089 ;
     RECT  33.007 0.144 33.107 0.162 ;
     RECT  30.775 1.728 34.475 28.089 ;
     RECT  34.475 1.8 34.511 28.089 ;
     RECT  34.771 0.576 35.383 0.594 ;
     RECT  34.511 1.881 35.635 28.089 ;
     RECT  35.383 0.576 35.923 0.666 ;
     RECT  35.923 0.576 36.499 0.702 ;
     RECT  35.635 1.728 36.499 28.089 ;
     RECT  36.499 0.576 37.687 28.089 ;
     RECT  37.687 0.531 39.371 28.089 ;
     RECT  39.371 0.576 39.479 28.089 ;
     RECT  39.479 0.576 39.623 0.63 ;
     RECT  39.623 0.576 39.767 0.594 ;
     RECT  39.479 1.836 39.947 28.089 ;
     RECT  39.947 1.881 40.415 28.089 ;
     RECT  40.415 1.962 42.467 28.089 ;
     RECT  42.467 2.151 50.49 28.089 ;
    LAYER M3 ;
     RECT  13.536 0.043 13.554 0.091 ;
     RECT  15.588 0.043 15.606 0.091 ;
     RECT  13.536 0.091 13.842 0.139 ;
     RECT  15.588 0.091 16.074 0.139 ;
     RECT  24.732 0.091 24.75 0.139 ;
     RECT  25.884 0.091 26.01 0.139 ;
     RECT  27.576 0.091 27.594 0.139 ;
     RECT  28.62 0.091 28.638 0.139 ;
     RECT  30.888 0.091 30.906 0.139 ;
     RECT  32.22 0.091 32.238 0.139 ;
     RECT  34.704 0.091 34.722 0.139 ;
     RECT  36.396 0.091 36.414 0.139 ;
     RECT  38.628 0.091 38.646 0.139 ;
     RECT  13.176 0.139 13.842 0.187 ;
     RECT  14.724 0.139 18.198 0.187 ;
     RECT  18.972 0.139 23.562 0.187 ;
     RECT  24.336 0.139 24.822 0.187 ;
     RECT  25.884 0.139 27.666 0.187 ;
     RECT  28.548 0.139 28.638 0.187 ;
     RECT  29.628 0.139 30.906 0.187 ;
     RECT  31.932 0.139 32.238 0.187 ;
     RECT  33.012 0.139 33.102 0.187 ;
     RECT  34.2 0.139 34.722 0.187 ;
     RECT  35.928 0.139 36.414 0.187 ;
     RECT  38.196 0.139 38.646 0.187 ;
     RECT  12.96 0.187 18.198 0.235 ;
     RECT  18.972 0.187 28.638 0.235 ;
     RECT  29.628 0.187 38.646 0.235 ;
     RECT  18.936 0.235 38.682 0.379 ;
     RECT  39.42 0.331 39.438 0.379 ;
     RECT  18.936 0.379 39.438 0.475 ;
     RECT  12.384 0.235 18.198 0.571 ;
     RECT  18.936 0.475 39.546 0.571 ;
     RECT  12.384 0.571 39.762 0.811 ;
     RECT  12.384 0.811 40.194 0.859 ;
     RECT  12.384 0.859 40.446 2.029 ;
     RECT  42.444 1.957 42.462 2.029 ;
     RECT  11.952 2.029 40.446 2.101 ;
     RECT  42.192 2.029 42.462 2.101 ;
     RECT  11.376 2.101 40.446 2.191 ;
     RECT  11.376 2.191 41.022 2.263 ;
     RECT  42.156 2.101 42.462 2.263 ;
     RECT  43.2 2.227 43.218 2.263 ;
     RECT  10.764 2.263 41.346 2.335 ;
     RECT  2.415 2.143 2.505 2.413 ;
     RECT  7.815 2.143 7.905 2.413 ;
     RECT  45.615 2.143 45.705 2.413 ;
     RECT  10.656 2.335 41.346 2.569 ;
     RECT  10.368 2.569 41.346 2.605 ;
     RECT  42.156 2.263 43.218 2.605 ;
     RECT  10.368 2.605 43.218 2.875 ;
     RECT  10.26 2.875 43.218 3.001 ;
     RECT  10.044 3.001 43.218 3.181 ;
     RECT  10.008 3.181 43.542 4.765 ;
     RECT  9.972 4.765 43.542 4.891 ;
     RECT  9.432 4.891 43.542 7.465 ;
     RECT  9.432 7.465 43.614 7.501 ;
     RECT  9.432 7.501 43.758 7.819 ;
     RECT  7.815 2.413 8.097 7.861 ;
     RECT  8.856 7.819 43.758 7.861 ;
     RECT  7.815 7.861 43.758 7.889 ;
     RECT  7.815 7.889 43.614 8.195 ;
     RECT  9.216 8.195 43.614 8.699 ;
     RECT  9.216 8.699 43.542 9.355 ;
     RECT  9.144 9.355 43.542 12.361 ;
     RECT  9.144 12.361 43.686 12.523 ;
     RECT  9.144 12.523 43.902 13.019 ;
     RECT  9.144 13.019 43.722 13.055 ;
     RECT  9.144 13.055 43.542 14.791 ;
     RECT  9.144 14.791 43.614 14.881 ;
     RECT  9.144 14.881 43.686 15.449 ;
     RECT  9.36 15.449 43.686 16.339 ;
     RECT  9.36 16.339 43.83 16.529 ;
     RECT  9.36 16.529 43.614 19.949 ;
     RECT  9.54 19.949 43.614 21.259 ;
     RECT  9.396 21.259 43.614 21.775 ;
     RECT  9.324 21.775 43.614 22.891 ;
     RECT  9.144 22.891 43.614 23.045 ;
     RECT  2.415 2.413 2.697 23.089 ;
     RECT  6.84 23.017 6.858 23.117 ;
     RECT  9.324 23.045 43.614 24.133 ;
     RECT  9.324 24.133 43.974 24.269 ;
     RECT  9.36 24.269 43.974 24.395 ;
     RECT  9.576 24.395 43.974 25.285 ;
     RECT  9.432 25.285 44.694 25.321 ;
     RECT  45.615 2.413 45.897 25.321 ;
     RECT  9.432 25.321 45.897 25.475 ;
     RECT  2.415 23.089 3.222 25.709 ;
     RECT  0.216 25.723 0.234 25.817 ;
     RECT  2.415 25.709 3.006 25.861 ;
     RECT  2.268 25.861 3.006 25.949 ;
     RECT  2.304 25.949 3.006 25.979 ;
     RECT  0.144 25.867 0.162 26.015 ;
     RECT  2.304 25.979 2.697 26.285 ;
     RECT  9.576 25.475 45.897 26.765 ;
     RECT  9.576 26.765 43.002 26.789 ;
     RECT  43.884 26.765 45.897 26.861 ;
     RECT  44.28 26.861 45.897 27.203 ;
     RECT  9.576 26.789 42.606 27.211 ;
     RECT  9.432 27.211 42.606 27.329 ;
     RECT  9.432 27.329 41.166 27.365 ;
     RECT  44.28 27.203 44.55 27.365 ;
     RECT  9.756 27.365 41.166 27.437 ;
     RECT  42.012 27.329 42.066 27.599 ;
     RECT  9.756 27.437 41.13 27.635 ;
     RECT  44.28 27.365 44.298 27.743 ;
     RECT  2.415 26.285 2.697 27.827 ;
     RECT  7.815 8.195 8.097 27.827 ;
     RECT  45.615 27.203 45.897 27.827 ;
     RECT  10.152 27.635 41.13 27.869 ;
     RECT  42.048 27.599 42.066 27.869 ;
     RECT  10.656 27.869 41.13 27.905 ;
     RECT  12.24 27.905 38.142 27.917 ;
     RECT  38.88 27.905 39.15 27.917 ;
     RECT  10.656 27.905 11.358 27.941 ;
     RECT  12.6 27.917 38.142 27.941 ;
     RECT  12.6 27.941 37.89 27.977 ;
     RECT  38.88 27.917 39.042 28.013 ;
     RECT  11.34 27.941 11.358 28.049 ;
     RECT  2.415 27.827 2.505 28.097 ;
     RECT  7.815 27.827 7.905 28.097 ;
     RECT  40.215 27.905 40.305 28.097 ;
     RECT  45.615 27.827 45.705 28.097 ;
     RECT  12.78 27.977 37.89 28.541 ;
     RECT  12.78 28.541 31.266 28.589 ;
     RECT  32.328 28.541 37.89 28.637 ;
     RECT  12.78 28.589 29.358 28.733 ;
     RECT  41.04 27.905 41.058 28.781 ;
     RECT  32.4 28.637 37.89 28.973 ;
     RECT  12.78 28.733 28.962 29.069 ;
     RECT  30.168 28.589 31.266 29.069 ;
     RECT  13.716 29.069 28.962 29.693 ;
     RECT  32.4 28.973 33.606 29.693 ;
     RECT  32.4 29.693 32.958 29.707 ;
     RECT  34.344 28.973 37.89 29.707 ;
     RECT  13.716 29.693 25.866 29.741 ;
     RECT  13.824 29.741 23.31 29.789 ;
     RECT  14.328 29.789 15.498 29.837 ;
     RECT  16.416 29.789 23.31 29.837 ;
     RECT  30.276 29.069 31.266 29.851 ;
     RECT  32.328 29.707 32.958 29.851 ;
     RECT  12.78 29.069 12.798 29.885 ;
     RECT  14.328 29.837 14.778 29.885 ;
     RECT  26.712 29.693 28.962 29.899 ;
     RECT  26.712 29.899 29.178 29.947 ;
     RECT  34.344 29.707 38.034 29.947 ;
     RECT  14.364 29.885 14.778 29.981 ;
     RECT  16.416 29.837 23.274 29.981 ;
     RECT  24.48 29.741 25.866 29.981 ;
     RECT  39.024 28.013 39.042 29.981 ;
     RECT  14.544 29.981 14.778 30.029 ;
     RECT  16.416 29.981 21.114 30.029 ;
     RECT  22.176 29.981 23.274 30.029 ;
     RECT  24.48 29.981 25.65 30.029 ;
     RECT  26.712 29.947 29.394 30.029 ;
     RECT  30.276 29.851 32.958 30.029 ;
     RECT  34.344 29.947 38.142 30.029 ;
     RECT  16.416 30.029 17.622 30.077 ;
     RECT  19.728 30.029 19.926 30.077 ;
     RECT  22.176 30.029 22.518 30.077 ;
     RECT  24.48 30.029 24.498 30.077 ;
     RECT  25.344 30.029 25.65 30.077 ;
     RECT  26.712 30.029 28.35 30.077 ;
     RECT  29.16 30.029 29.394 30.077 ;
     RECT  31.608 30.029 32.742 30.077 ;
     RECT  34.344 30.029 35.298 30.077 ;
     RECT  36.468 30.029 38.142 30.077 ;
     RECT  14.544 30.029 14.562 30.125 ;
     RECT  16.992 30.077 17.622 30.125 ;
     RECT  22.176 30.077 22.194 30.125 ;
     RECT  26.712 30.077 26.73 30.125 ;
     RECT  29.376 30.077 29.394 30.125 ;
     RECT  30.384 30.029 30.546 30.125 ;
     RECT  31.608 30.077 32.274 30.125 ;
     RECT  34.344 30.077 34.362 30.125 ;
     RECT  36.468 30.077 36.486 30.125 ;
    LAYER M4 ;
     RECT  0.037 25.632 0.06 25.848 ;
     RECT  0.06 25.632 0.179 25.944 ;
     RECT  0.179 25.728 0.245 25.944 ;
     RECT  0.245 25.92 2.408 25.944 ;
     RECT  2.408 2.148 2.512 28.092 ;
     RECT  2.512 2.418 2.704 27.822 ;
     RECT  7.808 2.148 7.912 28.092 ;
     RECT  7.912 2.418 8.104 27.822 ;
     RECT  8.104 7.824 8.915 7.848 ;
     RECT  9.356 21.264 9.443 21.288 ;
     RECT  9.692 9.168 9.779 9.192 ;
     RECT  9.709 21.072 9.961 21.096 ;
     RECT  9.884 23.232 9.971 23.256 ;
     RECT  9.961 5.088 10.259 5.112 ;
     RECT  9.745 12.528 10.259 12.552 ;
     RECT  10.597 7.872 10.645 7.896 ;
     RECT  10.645 7.872 10.685 7.992 ;
     RECT  10.604 11.424 10.691 11.448 ;
     RECT  9.961 20.256 10.748 21.096 ;
     RECT  10.213 25.68 10.753 25.704 ;
     RECT  10.748 20.256 10.835 21.672 ;
     RECT  10.753 25.68 10.897 26.664 ;
     RECT  10.645 27.888 10.897 27.912 ;
     RECT  10.685 7.92 10.909 7.992 ;
     RECT  10.825 6.816 10.931 6.84 ;
     RECT  10.837 17.664 11.221 17.688 ;
     RECT  10.897 25.68 11.225 27.912 ;
     RECT  10.885 15.984 11.261 16.008 ;
     RECT  10.835 20.256 11.267 21.096 ;
     RECT  11.221 17.664 11.305 18.264 ;
     RECT  11.228 5.328 11.315 5.352 ;
     RECT  11.305 17.664 11.365 18.072 ;
     RECT  11.365 17.568 11.449 18.072 ;
     RECT  11.225 25.68 11.461 27.72 ;
     RECT  11.461 25.056 11.581 27.72 ;
     RECT  11.449 18.048 11.644 18.072 ;
     RECT  10.909 7.968 11.725 7.992 ;
     RECT  11.461 22.08 11.797 22.632 ;
     RECT  11.461 23.712 11.797 23.736 ;
     RECT  11.725 7.968 11.801 8.376 ;
     RECT  11.029 12.72 11.801 12.744 ;
     RECT  11.893 10.848 11.98 11.352 ;
     RECT  11.801 8.352 11.987 8.376 ;
     RECT  11.905 12.48 11.989 12.504 ;
     RECT  11.267 21.072 11.989 21.096 ;
     RECT  11.797 22.08 11.989 23.736 ;
     RECT  11.989 21.072 12.017 23.736 ;
     RECT  12.017 21.072 12.161 21.672 ;
     RECT  12.017 22.752 12.229 23.736 ;
     RECT  11.581 25.008 12.229 27.72 ;
     RECT  11.221 9.648 12.38 9.672 ;
     RECT  12.373 5.136 12.517 5.16 ;
     RECT  11.869 2.688 12.589 2.712 ;
     RECT  12.161 21.072 12.697 21.192 ;
     RECT  12.373 0.24 12.949 0.264 ;
     RECT  12.769 29.856 12.985 29.88 ;
     RECT  12.985 29.04 12.997 29.88 ;
     RECT  12.661 19.344 13.013 19.368 ;
     RECT  12.697 20.544 13.013 21.192 ;
     RECT  12.517 5.136 13.093 5.736 ;
     RECT  12.517 8.496 13.093 8.52 ;
     RECT  11.98 10.848 13.093 10.872 ;
     RECT  12.841 11.952 13.093 11.976 ;
     RECT  12.949 0.192 13.165 0.264 ;
     RECT  12.589 2.64 13.208 2.712 ;
     RECT  13.093 4.368 13.208 5.736 ;
     RECT  13.093 8.496 13.208 8.568 ;
     RECT  12.38 9.648 13.208 9.768 ;
     RECT  13.093 10.848 13.208 11.976 ;
     RECT  12.013 15.408 13.208 15.432 ;
     RECT  13.093 17.184 13.208 17.208 ;
     RECT  13.129 18.192 13.208 18.216 ;
     RECT  13.013 19.344 13.208 21.192 ;
     RECT  12.229 22.752 13.208 27.912 ;
     RECT  12.997 29.04 13.208 30.12 ;
     RECT  13.208 2.148 13.312 30.12 ;
     RECT  13.312 2.148 13.504 27.912 ;
     RECT  13.165 0.144 13.525 0.264 ;
     RECT  13.504 2.148 13.561 4.008 ;
     RECT  13.525 0.048 13.597 0.264 ;
     RECT  13.504 17.04 13.601 17.208 ;
     RECT  13.504 12.528 13.619 13.704 ;
     RECT  13.504 18.192 13.619 19.656 ;
     RECT  13.561 1.728 13.633 4.008 ;
     RECT  13.601 17.04 13.681 17.112 ;
     RECT  13.633 1.68 13.741 4.008 ;
     RECT  13.504 5.04 13.811 8.52 ;
     RECT  13.811 5.088 13.859 8.52 ;
     RECT  13.597 0.048 13.909 0.552 ;
     RECT  13.741 1.536 13.909 4.008 ;
     RECT  13.619 12.528 13.961 13.128 ;
     RECT  13.504 9.648 14.099 10.296 ;
     RECT  14.099 9.648 14.141 9.672 ;
     RECT  13.859 5.088 14.213 8.472 ;
     RECT  13.312 29.04 14.281 30.12 ;
     RECT  14.213 5.088 14.285 6.84 ;
     RECT  13.681 17.088 14.465 17.112 ;
     RECT  13.504 15.12 14.501 16.056 ;
     RECT  13.909 0.048 14.533 4.008 ;
     RECT  13.961 12.528 14.617 12.552 ;
     RECT  14.285 5.088 14.675 6.6 ;
     RECT  14.281 28.992 14.675 30.12 ;
     RECT  14.675 5.088 14.723 6.36 ;
     RECT  14.501 15.12 14.725 16.008 ;
     RECT  14.713 17.136 14.797 17.16 ;
     RECT  14.675 28.992 14.812 30.024 ;
     RECT  13.619 18.192 14.813 19.128 ;
     RECT  13.504 20.928 14.813 27.912 ;
     RECT  14.813 18.192 14.821 27.912 ;
     RECT  14.812 28.992 14.821 29.976 ;
     RECT  14.821 18.192 15.059 29.976 ;
     RECT  15.059 19.92 15.107 29.976 ;
     RECT  14.725 15.12 15.113 15.144 ;
     RECT  14.723 5.616 15.185 6.36 ;
     RECT  14.893 10.8 15.293 10.824 ;
     RECT  14.533 0.048 15.401 4.104 ;
     RECT  15.185 5.616 15.401 6.264 ;
     RECT  15.107 21.648 15.473 29.976 ;
     RECT  14.213 7.92 15.493 8.472 ;
     RECT  15.493 7.92 15.509 8.52 ;
     RECT  15.509 8.496 15.58 8.52 ;
     RECT  15.401 0.048 15.617 3.576 ;
     RECT  15.059 18.192 15.685 18.312 ;
     RECT  15.289 14.256 15.689 14.568 ;
     RECT  15.473 22.176 15.689 29.976 ;
     RECT  15.617 0.096 15.725 3.576 ;
     RECT  15.685 13.104 15.797 13.128 ;
     RECT  15.685 8.544 15.827 9.096 ;
     RECT  15.541 7.44 15.905 7.464 ;
     RECT  15.725 0.096 15.971 2.952 ;
     RECT  15.325 11.952 15.973 11.976 ;
     RECT  15.827 8.544 15.977 8.568 ;
     RECT  15.893 14.112 15.977 14.136 ;
     RECT  15.973 11.952 16.06 12.936 ;
     RECT  15.971 0.096 16.085 2.856 ;
     RECT  15.689 22.272 16.193 29.976 ;
     RECT  15.685 17.472 16.261 18.312 ;
     RECT  15.107 19.92 16.268 19.944 ;
     RECT  16.153 21.12 16.268 21.144 ;
     RECT  16.193 22.656 16.307 29.976 ;
     RECT  16.307 22.752 16.357 29.976 ;
     RECT  16.085 0.144 16.373 2.856 ;
     RECT  15.401 5.616 16.645 5.736 ;
     RECT  16.268 19.92 16.645 21.144 ;
     RECT  16.621 16.128 16.693 16.152 ;
     RECT  16.261 17.472 16.693 18.744 ;
     RECT  16.645 5.04 16.732 5.736 ;
     RECT  16.789 8.832 16.876 8.856 ;
     RECT  16.693 16.128 16.933 18.744 ;
     RECT  16.732 5.088 16.979 5.736 ;
     RECT  16.357 22.752 16.981 30.072 ;
     RECT  16.933 15.984 17.029 18.744 ;
     RECT  16.06 11.952 17.077 11.976 ;
     RECT  16.979 5.712 17.084 5.736 ;
     RECT  17.084 5.712 17.117 6.504 ;
     RECT  17.077 11.952 17.123 12.504 ;
     RECT  17.117 5.712 17.129 6.84 ;
     RECT  16.373 0.144 17.219 2.328 ;
     RECT  17.029 15.984 17.228 18.792 ;
     RECT  16.645 19.92 17.228 21.288 ;
     RECT  17.089 10.224 17.233 10.248 ;
     RECT  17.129 6.288 17.269 6.84 ;
     RECT  17.233 10.176 17.305 10.248 ;
     RECT  17.123 12.48 17.305 12.504 ;
     RECT  17.228 15.984 17.315 21.288 ;
     RECT  17.315 19.968 17.377 21.288 ;
     RECT  16.981 22.752 17.377 30.12 ;
     RECT  17.305 10.176 17.411 10.296 ;
     RECT  17.333 7.968 17.417 7.992 ;
     RECT  17.269 6.288 17.525 6.888 ;
     RECT  17.219 2.304 17.557 2.328 ;
     RECT  17.305 12.48 17.597 13.08 ;
     RECT  17.377 19.968 17.677 30.12 ;
     RECT  17.315 15.984 17.989 18.84 ;
     RECT  17.219 0.144 18.241 1.272 ;
     RECT  17.557 2.304 18.241 2.904 ;
     RECT  17.525 6.288 18.277 6.312 ;
     RECT  17.989 15.456 18.277 18.84 ;
     RECT  17.677 19.968 18.277 30.024 ;
     RECT  18.277 15.456 18.341 30.024 ;
     RECT  17.737 9.12 18.385 9.144 ;
     RECT  18.241 0.144 18.469 2.904 ;
     RECT  18.469 0.144 18.608 3.432 ;
     RECT  18.277 5.424 18.608 6.312 ;
     RECT  18.373 7.392 18.608 7.416 ;
     RECT  18.385 8.496 18.608 9.144 ;
     RECT  17.411 10.272 18.608 10.296 ;
     RECT  17.597 13.056 18.608 13.08 ;
     RECT  18.341 14.832 18.608 30.024 ;
     RECT  18.608 0.144 18.904 30.024 ;
     RECT  18.904 16.848 19.429 30.024 ;
     RECT  18.904 0.144 19.571 3.96 ;
     RECT  18.904 6.864 19.667 15.72 ;
     RECT  19.571 3.936 19.715 3.96 ;
     RECT  19.571 0.144 19.804 2.904 ;
     RECT  19.667 6.864 19.897 8.856 ;
     RECT  19.925 4.224 20.009 4.824 ;
     RECT  19.667 10.032 20.041 15.72 ;
     RECT  19.429 16.848 20.041 30.072 ;
     RECT  19.804 0.144 20.449 1.752 ;
     RECT  20.041 10.032 20.531 30.072 ;
     RECT  20.009 4.224 20.621 4.296 ;
     RECT  19.897 6.672 20.828 8.856 ;
     RECT  20.531 10.032 20.837 30.024 ;
     RECT  19.804 2.88 20.917 2.904 ;
     RECT  20.773 5.472 20.965 5.496 ;
     RECT  20.828 6.528 20.965 8.856 ;
     RECT  20.621 4.224 21.085 4.248 ;
     RECT  20.965 5.472 21.109 8.856 ;
     RECT  21.109 5.472 21.229 8.952 ;
     RECT  20.837 10.032 21.229 10.872 ;
     RECT  20.917 2.784 21.349 2.904 ;
     RECT  21.349 2.304 21.637 2.904 ;
     RECT  21.085 3.936 21.637 4.248 ;
     RECT  20.449 0.144 21.653 1.176 ;
     RECT  21.637 2.304 21.661 4.248 ;
     RECT  21.229 5.472 21.661 10.872 ;
     RECT  21.661 2.304 21.829 10.872 ;
     RECT  20.837 11.856 21.829 30.024 ;
     RECT  21.653 0.144 21.913 1.272 ;
     RECT  21.829 2.304 21.913 30.024 ;
     RECT  21.913 0.144 22.061 30.024 ;
     RECT  22.061 12.528 22.165 30.024 ;
     RECT  22.061 0.144 22.205 11.544 ;
     RECT  22.165 12.528 22.249 30.12 ;
     RECT  22.205 0.144 22.529 11.448 ;
     RECT  22.529 0.144 22.54 8.952 ;
     RECT  22.249 12.528 22.573 30.072 ;
     RECT  22.54 0.144 22.709 4.104 ;
     RECT  22.54 5.136 22.787 8.952 ;
     RECT  22.573 12.528 22.825 30.024 ;
     RECT  22.825 28.512 22.835 30.024 ;
     RECT  22.709 0.144 23.069 1.224 ;
     RECT  22.529 10.224 23.245 11.448 ;
     RECT  22.835 28.512 23.267 28.536 ;
     RECT  22.835 29.568 23.329 30.024 ;
     RECT  23.245 10.224 23.425 11.544 ;
     RECT  22.825 12.528 23.425 27.528 ;
     RECT  22.709 2.256 23.677 4.104 ;
     RECT  22.787 5.136 23.677 8.856 ;
     RECT  23.677 2.256 23.749 8.856 ;
     RECT  23.425 10.224 23.893 27.528 ;
     RECT  23.749 2.256 23.965 9.144 ;
     RECT  23.893 10.224 23.965 28.248 ;
     RECT  23.965 2.256 24.008 28.248 ;
     RECT  24.008 2.148 24.277 28.248 ;
     RECT  23.329 29.568 24.325 29.88 ;
     RECT  23.069 0.144 24.364 1.176 ;
     RECT  24.277 2.148 24.365 28.536 ;
     RECT  24.364 0.096 24.389 1.176 ;
     RECT  24.365 2.148 24.389 27.912 ;
     RECT  24.325 29.568 24.469 29.976 ;
     RECT  24.389 0.096 24.508 27.912 ;
     RECT  24.469 29.568 24.541 30.072 ;
     RECT  24.541 29.04 24.755 30.072 ;
     RECT  24.508 0.096 24.761 9.144 ;
     RECT  24.761 0.144 24.833 9.144 ;
     RECT  24.755 29.664 24.899 30.072 ;
     RECT  24.833 0.192 25.036 9.144 ;
     RECT  25.036 0.192 25.043 4.584 ;
     RECT  24.508 10.32 25.165 27.912 ;
     RECT  25.036 5.568 25.657 9.144 ;
     RECT  25.165 10.32 25.657 27.336 ;
     RECT  24.899 29.712 25.705 30.072 ;
     RECT  25.043 0.192 25.813 4.296 ;
     RECT  25.381 28.512 25.945 28.536 ;
     RECT  25.705 29.712 25.945 30.024 ;
     RECT  25.813 0.096 26.117 4.296 ;
     RECT  25.657 5.568 26.117 27.336 ;
     RECT  26.117 0.096 26.161 27.336 ;
     RECT  26.161 0.096 26.201 27.432 ;
     RECT  26.201 5.616 26.332 27.432 ;
     RECT  26.332 5.712 26.405 27.432 ;
     RECT  26.201 0.096 26.435 4.296 ;
     RECT  26.435 0.096 26.531 4.008 ;
     RECT  26.405 5.712 26.581 27.528 ;
     RECT  25.945 28.512 26.581 30.024 ;
     RECT  26.581 5.712 26.633 30.024 ;
     RECT  26.633 5.712 26.668 28.632 ;
     RECT  26.633 29.664 26.674 30.024 ;
     RECT  26.668 7.968 26.771 27.528 ;
     RECT  26.674 29.664 26.771 30.12 ;
     RECT  26.531 2.304 26.993 4.008 ;
     RECT  26.771 14.016 27.059 27.48 ;
     RECT  27.059 14.256 27.155 27.48 ;
     RECT  26.771 7.968 27.289 13.032 ;
     RECT  26.668 5.712 27.301 6.84 ;
     RECT  26.531 0.096 27.353 1.224 ;
     RECT  27.155 14.256 27.353 17.208 ;
     RECT  27.301 5.088 27.398 6.84 ;
     RECT  27.353 14.256 27.433 15.384 ;
     RECT  27.353 16.416 27.443 17.112 ;
     RECT  27.398 5.136 27.637 6.84 ;
     RECT  27.155 18.672 27.733 27.48 ;
     RECT  26.668 28.512 27.733 28.632 ;
     RECT  27.733 18.672 27.745 28.632 ;
     RECT  26.771 29.664 27.745 30.072 ;
     RECT  27.353 0.096 27.893 1.176 ;
     RECT  27.637 5.136 27.925 6.888 ;
     RECT  27.289 7.968 27.925 11.448 ;
     RECT  27.289 12.48 28.069 13.032 ;
     RECT  27.433 14.256 28.069 15.144 ;
     RECT  27.745 18.672 28.261 30.072 ;
     RECT  27.925 5.136 28.393 11.448 ;
     RECT  28.261 18.24 28.405 30.072 ;
     RECT  27.443 16.416 28.429 17.064 ;
     RECT  28.405 18.144 28.429 30.072 ;
     RECT  28.393 4.992 28.453 11.448 ;
     RECT  28.069 12.48 28.453 15.144 ;
     RECT  26.993 2.304 28.501 3.96 ;
     RECT  28.453 4.992 28.501 15.144 ;
     RECT  27.893 0.096 28.649 0.552 ;
     RECT  28.501 1.776 28.757 15.144 ;
     RECT  28.757 2.148 28.969 15.144 ;
     RECT  28.429 16.416 28.969 30.072 ;
     RECT  28.649 0.144 29.077 0.552 ;
     RECT  28.969 2.148 29.365 30.072 ;
     RECT  29.077 0.144 29.413 0.6 ;
     RECT  29.365 2.148 29.512 30.12 ;
     RECT  29.512 2.304 29.843 30.12 ;
     RECT  29.413 0.144 30.052 1.176 ;
     RECT  29.843 4.56 30.083 30.12 ;
     RECT  30.052 0.144 30.181 1.224 ;
     RECT  30.083 8.544 30.241 30.12 ;
     RECT  30.241 8.544 30.341 28.536 ;
     RECT  30.341 9.744 30.557 28.536 ;
     RECT  30.241 29.568 30.601 30.12 ;
     RECT  30.083 4.56 30.629 7.464 ;
     RECT  30.557 10.752 30.665 28.536 ;
     RECT  30.665 25.008 30.673 28.536 ;
     RECT  30.341 8.544 30.809 8.568 ;
     RECT  30.181 0.096 30.977 1.224 ;
     RECT  30.629 5.04 30.989 7.464 ;
     RECT  30.601 29.568 30.995 30.072 ;
     RECT  30.977 0.096 31.061 1.272 ;
     RECT  30.989 5.04 31.061 6.312 ;
     RECT  30.665 10.752 31.091 23.88 ;
     RECT  31.091 11.376 31.187 23.88 ;
     RECT  31.187 11.808 31.331 23.88 ;
     RECT  30.995 29.664 31.331 30.072 ;
     RECT  31.331 11.808 31.349 17.496 ;
     RECT  31.349 12.336 31.427 17.496 ;
     RECT  30.989 7.44 31.445 7.464 ;
     RECT  31.445 7.44 31.501 7.992 ;
     RECT  31.501 7.968 31.529 7.992 ;
     RECT  31.331 29.808 31.597 30.072 ;
     RECT  31.331 18.816 31.709 23.88 ;
     RECT  30.673 25.056 31.765 28.536 ;
     RECT  31.709 19.392 31.921 23.88 ;
     RECT  31.427 12.336 31.933 16.536 ;
     RECT  31.921 19.392 31.993 23.976 ;
     RECT  31.765 25.008 31.993 28.536 ;
     RECT  31.993 19.392 32.053 28.536 ;
     RECT  31.933 12.336 32.213 13.656 ;
     RECT  31.061 0.096 32.249 1.176 ;
     RECT  31.933 14.736 32.249 16.536 ;
     RECT  32.249 14.88 32.285 16.536 ;
     RECT  31.597 29.808 32.3 30.12 ;
     RECT  29.843 2.304 32.309 3.432 ;
     RECT  32.213 13.632 32.339 13.656 ;
     RECT  32.3 29.712 32.389 30.12 ;
     RECT  32.309 2.304 32.393 3.96 ;
     RECT  32.285 14.88 32.401 15.432 ;
     RECT  32.389 29.664 32.435 30.12 ;
     RECT  32.285 16.512 32.465 16.536 ;
     RECT  32.053 19.392 32.533 28.632 ;
     RECT  32.533 17.616 32.54 17.64 ;
     RECT  32.54 16.56 32.62 17.64 ;
     RECT  32.62 16.56 32.627 16.968 ;
     RECT  32.425 10.896 32.629 10.92 ;
     RECT  32.393 2.304 32.641 3 ;
     RECT  32.213 12.336 32.641 12.552 ;
     RECT  32.249 0.144 32.677 1.176 ;
     RECT  32.641 12 32.681 12.552 ;
     RECT  31.061 5.136 32.713 6.312 ;
     RECT  32.533 19.392 32.713 28.68 ;
     RECT  32.713 18.816 32.717 28.68 ;
     RECT  32.627 16.56 32.753 16.584 ;
     RECT  32.435 29.664 32.753 30.072 ;
     RECT  32.677 0.144 32.773 1.224 ;
     RECT  32.641 2.208 32.773 3 ;
     RECT  32.717 18.816 32.773 19.368 ;
     RECT  32.401 14.88 32.789 14.904 ;
     RECT  32.773 18 32.86 19.368 ;
     RECT  32.629 10.464 33.061 10.92 ;
     RECT  32.717 20.448 33.076 28.68 ;
     RECT  32.753 29.664 33.076 30.024 ;
     RECT  33.076 20.448 33.077 30.024 ;
     RECT  32.773 0.144 33.107 3 ;
     RECT  33.061 10.464 33.145 10.968 ;
     RECT  32.485 8.544 33.157 8.568 ;
     RECT  33.107 0.144 33.185 2.904 ;
     RECT  33.145 10.272 33.293 10.968 ;
     RECT  32.713 5.136 33.317 6.696 ;
     RECT  33.157 8.544 33.329 9.144 ;
     RECT  33.329 8.544 33.356 8.568 ;
     RECT  33.317 5.136 33.401 6.888 ;
     RECT  33.356 7.872 33.443 8.568 ;
     RECT  32.86 18.528 33.484 19.368 ;
     RECT  32.681 12 33.653 12.408 ;
     RECT  33.605 15.744 33.689 15.768 ;
     RECT  33.484 19.344 33.721 19.368 ;
     RECT  33.077 20.448 33.721 27.912 ;
     RECT  33.721 19.344 33.724 27.912 ;
     RECT  33.401 5.136 33.733 5.976 ;
     RECT  33.077 29.04 33.925 30.024 ;
     RECT  33.973 16.176 34.001 16.536 ;
     RECT  34.001 16.176 34.045 17.112 ;
     RECT  34.045 16.176 34.069 17.352 ;
     RECT  33.185 0.144 34.165 1.32 ;
     RECT  33.185 2.304 34.165 2.856 ;
     RECT  33.925 29.04 34.289 30.072 ;
     RECT  34.289 29.04 34.297 30.12 ;
     RECT  33.733 4.656 34.333 5.976 ;
     RECT  33.685 12.816 34.364 13.128 ;
     RECT  34.297 28.944 34.373 30.12 ;
     RECT  34.333 14.88 34.441 14.904 ;
     RECT  34.165 0.144 34.501 2.856 ;
     RECT  33.443 8.496 34.501 8.568 ;
     RECT  33.724 19.632 34.508 27.912 ;
     RECT  34.373 28.944 34.508 30.072 ;
     RECT  34.333 4.032 34.549 5.976 ;
     RECT  34.501 0.096 34.585 2.856 ;
     RECT  34.549 3.888 34.585 5.976 ;
     RECT  34.364 12.816 34.597 13.56 ;
     RECT  34.441 14.784 34.597 14.904 ;
     RECT  34.508 19.632 34.693 30.072 ;
     RECT  34.585 0.096 34.808 5.976 ;
     RECT  33.877 7.296 34.808 7.464 ;
     RECT  34.501 8.496 34.808 9 ;
     RECT  33.293 10.272 34.808 10.872 ;
     RECT  34.597 12.816 34.808 14.904 ;
     RECT  34.069 16.176 34.808 18.024 ;
     RECT  34.693 19.344 34.808 30.072 ;
     RECT  34.808 0.096 34.912 30.072 ;
     RECT  34.912 0.096 35.104 27.912 ;
     RECT  35.104 0.096 35.267 7.464 ;
     RECT  34.912 29.04 35.353 30.072 ;
     RECT  35.104 8.496 35.411 9.72 ;
     RECT  35.104 19.536 35.453 27.912 ;
     RECT  35.104 14.208 35.497 14.232 ;
     RECT  35.267 4.656 35.597 7.464 ;
     RECT  35.104 15.264 35.603 17.64 ;
     RECT  35.603 15.264 35.651 16.968 ;
     RECT  35.453 19.632 35.661 27.912 ;
     RECT  35.104 10.992 35.705 11.016 ;
     RECT  35.651 15.408 35.747 16.968 ;
     RECT  35.597 6.864 35.777 7.464 ;
     RECT  35.353 29.04 35.849 30.024 ;
     RECT  35.777 6.864 35.885 7.368 ;
     RECT  35.411 8.976 35.993 9.72 ;
     RECT  35.747 15.456 36.035 16.968 ;
     RECT  35.885 6.96 36.101 7.368 ;
     RECT  35.597 4.656 36.173 5.736 ;
     RECT  36.173 5.664 36.179 5.736 ;
     RECT  35.267 0.096 36.277 3.336 ;
     RECT  35.849 29.376 36.413 30.024 ;
     RECT  36.277 0.096 36.425 3.432 ;
     RECT  36.035 16.416 36.425 16.968 ;
     RECT  36.425 0.144 36.457 3.432 ;
     RECT  36.413 29.376 36.497 30.12 ;
     RECT  36.497 29.376 36.508 30.072 ;
     RECT  36.421 11.952 36.515 11.976 ;
     RECT  36.425 16.464 36.569 16.968 ;
     RECT  36.457 0.144 36.605 4.2 ;
     RECT  35.993 8.976 36.629 9.096 ;
     RECT  36.629 8.544 36.713 9.096 ;
     RECT  36.569 16.512 36.781 16.968 ;
     RECT  36.716 15.312 36.803 15.336 ;
     RECT  36.781 16.512 36.853 17.112 ;
     RECT  36.757 18.144 36.853 18.168 ;
     RECT  35.661 20.016 36.853 27.912 ;
     RECT  36.101 6.96 36.889 6.984 ;
     RECT  36.713 9.072 36.937 9.096 ;
     RECT  36.853 16.512 37.043 18.168 ;
     RECT  36.179 5.664 37.045 5.688 ;
     RECT  36.853 20.016 37.093 28.056 ;
     RECT  36.605 0.144 37.109 4.104 ;
     RECT  37.093 19.92 37.18 28.056 ;
     RECT  37.043 16.512 37.187 17.496 ;
     RECT  36.508 29.664 37.187 30.072 ;
     RECT  37.187 16.56 37.217 17.496 ;
     RECT  36.889 6.864 37.321 6.984 ;
     RECT  37.18 20.544 37.325 28.056 ;
     RECT  37.325 20.544 37.369 27.864 ;
     RECT  37.321 6.384 37.381 6.984 ;
     RECT  37.381 6.384 37.469 7.368 ;
     RECT  37.109 0.144 37.525 3.912 ;
     RECT  37.045 12 37.667 12.552 ;
     RECT  37.667 12.528 37.813 12.552 ;
     RECT  37.369 20.736 37.907 27.864 ;
     RECT  37.388 18.672 37.925 18.696 ;
     RECT  37.469 6.384 37.937 6.696 ;
     RECT  37.925 18.672 38.009 19.368 ;
     RECT  37.187 29.712 38.045 30.072 ;
     RECT  37.525 0.096 38.077 3.912 ;
     RECT  37.907 21.12 38.099 27.864 ;
     RECT  38.077 0.096 38.149 4.104 ;
     RECT  38.099 21.504 38.153 27.864 ;
     RECT  38.045 29.76 38.153 30.072 ;
     RECT  37.937 6.384 38.197 6.408 ;
     RECT  37.217 16.56 38.197 17.16 ;
     RECT  38.153 29.76 38.243 29.976 ;
     RECT  37.621 14.784 38.245 14.808 ;
     RECT  38.153 21.648 38.293 27.864 ;
     RECT  38.213 9.696 38.297 9.72 ;
     RECT  37.813 12.528 38.405 13.224 ;
     RECT  38.243 29.904 38.435 29.976 ;
     RECT  38.149 0.096 38.545 4.488 ;
     RECT  38.545 0.096 38.657 4.584 ;
     RECT  38.657 0.24 38.693 4.584 ;
     RECT  38.405 13.104 38.725 13.224 ;
     RECT  38.245 14.64 38.725 14.808 ;
     RECT  38.725 13.104 38.773 14.808 ;
     RECT  38.197 16.368 38.773 17.16 ;
     RECT  38.009 18.672 38.773 18.792 ;
     RECT  38.005 11.376 38.861 11.4 ;
     RECT  38.773 13.104 38.873 17.16 ;
     RECT  38.773 18.192 38.873 18.792 ;
     RECT  38.821 19.92 38.908 19.944 ;
     RECT  38.861 10.848 38.941 11.4 ;
     RECT  38.941 10.848 38.977 11.448 ;
     RECT  38.873 13.104 39.053 13.416 ;
     RECT  38.435 29.952 39.053 29.976 ;
     RECT  38.873 14.544 39.059 17.16 ;
     RECT  38.977 10.704 39.121 11.448 ;
     RECT  39.059 15.984 39.161 17.16 ;
     RECT  38.293 21.648 39.161 28.776 ;
     RECT  39.161 21.648 39.197 27.432 ;
     RECT  38.873 18.768 39.26 18.792 ;
     RECT  38.197 6.288 39.349 6.408 ;
     RECT  39.349 6.288 39.373 6.552 ;
     RECT  38.693 0.336 39.449 4.584 ;
     RECT  39.121 10.32 39.541 11.448 ;
     RECT  39.449 0.48 39.557 4.584 ;
     RECT  39.373 6.288 39.877 6.84 ;
     RECT  39.769 9.12 39.877 9.144 ;
     RECT  39.541 10.32 39.877 11.976 ;
     RECT  39.557 0.816 39.881 4.584 ;
     RECT  39.877 5.616 39.925 6.84 ;
     RECT  39.733 21.168 39.925 21.192 ;
     RECT  39.877 9.12 39.973 11.976 ;
     RECT  39.053 13.392 39.973 13.416 ;
     RECT  39.059 14.544 39.973 14.952 ;
     RECT  39.26 18.768 39.973 19.368 ;
     RECT  39.925 21.12 39.973 21.192 ;
     RECT  39.881 0.816 40.205 0.984 ;
     RECT  39.881 2.148 40.208 4.584 ;
     RECT  39.925 5.616 40.208 7.752 ;
     RECT  39.973 9.12 40.208 12.264 ;
     RECT  39.973 13.392 40.208 14.952 ;
     RECT  39.161 15.984 40.208 16.824 ;
     RECT  39.973 18.768 40.208 21.192 ;
     RECT  39.197 22.176 40.208 27.432 ;
     RECT  39.161 28.752 40.208 28.776 ;
     RECT  40.208 2.148 40.312 28.776 ;
     RECT  40.205 0.864 40.385 0.984 ;
     RECT  40.385 0.864 40.457 0.888 ;
     RECT  40.312 2.418 40.504 28.776 ;
     RECT  40.504 3.072 40.601 3.096 ;
     RECT  40.504 6.24 40.643 7.752 ;
     RECT  40.504 11.904 40.643 11.928 ;
     RECT  40.504 21.936 40.643 23.976 ;
     RECT  40.504 25.296 40.643 27.432 ;
     RECT  40.643 27.36 40.67 27.432 ;
     RECT  40.67 27.36 40.787 27.384 ;
     RECT  40.504 15.984 40.883 17.112 ;
     RECT  40.504 19.872 40.883 20.568 ;
     RECT  40.643 21.936 40.889 23.448 ;
     RECT  40.643 25.296 40.924 26.376 ;
     RECT  40.883 20.016 40.925 20.568 ;
     RECT  40.504 18.192 40.979 18.648 ;
     RECT  40.889 21.936 40.979 23.4 ;
     RECT  40.643 6.24 40.997 6.84 ;
     RECT  40.924 25.536 40.997 26.376 ;
     RECT  40.504 9.36 41.02 10.344 ;
     RECT  40.997 26.352 41.033 26.376 ;
     RECT  40.997 6.24 41.068 6.264 ;
     RECT  40.504 28.752 41.069 28.776 ;
     RECT  40.979 23.376 41.285 23.4 ;
     RECT  40.883 15.984 41.429 16.824 ;
     RECT  40.504 13.008 41.452 13.032 ;
     RECT  40.925 20.544 41.465 20.568 ;
     RECT  41.02 9.6 41.5 10.344 ;
     RECT  41.5 9.6 41.555 9.624 ;
     RECT  41.497 18.816 41.581 18.84 ;
     RECT  40.979 21.936 41.969 21.96 ;
     RECT  42.253 14.784 42.337 14.808 ;
     RECT  42.565 23.088 42.653 23.112 ;
     RECT  42.397 3.072 42.757 3.096 ;
     RECT  42.757 3.072 42.829 3.24 ;
     RECT  42.829 2.88 42.841 3.24 ;
     RECT  42.757 6.192 42.841 6.216 ;
     RECT  42.757 16.464 42.841 16.488 ;
     RECT  42.841 2.88 42.905 3.096 ;
     RECT  42.905 2.88 43.049 2.904 ;
     RECT  43.333 25.44 43.42 25.464 ;
     RECT  43.657 26.736 43.829 26.76 ;
     RECT  43.829 26.736 43.907 26.856 ;
     RECT  43.907 26.832 43.913 26.856 ;
     RECT  45.608 2.148 45.712 28.092 ;
     RECT  45.712 2.418 45.904 27.822 ;
    LAYER M5 ;
     RECT  13.68 0.016 38.28 0.181 ;
     RECT  13.68 0.181 38.904 0.309 ;
     RECT  13.68 0.309 39.336 0.437 ;
     RECT  13.68 0.437 39.816 0.501 ;
     RECT  13.68 0.501 40.056 2.137 ;
     RECT  13.2 2.137 40.32 2.339 ;
     RECT  2.4 2.137 2.52 2.407 ;
     RECT  7.8 2.137 7.92 2.407 ;
     RECT  17.328 2.339 40.32 2.407 ;
     RECT  45.6 2.137 45.72 2.407 ;
     RECT  42.768 3.205 42.792 3.371 ;
     RECT  13.2 2.339 15.96 4.357 ;
     RECT  13.104 4.357 15.96 5.029 ;
     RECT  17.328 2.407 40.512 5.029 ;
     RECT  10.224 5.077 10.248 5.227 ;
     RECT  13.104 5.029 40.512 5.621 ;
     RECT  11.28 5.173 11.304 5.675 ;
     RECT  12.528 5.621 40.512 5.747 ;
     RECT  16.944 5.747 40.512 6.197 ;
     RECT  42.768 6.181 42.792 6.265 ;
     RECT  16.944 6.197 41.016 6.285 ;
     RECT  16.944 6.285 40.512 7.699 ;
     RECT  16.944 7.699 40.632 7.787 ;
     RECT  7.8 2.407 8.112 7.797 ;
     RECT  10.896 6.805 10.92 7.797 ;
     RECT  7.8 7.797 8.904 7.885 ;
     RECT  10.608 7.797 10.92 7.907 ;
     RECT  16.944 7.787 40.512 8.003 ;
     RECT  13.104 5.747 15.96 8.579 ;
     RECT  16.944 8.003 30.984 8.821 ;
     RECT  11.952 8.341 11.976 8.875 ;
     RECT  32.352 8.003 40.512 9.011 ;
     RECT  13.2 8.579 15.816 9.107 ;
     RECT  16.8 8.821 30.984 9.131 ;
     RECT  9.744 9.141 9.768 9.229 ;
     RECT  34.8 9.011 40.512 9.349 ;
     RECT  34.8 9.349 40.968 9.589 ;
     RECT  10.848 7.907 10.92 9.637 ;
     RECT  13.2 9.107 15.72 9.717 ;
     RECT  34.8 9.589 41.544 9.731 ;
     RECT  12.432 9.717 15.72 9.805 ;
     RECT  32.352 9.011 33.72 10.293 ;
     RECT  34.8 9.731 35.736 10.293 ;
     RECT  16.944 9.131 30.984 10.307 ;
     RECT  38.88 9.731 41.544 10.381 ;
     RECT  18.384 10.307 30.984 10.741 ;
     RECT  10.848 9.637 11.256 10.837 ;
     RECT  32.352 10.293 35.736 10.883 ;
     RECT  32.352 10.883 33.72 10.979 ;
     RECT  13.2 9.805 15.72 11.173 ;
     RECT  10.848 10.837 11.928 11.253 ;
     RECT  10.656 11.253 11.928 11.363 ;
     RECT  18.384 10.741 31.08 11.365 ;
     RECT  36.864 9.731 37.848 11.365 ;
     RECT  38.88 10.381 40.512 11.365 ;
     RECT  10.656 11.363 11.256 11.459 ;
     RECT  36.864 11.365 40.512 11.459 ;
     RECT  18.384 11.365 31.176 11.797 ;
     RECT  39.552 11.459 40.512 11.829 ;
     RECT  41.52 10.381 41.544 11.829 ;
     RECT  39.552 11.829 41.544 11.939 ;
     RECT  34.8 10.883 35.736 11.941 ;
     RECT  36.864 11.459 38.088 11.941 ;
     RECT  34.8 11.941 38.088 12.025 ;
     RECT  18.384 11.797 31.272 12.277 ;
     RECT  32.352 10.979 32.616 12.277 ;
     RECT  18.384 12.277 32.616 12.373 ;
     RECT  33.696 10.979 33.72 12.373 ;
     RECT  18.384 12.373 33.72 12.459 ;
     RECT  10.848 11.459 11.256 12.469 ;
     RECT  10.848 12.469 11.976 12.517 ;
     RECT  10.224 12.517 11.976 12.553 ;
     RECT  10.224 12.553 11.256 12.715 ;
     RECT  13.104 11.173 15.72 12.883 ;
     RECT  16.944 10.307 17.4 12.883 ;
     RECT  13.104 12.883 17.4 12.971 ;
     RECT  39.552 11.939 40.512 12.981 ;
     RECT  41.52 11.939 41.544 12.981 ;
     RECT  16.944 12.971 17.4 13.011 ;
     RECT  18.384 12.459 32.616 13.011 ;
     RECT  39.552 12.981 41.544 13.069 ;
     RECT  16.944 13.011 32.616 13.099 ;
     RECT  33.696 12.459 33.72 13.139 ;
     RECT  34.8 12.025 35.736 13.173 ;
     RECT  34.416 13.173 35.736 13.571 ;
     RECT  13.104 12.971 15.72 14.063 ;
     RECT  13.104 14.063 15.96 14.147 ;
     RECT  13.104 14.147 15.336 14.291 ;
     RECT  39.552 13.069 40.512 14.533 ;
     RECT  36.864 12.025 38.088 14.611 ;
     RECT  39.168 14.533 40.512 14.611 ;
     RECT  41.52 13.069 41.544 14.739 ;
     RECT  41.52 14.739 42.312 14.827 ;
     RECT  36.864 14.611 40.512 15.301 ;
     RECT  16.944 13.099 17.4 15.407 ;
     RECT  18.384 13.099 32.616 15.407 ;
     RECT  34.608 13.571 35.736 15.413 ;
     RECT  36.768 15.301 40.512 15.413 ;
     RECT  34.608 15.413 40.512 15.733 ;
     RECT  33.648 15.733 40.512 15.817 ;
     RECT  34.176 15.817 40.512 15.955 ;
     RECT  41.52 14.827 41.544 15.955 ;
     RECT  13.104 14.291 14.712 16.019 ;
     RECT  34.176 15.955 41.544 16.403 ;
     RECT  34.176 16.403 38.328 16.491 ;
     RECT  42.768 15.989 42.792 16.499 ;
     RECT  16.944 15.407 32.616 16.693 ;
     RECT  16.8 16.693 32.616 17.003 ;
     RECT  13.104 16.019 13.848 17.013 ;
     RECT  34.176 16.491 38.088 17.077 ;
     RECT  34.032 17.077 38.088 17.123 ;
     RECT  13.104 17.013 14.76 17.171 ;
     RECT  10.848 12.715 11.256 17.557 ;
     RECT  16.8 17.003 32.568 17.651 ;
     RECT  10.848 17.557 11.4 17.699 ;
     RECT  18.6 17.651 32.568 17.973 ;
     RECT  11.232 17.699 11.4 18.037 ;
     RECT  15.696 17.461 15.72 18.037 ;
     RECT  16.8 17.651 17.4 18.037 ;
     RECT  34.032 17.123 36.888 18.133 ;
     RECT  38.064 17.123 38.088 18.143 ;
     RECT  39.552 16.403 41.544 18.143 ;
     RECT  13.104 17.171 13.848 18.181 ;
     RECT  15.696 18.037 17.4 18.181 ;
     RECT  11.232 18.037 11.592 18.275 ;
     RECT  13.104 18.181 17.4 18.275 ;
     RECT  14.784 18.275 17.4 18.283 ;
     RECT  18.6 17.973 32.808 18.479 ;
     RECT  34.032 18.133 37.032 18.479 ;
     RECT  18.6 18.479 37.032 18.613 ;
     RECT  38.064 18.143 41.544 18.613 ;
     RECT  18.6 18.613 41.544 18.697 ;
     RECT  33.648 18.697 41.544 18.707 ;
     RECT  16.704 18.283 17.4 18.709 ;
     RECT  18.6 18.697 32.616 18.709 ;
     RECT  37.968 18.707 41.544 18.851 ;
     RECT  13.104 18.275 13.512 19.603 ;
     RECT  13.104 19.603 13.608 19.691 ;
     RECT  33.648 18.707 36.888 19.893 ;
     RECT  37.968 18.851 40.968 19.893 ;
     RECT  13.104 19.691 13.512 19.923 ;
     RECT  11.568 18.275 11.592 19.957 ;
     RECT  11.232 19.957 11.592 20.011 ;
     RECT  13.056 19.923 13.512 20.011 ;
     RECT  11.232 20.011 11.256 20.291 ;
     RECT  16.704 18.709 32.616 20.437 ;
     RECT  33.648 19.893 40.968 20.437 ;
     RECT  14.784 18.283 15.72 20.499 ;
     RECT  16.704 20.437 40.968 20.499 ;
     RECT  13.104 20.011 13.512 20.947 ;
     RECT  14.784 20.499 40.968 20.947 ;
     RECT  13.104 20.947 40.968 21.109 ;
     RECT  12.672 21.109 40.968 21.203 ;
     RECT  9.408 21.237 9.432 21.325 ;
     RECT  13.104 21.203 40.968 21.355 ;
     RECT  12 21.599 12.024 21.683 ;
     RECT  10.8 21.061 10.824 21.732 ;
     RECT  13.104 21.355 15.72 22.549 ;
     RECT  16.704 21.355 40.968 22.549 ;
     RECT  9.936 23.187 9.96 23.275 ;
     RECT  42.576 23.059 42.6 23.275 ;
     RECT  13.104 22.549 40.968 23.893 ;
     RECT  11.472 22.597 11.496 25.475 ;
     RECT  43.344 25.397 43.368 25.485 ;
     RECT  0.144 14.901 0.168 25.621 ;
     RECT  0.048 25.621 0.168 25.667 ;
     RECT  0.048 25.667 0.072 25.859 ;
     RECT  13.008 23.893 40.968 26.339 ;
     RECT  13.008 26.339 40.824 26.425 ;
     RECT  43.872 26.725 43.896 26.867 ;
     RECT  13.008 26.425 40.776 27.395 ;
     RECT  13.008 27.395 40.632 27.443 ;
     RECT  2.4 2.407 2.712 27.833 ;
     RECT  7.8 7.885 8.112 27.833 ;
     RECT  40.2 27.443 40.512 27.833 ;
     RECT  45.6 2.407 45.912 27.833 ;
     RECT  13.008 27.443 38.808 27.961 ;
     RECT  2.4 27.833 2.52 28.103 ;
     RECT  7.8 27.833 7.92 28.103 ;
     RECT  40.2 27.833 40.32 28.103 ;
     RECT  45.6 27.833 45.72 28.103 ;
     RECT  13.008 27.961 38.424 29.939 ;
     RECT  13.008 29.939 38.328 30.131 ;
     RECT  13.728 30.131 38.328 30.224 ;
    LAYER M6 ;
     RECT  0.133 14.912 2.16 14.944 ;
     RECT  2.16 7.929 8.869 8.601 ;
     RECT  8.869 7.808 9.717 8.601 ;
     RECT  9.717 7.808 9.79 9.184 ;
     RECT  2.16 24.129 9.925 24.801 ;
     RECT  2.16 13.329 10.213 14.944 ;
     RECT  9.79 7.808 10.643 8.601 ;
     RECT  9.397 21.248 10.789 21.28 ;
     RECT  10.789 21.248 10.835 21.664 ;
     RECT  2.16 18.729 11.221 19.401 ;
     RECT  10.213 5.184 11.269 5.216 ;
     RECT  11.269 5.184 11.315 5.664 ;
     RECT  11.221 18.729 11.365 20 ;
     RECT  9.925 23.232 11.507 24.801 ;
     RECT  10.645 11.264 11.939 11.296 ;
     RECT  10.643 7.929 11.941 8.601 ;
     RECT  10.213 12.672 11.941 14.944 ;
     RECT  10.835 21.632 12.035 21.664 ;
     RECT  11.941 7.929 12.421 8.864 ;
     RECT  12.421 7.929 12.523 9.76 ;
     RECT  11.365 17.6 12.587 20 ;
     RECT  12.587 18.624 12.661 20 ;
     RECT  12.661 18.624 12.73 21.152 ;
     RECT  11.507 24.129 13.493 24.801 ;
     RECT  13.493 24 13.55 24.801 ;
     RECT  13.685 29.76 13.717 29.792 ;
     RECT  13.55 24 13.877 25.056 ;
     RECT  13.557 26.944 13.877 26.976 ;
     RECT  13.877 24 13.909 26.976 ;
     RECT  13.717 29.696 13.941 29.792 ;
     RECT  13.957 22.592 14.133 22.624 ;
     RECT  13.909 24 14.261 27.936 ;
     RECT  12.73 18.624 14.37 20 ;
     RECT  14.133 21.824 14.37 22.624 ;
     RECT  13.621 17.024 14.771 17.056 ;
     RECT  14.261 23.936 14.827 27.936 ;
     RECT  11.315 5.632 14.837 5.664 ;
     RECT  14.837 5.632 14.915 6.24 ;
     RECT  14.37 18.624 14.965 22.624 ;
     RECT  14.827 23.936 14.965 27.68 ;
     RECT  13.941 29.696 15.029 30.048 ;
     RECT  15.029 29.696 15.157 30.176 ;
     RECT  14.915 5.632 15.299 5.664 ;
     RECT  14.965 18.624 15.339 27.68 ;
     RECT  15.339 18.624 15.349 21.344 ;
     RECT  15.339 22.784 15.403 27.68 ;
     RECT  15.157 29.632 15.477 30.176 ;
     RECT  15.349 18.24 16.595 21.344 ;
     RECT  15.403 23.296 16.693 27.68 ;
     RECT  16.693 23.296 16.821 27.744 ;
     RECT  12.523 7.929 16.835 9.12 ;
     RECT  11.941 12.48 17.077 14.944 ;
     RECT  17.077 11.392 17.125 14.944 ;
     RECT  17.125 10.24 17.195 14.944 ;
     RECT  16.821 23.296 17.269 27.936 ;
     RECT  17.013 16.512 17.333 16.544 ;
     RECT  15.477 29.504 17.515 30.176 ;
     RECT  16.595 18.624 17.557 21.344 ;
     RECT  17.269 22.784 17.557 27.936 ;
     RECT  17.333 16.512 17.589 16.608 ;
     RECT  17.195 12.48 17.653 14.944 ;
     RECT  17.589 16.448 17.653 16.608 ;
     RECT  17.653 12.48 17.707 16.608 ;
     RECT  17.515 29.504 17.747 30.048 ;
     RECT  17.707 13.056 17.781 16.608 ;
     RECT  17.747 29.504 17.795 29.92 ;
     RECT  17.795 29.632 17.939 29.92 ;
     RECT  17.781 13.056 17.941 17.056 ;
     RECT  17.557 18.624 17.941 27.936 ;
     RECT  17.941 13.056 17.963 27.936 ;
     RECT  17.963 13.056 18.323 21.728 ;
     RECT  18.323 13.056 19.477 20 ;
     RECT  17.939 29.632 19.523 29.792 ;
     RECT  18.323 21.44 19.669 21.728 ;
     RECT  17.963 23.168 19.669 27.936 ;
     RECT  19.477 12.544 19.701 20 ;
     RECT  19.669 21.44 19.701 27.936 ;
     RECT  16.835 7.929 19.813 8.601 ;
     RECT  18.325 5.44 19.829 5.472 ;
     RECT  19.523 29.76 19.829 29.792 ;
     RECT  19.829 29.76 19.893 29.92 ;
     RECT  19.813 6.848 19.938 8.601 ;
     RECT  2.16 2.529 20.149 3.201 ;
     RECT  19.829 4.8 20.149 5.472 ;
     RECT  19.938 6.848 20.469 8.864 ;
     RECT  20.469 6.848 20.821 8.992 ;
     RECT  19.893 29.76 20.853 30.048 ;
     RECT  20.149 2.529 20.869 5.472 ;
     RECT  20.821 6.848 20.869 9.248 ;
     RECT  19.957 10.816 21.045 10.848 ;
     RECT  19.701 12.544 21.045 27.936 ;
     RECT  20.981 0.192 21.059 0.224 ;
     RECT  21.045 10.816 21.155 27.936 ;
     RECT  20.869 2.529 21.178 9.248 ;
     RECT  21.178 4.8 21.37 9.248 ;
     RECT  21.37 7.808 21.589 9.248 ;
     RECT  21.155 10.816 21.589 11.552 ;
     RECT  21.178 2.529 21.621 3.36 ;
     RECT  21.589 7.808 21.675 11.552 ;
     RECT  21.621 2.368 21.683 3.36 ;
     RECT  21.37 4.8 21.683 6.496 ;
     RECT  21.155 12.864 21.875 27.936 ;
     RECT  20.853 29.632 21.875 30.048 ;
     RECT  21.683 4.8 22.499 4.832 ;
     RECT  21.875 29.76 22.626 30.048 ;
     RECT  22.626 29.76 22.699 30.112 ;
     RECT  21.675 11.008 22.709 11.552 ;
     RECT  21.875 12.864 22.709 27.616 ;
     RECT  21.683 6.464 22.837 6.496 ;
     RECT  21.675 7.808 22.837 9.248 ;
     RECT  22.837 6.464 22.891 9.248 ;
     RECT  22.709 11.008 22.958 27.616 ;
     RECT  21.683 2.368 23.029 3.201 ;
     RECT  23.029 2.368 23.075 3.424 ;
     RECT  23.075 2.529 23.157 3.424 ;
     RECT  22.958 10.304 23.605 27.616 ;
     RECT  22.699 29.76 23.845 30.048 ;
     RECT  23.157 2.529 23.861 4.512 ;
     RECT  22.891 6.464 23.861 8.928 ;
     RECT  23.605 10.304 24.179 28.256 ;
     RECT  23.861 2.529 24.245 8.928 ;
     RECT  24.179 10.304 24.245 27.936 ;
     RECT  23.845 29.632 24.363 30.048 ;
     RECT  24.245 2.529 24.373 27.936 ;
     RECT  23.861 0.192 24.437 0.224 ;
     RECT  24.437 0.192 25.013 0.352 ;
     RECT  24.363 29.76 25.429 30.048 ;
     RECT  25.429 29.76 25.707 30.112 ;
     RECT  24.373 2.24 25.763 27.936 ;
     RECT  25.763 2.368 25.835 27.936 ;
     RECT  25.707 29.76 25.845 30.048 ;
     RECT  25.845 29.632 25.955 30.048 ;
     RECT  25.835 5.056 26.053 27.936 ;
     RECT  25.013 0.192 26.155 0.48 ;
     RECT  26.053 5.056 26.155 28 ;
     RECT  25.835 2.368 26.339 3.68 ;
     RECT  26.155 0.32 26.579 0.48 ;
     RECT  26.155 5.056 26.627 27.808 ;
     RECT  25.955 29.76 27.051 30.048 ;
     RECT  26.339 2.529 27.637 3.68 ;
     RECT  26.627 5.056 27.637 27.424 ;
     RECT  27.637 2.529 28.213 27.424 ;
     RECT  28.213 1.728 28.405 27.424 ;
     RECT  27.589 0.192 28.501 0.224 ;
     RECT  28.405 1.728 28.501 27.808 ;
     RECT  28.501 0.192 28.547 27.808 ;
     RECT  28.547 2.24 28.651 27.808 ;
     RECT  28.651 2.304 28.798 27.808 ;
     RECT  28.798 5.632 28.853 27.808 ;
     RECT  27.051 29.888 28.853 30.048 ;
     RECT  28.853 5.632 29.05 30.048 ;
     RECT  29.05 18.496 29.123 30.048 ;
     RECT  28.798 2.304 29.219 4.32 ;
     RECT  28.547 0.192 29.227 0.544 ;
     RECT  29.219 2.368 29.611 4.32 ;
     RECT  29.611 2.529 29.867 4.32 ;
     RECT  29.05 5.632 30.083 17.12 ;
     RECT  30.083 5.632 30.085 10.592 ;
     RECT  30.085 5.056 30.187 10.592 ;
     RECT  30.083 12.288 30.373 17.12 ;
     RECT  29.123 18.496 30.373 27.936 ;
     RECT  29.227 0.256 30.757 0.544 ;
     RECT  30.373 12.288 30.851 27.936 ;
     RECT  29.123 29.76 31.093 30.048 ;
     RECT  31.093 29.632 31.187 30.048 ;
     RECT  30.851 12.288 31.275 14.304 ;
     RECT  30.757 0.192 31.523 0.544 ;
     RECT  30.187 5.696 31.525 10.592 ;
     RECT  31.525 5.632 31.659 10.592 ;
     RECT  31.659 6.528 31.715 8.601 ;
     RECT  31.275 12.288 32.003 14.112 ;
     RECT  30.851 15.744 32.437 27.808 ;
     RECT  31.659 10.56 32.675 10.592 ;
     RECT  32.437 15.744 32.747 27.936 ;
     RECT  32.003 12.416 32.819 14.112 ;
     RECT  31.523 0.256 33.109 0.544 ;
     RECT  31.187 29.696 33.301 30.048 ;
     RECT  31.715 6.528 33.378 6.56 ;
     RECT  31.715 7.929 33.378 8.601 ;
     RECT  33.109 0.192 33.395 0.544 ;
     RECT  32.747 15.744 33.683 15.776 ;
     RECT  32.819 13.329 33.909 14.112 ;
     RECT  32.747 17.6 33.971 27.936 ;
     RECT  33.378 6.528 34.117 8.601 ;
     RECT  33.971 17.6 34.165 27.808 ;
     RECT  33.013 10.304 34.211 10.336 ;
     RECT  34.117 5.888 34.229 8.601 ;
     RECT  34.229 5.12 34.283 8.601 ;
     RECT  33.909 13.329 34.357 14.24 ;
     RECT  34.357 13.184 34.451 14.24 ;
     RECT  34.283 6.528 34.997 8.601 ;
     RECT  34.997 6.528 35.051 8.736 ;
     RECT  35.051 7.929 35.219 8.736 ;
     RECT  34.165 15.872 35.253 27.808 ;
     RECT  34.283 5.12 35.411 5.152 ;
     RECT  33.301 29.632 35.765 30.048 ;
     RECT  29.867 2.529 35.829 3.201 ;
     RECT  34.451 13.329 35.989 14.24 ;
     RECT  35.253 15.872 35.989 27.936 ;
     RECT  35.765 29.504 36.133 30.048 ;
     RECT  36.469 11.968 37.285 12 ;
     RECT  35.989 13.329 37.285 27.936 ;
     RECT  37.285 11.968 37.355 27.936 ;
     RECT  36.133 29.44 37.573 30.048 ;
     RECT  37.355 11.968 37.667 12 ;
     RECT  33.395 0.192 37.957 0.48 ;
     RECT  35.829 2.529 38.101 3.424 ;
     RECT  38.101 2.24 38.133 3.424 ;
     RECT  38.133 2.24 38.149 3.552 ;
     RECT  37.355 13.329 38.187 27.936 ;
     RECT  37.573 29.376 38.187 30.048 ;
     RECT  37.957 0.192 38.245 0.544 ;
     RECT  38.245 0.192 38.261 0.608 ;
     RECT  38.149 2.24 38.261 4.064 ;
     RECT  38.187 29.504 38.699 30.048 ;
     RECT  38.187 21.568 38.819 27.936 ;
     RECT  38.187 13.329 38.867 19.936 ;
     RECT  38.699 29.504 38.891 29.536 ;
     RECT  38.261 0.192 38.915 4.064 ;
     RECT  38.867 13.329 39.083 19.744 ;
     RECT  39.083 13.329 39.211 14.624 ;
     RECT  39.083 16.128 39.211 19.744 ;
     RECT  39.211 16.128 39.275 16.608 ;
     RECT  38.915 0.32 39.347 4.064 ;
     RECT  39.347 0.448 39.395 4.064 ;
     RECT  35.051 6.528 39.395 6.56 ;
     RECT  38.819 21.568 39.539 27.424 ;
     RECT  39.669 21.184 39.779 21.216 ;
     RECT  39.253 10.304 39.781 10.336 ;
     RECT  39.395 0.448 39.827 0.544 ;
     RECT  39.395 2.529 39.829 4.064 ;
     RECT  35.219 7.929 39.861 8.601 ;
     RECT  39.829 2.529 39.915 4.576 ;
     RECT  39.275 16.576 39.923 16.608 ;
     RECT  39.827 0.512 40.067 0.544 ;
     RECT  39.861 7.424 40.067 8.601 ;
     RECT  39.211 13.329 40.069 14.001 ;
     RECT  40.069 12.992 40.597 14.001 ;
     RECT  39.539 23.104 40.683 27.424 ;
     RECT  39.211 18.624 40.693 19.744 ;
     RECT  40.693 18.624 40.787 20 ;
     RECT  40.683 23.104 40.835 26.4 ;
     RECT  40.787 18.729 40.883 20 ;
     RECT  40.835 23.104 40.883 25.376 ;
     RECT  40.067 7.744 40.885 8.601 ;
     RECT  39.781 10.304 40.885 10.4 ;
     RECT  40.885 7.744 40.939 10.4 ;
     RECT  40.939 7.929 40.979 10.336 ;
     RECT  40.597 11.84 41.067 14.001 ;
     RECT  41.067 12.992 41.411 14.001 ;
     RECT  40.979 10.304 41.459 10.336 ;
     RECT  41.411 13.329 42.277 14.001 ;
     RECT  41.077 16 42.277 16.032 ;
     RECT  42.277 13.329 42.347 16.032 ;
     RECT  40.883 23.104 42.611 24.801 ;
     RECT  39.915 2.529 42.803 3.36 ;
     RECT  40.981 6.208 42.803 6.24 ;
     RECT  42.347 16 42.803 16.032 ;
     RECT  42.611 23.232 43.317 24.801 ;
     RECT  43.317 23.232 43.371 25.44 ;
     RECT  43.371 24.129 43.39 25.44 ;
     RECT  42.803 2.529 50.49 3.201 ;
     RECT  40.979 7.929 50.49 8.601 ;
     RECT  42.347 13.329 50.49 14.001 ;
     RECT  40.883 18.729 50.49 19.401 ;
     RECT  43.39 24.129 50.49 24.801 ;
    LAYER M7 ;
     RECT  27.648 0.181 29.216 0.245 ;
     RECT  33.28 0.181 33.312 0.245 ;
     RECT  32.96 0.245 33.312 0.427 ;
     RECT  34.944 0.181 35.872 0.427 ;
     RECT  32.96 0.427 32.992 0.491 ;
     RECT  38.272 0.565 38.304 1.771 ;
     RECT  20.992 0.181 21.024 2.357 ;
     RECT  23.872 0.181 26.144 2.357 ;
     RECT  27.648 0.245 30.368 3.381 ;
     RECT  35.84 0.427 35.872 3.435 ;
     RECT  38.144 2.229 38.176 3.563 ;
     RECT  22.976 2.357 26.144 3.637 ;
     RECT  27.52 3.381 30.368 3.637 ;
     RECT  20.992 2.357 21.664 4.277 ;
     RECT  20.16 4.277 21.664 4.789 ;
     RECT  22.976 3.637 30.368 5.621 ;
     RECT  19.84 4.789 21.664 5.739 ;
     RECT  22.976 5.621 31.648 5.739 ;
     RECT  34.24 5.109 34.272 5.931 ;
     RECT  22.976 5.739 30.176 6.507 ;
     RECT  22.976 6.507 29.984 6.837 ;
     RECT  19.84 5.739 21.344 6.891 ;
     RECT  39.872 4.533 39.904 7.467 ;
     RECT  20.16 6.891 21.344 7.797 ;
     RECT  22.848 6.837 29.984 7.797 ;
     RECT  35.008 7.349 35.04 8.747 ;
     RECT  20.16 7.797 30.112 8.821 ;
     RECT  9.728 7.797 9.76 9.195 ;
     RECT  19.968 8.821 30.112 9.717 ;
     RECT  31.616 5.739 31.648 9.717 ;
     RECT  12.48 9.077 12.512 9.771 ;
     RECT  19.968 9.717 31.648 9.771 ;
     RECT  19.968 9.771 31.328 9.899 ;
     RECT  40.896 7.733 40.928 10.293 ;
     RECT  33.408 7.797 33.44 10.347 ;
     RECT  40.896 10.293 41.056 10.411 ;
     RECT  19.968 9.899 29.728 10.859 ;
     RECT  17.152 10.229 17.184 11.435 ;
     RECT  20.224 10.859 29.728 11.893 ;
     RECT  20.224 11.893 29.92 12.277 ;
     RECT  31.296 9.899 31.328 12.277 ;
     RECT  14.848 6.197 14.88 12.523 ;
     RECT  41.024 10.411 41.056 13.035 ;
     RECT  17.664 12.469 17.696 13.045 ;
     RECT  20.224 12.277 31.328 13.045 ;
     RECT  15.936 12.917 15.968 14.123 ;
     RECT  34.368 13.173 34.4 14.197 ;
     RECT  37.312 12.469 37.344 14.645 ;
     RECT  33.92 14.197 35.424 14.773 ;
     RECT  36.992 14.645 37.344 14.773 ;
     RECT  39.168 14.581 39.2 14.773 ;
     RECT  42.304 14.773 42.336 16.043 ;
     RECT  33.92 14.773 39.2 16.117 ;
     RECT  17.344 13.045 31.328 16.501 ;
     RECT  33.92 16.117 39.264 16.949 ;
     RECT  17.024 16.501 31.328 17.461 ;
     RECT  32.704 16.949 39.264 17.461 ;
     RECT  17.024 17.461 39.264 17.707 ;
     RECT  12.544 17.589 12.576 18.613 ;
     RECT  12.544 18.613 12.704 18.667 ;
     RECT  17.024 17.707 29.92 18.667 ;
     RECT  31.232 17.707 39.264 19.509 ;
     RECT  40.704 18.613 40.736 19.509 ;
     RECT  12.672 18.667 12.704 19.637 ;
     RECT  31.232 19.509 40.736 20.011 ;
     RECT  17.28 18.667 29.92 20.469 ;
     RECT  31.232 20.011 39.84 20.469 ;
     RECT  12.672 19.637 13.536 20.981 ;
     RECT  12.672 20.981 14.432 21.045 ;
     RECT  12.672 21.045 14.752 21.163 ;
     RECT  13.504 21.163 14.752 21.301 ;
     RECT  13.504 21.301 15.968 23.285 ;
     RECT  17.28 20.469 39.84 23.285 ;
     RECT  13.504 23.285 39.84 23.861 ;
     RECT  13.504 23.861 39.904 24.043 ;
     RECT  13.568 24.043 39.904 25.333 ;
     RECT  13.568 25.333 40.416 25.397 ;
     RECT  43.328 23.221 43.36 25.451 ;
     RECT  13.568 25.397 40.672 26.987 ;
     RECT  13.696 26.987 40.672 27.435 ;
     RECT  13.696 27.435 38.88 29.547 ;
     RECT  13.696 29.547 38.688 29.803 ;
     RECT  13.952 29.803 17.632 29.931 ;
     RECT  19.84 29.803 38.688 29.931 ;
     RECT  19.904 29.931 38.688 29.995 ;
     RECT  13.952 29.931 17.504 30.059 ;
     RECT  19.904 29.995 34.656 30.059 ;
     RECT  36.416 29.995 38.688 30.059 ;
     RECT  22.656 30.059 22.688 30.123 ;
     RECT  25.664 30.059 25.696 30.123 ;
     RECT  15.04 30.059 17.504 30.187 ;
  END
END ot_qwen_die_station
END LIBRARY
